VERSION 5.8 ;
BUSBITCHARS "[]" ;
DIVIDERCHAR "/" ;
UNITS
    DATABASE MICRONS 1000 ;
END UNITS

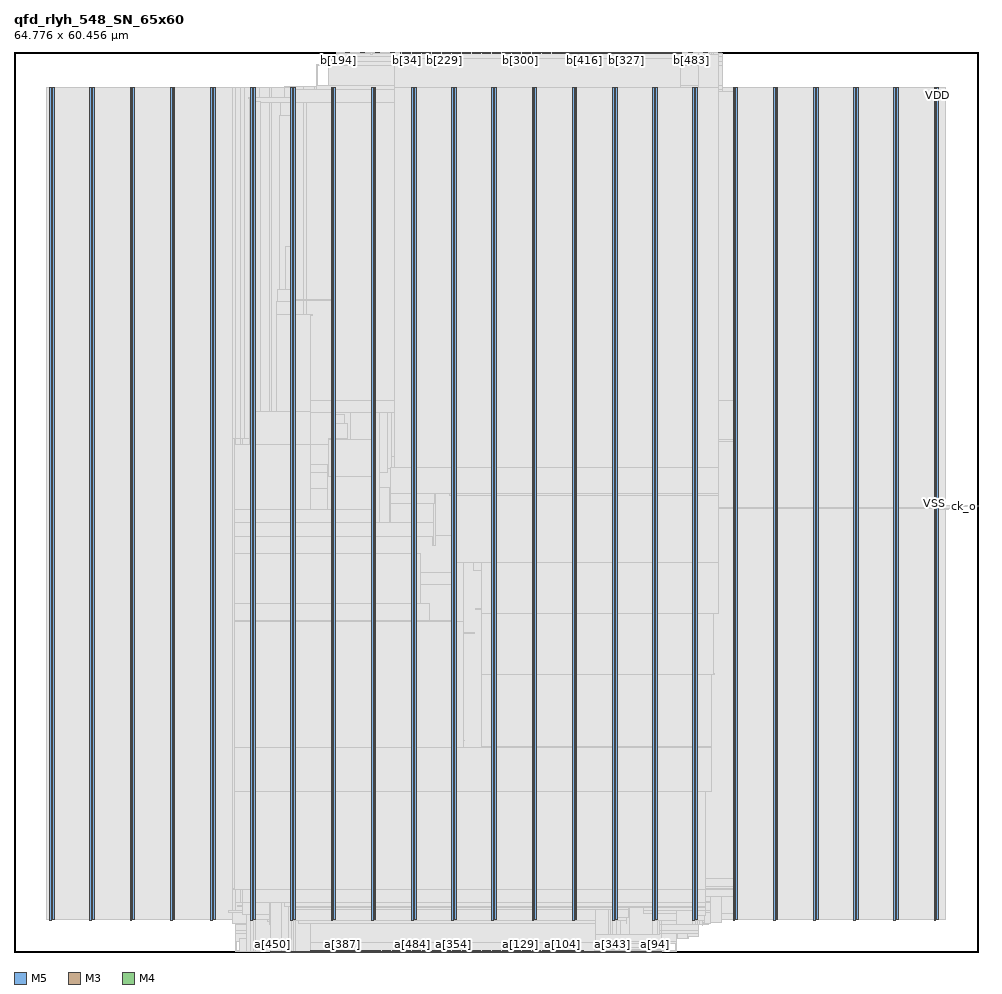
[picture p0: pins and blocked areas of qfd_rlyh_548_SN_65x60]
MACRO qfd_rlyh_548_SN_65x60
  FOREIGN qfd_rlyh_548_SN_65x60 0 0 ;
  CLASS BLOCK ;
  SIZE 64.776 BY 60.456 ;
  PIN a[0]
    DIRECTION INPUT ;
    USE SIGNAL ;
    PORT
      LAYER M5 ;
        RECT  35.28 0 35.304 0.084 ;
    END
  END a[0]
  PIN a[100]
    DIRECTION INPUT ;
    USE SIGNAL ;
    PORT
      LAYER M3 ;
        RECT  36.54 0 36.558 0.037 ;
    END
  END a[100]
  PIN a[101]
    DIRECTION INPUT ;
    USE SIGNAL ;
    PORT
      LAYER M3 ;
        RECT  36.612 0 36.63 0.037 ;
    END
  END a[101]
  PIN a[102]
    DIRECTION INPUT ;
    USE SIGNAL ;
    PORT
      LAYER M3 ;
        RECT  36.684 0 36.702 0.037 ;
    END
  END a[102]
  PIN a[103]
    DIRECTION INPUT ;
    USE SIGNAL ;
    PORT
      LAYER M3 ;
        RECT  36.756 0 36.774 0.037 ;
    END
  END a[103]
  PIN a[104]
    DIRECTION INPUT ;
    USE SIGNAL ;
    PORT
      LAYER M3 ;
        RECT  36.828 0 36.846 0.037 ;
    END
  END a[104]
  PIN a[105]
    DIRECTION INPUT ;
    USE SIGNAL ;
    PORT
      LAYER M3 ;
        RECT  36.9 0 36.918 0.037 ;
    END
  END a[105]
  PIN a[106]
    DIRECTION INPUT ;
    USE SIGNAL ;
    PORT
      LAYER M3 ;
        RECT  36.972 0 36.99 0.037 ;
    END
  END a[106]
  PIN a[107]
    DIRECTION INPUT ;
    USE SIGNAL ;
    PORT
      LAYER M3 ;
        RECT  37.044 0 37.062 0.037 ;
    END
  END a[107]
  PIN a[108]
    DIRECTION INPUT ;
    USE SIGNAL ;
    PORT
      LAYER M3 ;
        RECT  37.116 0 37.134 0.037 ;
    END
  END a[108]
  PIN a[109]
    DIRECTION INPUT ;
    USE SIGNAL ;
    PORT
      LAYER M3 ;
        RECT  37.188 0 37.206 0.037 ;
    END
  END a[109]
  PIN a[10]
    DIRECTION INPUT ;
    USE SIGNAL ;
    PORT
      LAYER M5 ;
        RECT  36.24 0 36.264 0.084 ;
    END
  END a[10]
  PIN a[110]
    DIRECTION INPUT ;
    USE SIGNAL ;
    PORT
      LAYER M3 ;
        RECT  37.26 0 37.278 0.037 ;
    END
  END a[110]
  PIN a[111]
    DIRECTION INPUT ;
    USE SIGNAL ;
    PORT
      LAYER M3 ;
        RECT  37.332 0 37.35 0.037 ;
    END
  END a[111]
  PIN a[112]
    DIRECTION INPUT ;
    USE SIGNAL ;
    PORT
      LAYER M3 ;
        RECT  37.404 0 37.422 0.037 ;
    END
  END a[112]
  PIN a[113]
    DIRECTION INPUT ;
    USE SIGNAL ;
    PORT
      LAYER M3 ;
        RECT  37.476 0 37.494 0.037 ;
    END
  END a[113]
  PIN a[114]
    DIRECTION INPUT ;
    USE SIGNAL ;
    PORT
      LAYER M3 ;
        RECT  37.548 0 37.566 0.037 ;
    END
  END a[114]
  PIN a[115]
    DIRECTION INPUT ;
    USE SIGNAL ;
    PORT
      LAYER M3 ;
        RECT  37.62 0 37.638 0.037 ;
    END
  END a[115]
  PIN a[116]
    DIRECTION INPUT ;
    USE SIGNAL ;
    PORT
      LAYER M3 ;
        RECT  37.692 0 37.71 0.037 ;
    END
  END a[116]
  PIN a[117]
    DIRECTION INPUT ;
    USE SIGNAL ;
    PORT
      LAYER M3 ;
        RECT  37.764 0 37.782 0.037 ;
    END
  END a[117]
  PIN a[118]
    DIRECTION INPUT ;
    USE SIGNAL ;
    PORT
      LAYER M3 ;
        RECT  37.836 0 37.854 0.037 ;
    END
  END a[118]
  PIN a[119]
    DIRECTION INPUT ;
    USE SIGNAL ;
    PORT
      LAYER M3 ;
        RECT  37.908 0 37.926 0.037 ;
    END
  END a[119]
  PIN a[11]
    DIRECTION INPUT ;
    USE SIGNAL ;
    PORT
      LAYER M5 ;
        RECT  36.336 0 36.36 0.084 ;
    END
  END a[11]
  PIN a[120]
    DIRECTION INPUT ;
    USE SIGNAL ;
    PORT
      LAYER M3 ;
        RECT  37.98 0 37.998 0.037 ;
    END
  END a[120]
  PIN a[121]
    DIRECTION INPUT ;
    USE SIGNAL ;
    PORT
      LAYER M3 ;
        RECT  38.052 0 38.07 0.037 ;
    END
  END a[121]
  PIN a[122]
    DIRECTION INPUT ;
    USE SIGNAL ;
    PORT
      LAYER M3 ;
        RECT  38.124 0 38.142 0.037 ;
    END
  END a[122]
  PIN a[123]
    DIRECTION INPUT ;
    USE SIGNAL ;
    PORT
      LAYER M3 ;
        RECT  38.196 0 38.214 0.037 ;
    END
  END a[123]
  PIN a[124]
    DIRECTION INPUT ;
    USE SIGNAL ;
    PORT
      LAYER M3 ;
        RECT  38.268 0 38.286 0.037 ;
    END
  END a[124]
  PIN a[125]
    DIRECTION INPUT ;
    USE SIGNAL ;
    PORT
      LAYER M3 ;
        RECT  38.34 0 38.358 0.037 ;
    END
  END a[125]
  PIN a[126]
    DIRECTION INPUT ;
    USE SIGNAL ;
    PORT
      LAYER M3 ;
        RECT  38.412 0 38.43 0.037 ;
    END
  END a[126]
  PIN a[127]
    DIRECTION INPUT ;
    USE SIGNAL ;
    PORT
      LAYER M3 ;
        RECT  38.484 0 38.502 0.037 ;
    END
  END a[127]
  PIN a[128]
    DIRECTION INPUT ;
    USE SIGNAL ;
    PORT
      LAYER M3 ;
        RECT  33.948 0 33.966 0.037 ;
    END
  END a[128]
  PIN a[129]
    DIRECTION INPUT ;
    USE SIGNAL ;
    PORT
      LAYER M3 ;
        RECT  34.02 0 34.038 0.037 ;
    END
  END a[129]
  PIN a[12]
    DIRECTION INPUT ;
    USE SIGNAL ;
    PORT
      LAYER M5 ;
        RECT  36.432 0 36.456 0.084 ;
    END
  END a[12]
  PIN a[130]
    DIRECTION INPUT ;
    USE SIGNAL ;
    PORT
      LAYER M3 ;
        RECT  34.092 0 34.11 0.037 ;
    END
  END a[130]
  PIN a[131]
    DIRECTION INPUT ;
    USE SIGNAL ;
    PORT
      LAYER M3 ;
        RECT  34.164 0 34.182 0.037 ;
    END
  END a[131]
  PIN a[132]
    DIRECTION INPUT ;
    USE SIGNAL ;
    PORT
      LAYER M3 ;
        RECT  34.236 0 34.254 0.037 ;
    END
  END a[132]
  PIN a[133]
    DIRECTION INPUT ;
    USE SIGNAL ;
    PORT
      LAYER M3 ;
        RECT  34.308 0 34.326 0.037 ;
    END
  END a[133]
  PIN a[134]
    DIRECTION INPUT ;
    USE SIGNAL ;
    PORT
      LAYER M3 ;
        RECT  34.38 0 34.398 0.037 ;
    END
  END a[134]
  PIN a[135]
    DIRECTION INPUT ;
    USE SIGNAL ;
    PORT
      LAYER M3 ;
        RECT  34.452 0 34.47 0.037 ;
    END
  END a[135]
  PIN a[136]
    DIRECTION INPUT ;
    USE SIGNAL ;
    PORT
      LAYER M3 ;
        RECT  34.524 0 34.542 0.037 ;
    END
  END a[136]
  PIN a[137]
    DIRECTION INPUT ;
    USE SIGNAL ;
    PORT
      LAYER M3 ;
        RECT  34.596 0 34.614 0.037 ;
    END
  END a[137]
  PIN a[138]
    DIRECTION INPUT ;
    USE SIGNAL ;
    PORT
      LAYER M3 ;
        RECT  34.668 0 34.686 0.037 ;
    END
  END a[138]
  PIN a[139]
    DIRECTION INPUT ;
    USE SIGNAL ;
    PORT
      LAYER M3 ;
        RECT  34.74 0 34.758 0.037 ;
    END
  END a[139]
  PIN a[13]
    DIRECTION INPUT ;
    USE SIGNAL ;
    PORT
      LAYER M5 ;
        RECT  36.528 0 36.552 0.084 ;
    END
  END a[13]
  PIN a[140]
    DIRECTION INPUT ;
    USE SIGNAL ;
    PORT
      LAYER M3 ;
        RECT  34.812 0 34.83 0.037 ;
    END
  END a[140]
  PIN a[141]
    DIRECTION INPUT ;
    USE SIGNAL ;
    PORT
      LAYER M3 ;
        RECT  34.884 0 34.902 0.037 ;
    END
  END a[141]
  PIN a[142]
    DIRECTION INPUT ;
    USE SIGNAL ;
    PORT
      LAYER M3 ;
        RECT  34.956 0 34.974 0.037 ;
    END
  END a[142]
  PIN a[143]
    DIRECTION INPUT ;
    USE SIGNAL ;
    PORT
      LAYER M3 ;
        RECT  35.028 0 35.046 0.037 ;
    END
  END a[143]
  PIN a[144]
    DIRECTION INPUT ;
    USE SIGNAL ;
    PORT
      LAYER M3 ;
        RECT  35.1 0 35.118 0.037 ;
    END
  END a[144]
  PIN a[145]
    DIRECTION INPUT ;
    USE SIGNAL ;
    PORT
      LAYER M3 ;
        RECT  35.172 0 35.19 0.037 ;
    END
  END a[145]
  PIN a[146]
    DIRECTION INPUT ;
    USE SIGNAL ;
    PORT
      LAYER M3 ;
        RECT  35.244 0 35.262 0.037 ;
    END
  END a[146]
  PIN a[147]
    DIRECTION INPUT ;
    USE SIGNAL ;
    PORT
      LAYER M3 ;
        RECT  35.316 0 35.334 0.037 ;
    END
  END a[147]
  PIN a[148]
    DIRECTION INPUT ;
    USE SIGNAL ;
    PORT
      LAYER M3 ;
        RECT  35.388 0 35.406 0.037 ;
    END
  END a[148]
  PIN a[149]
    DIRECTION INPUT ;
    USE SIGNAL ;
    PORT
      LAYER M3 ;
        RECT  35.46 0 35.478 0.037 ;
    END
  END a[149]
  PIN a[14]
    DIRECTION INPUT ;
    USE SIGNAL ;
    PORT
      LAYER M5 ;
        RECT  36.624 0 36.648 0.084 ;
    END
  END a[14]
  PIN a[150]
    DIRECTION INPUT ;
    USE SIGNAL ;
    PORT
      LAYER M3 ;
        RECT  35.532 0 35.55 0.037 ;
    END
  END a[150]
  PIN a[151]
    DIRECTION INPUT ;
    USE SIGNAL ;
    PORT
      LAYER M3 ;
        RECT  35.604 0 35.622 0.037 ;
    END
  END a[151]
  PIN a[152]
    DIRECTION INPUT ;
    USE SIGNAL ;
    PORT
      LAYER M3 ;
        RECT  35.676 0 35.694 0.037 ;
    END
  END a[152]
  PIN a[153]
    DIRECTION INPUT ;
    USE SIGNAL ;
    PORT
      LAYER M3 ;
        RECT  35.748 0 35.766 0.037 ;
    END
  END a[153]
  PIN a[154]
    DIRECTION INPUT ;
    USE SIGNAL ;
    PORT
      LAYER M3 ;
        RECT  35.82 0 35.838 0.037 ;
    END
  END a[154]
  PIN a[155]
    DIRECTION INPUT ;
    USE SIGNAL ;
    PORT
      LAYER M3 ;
        RECT  35.892 0 35.91 0.037 ;
    END
  END a[155]
  PIN a[156]
    DIRECTION INPUT ;
    USE SIGNAL ;
    PORT
      LAYER M3 ;
        RECT  35.964 0 35.982 0.037 ;
    END
  END a[156]
  PIN a[157]
    DIRECTION INPUT ;
    USE SIGNAL ;
    PORT
      LAYER M3 ;
        RECT  36.036 0 36.054 0.037 ;
    END
  END a[157]
  PIN a[158]
    DIRECTION INPUT ;
    USE SIGNAL ;
    PORT
      LAYER M3 ;
        RECT  36.108 0 36.126 0.037 ;
    END
  END a[158]
  PIN a[159]
    DIRECTION INPUT ;
    USE SIGNAL ;
    PORT
      LAYER M3 ;
        RECT  36.18 0 36.198 0.037 ;
    END
  END a[159]
  PIN a[15]
    DIRECTION INPUT ;
    USE SIGNAL ;
    PORT
      LAYER M5 ;
        RECT  36.72 0 36.744 0.084 ;
    END
  END a[15]
  PIN a[160]
    DIRECTION INPUT ;
    USE SIGNAL ;
    PORT
      LAYER M5 ;
        RECT  22.992 0 23.016 0.084 ;
    END
  END a[160]
  PIN a[161]
    DIRECTION INPUT ;
    USE SIGNAL ;
    PORT
      LAYER M5 ;
        RECT  23.088 0 23.112 0.084 ;
    END
  END a[161]
  PIN a[162]
    DIRECTION INPUT ;
    USE SIGNAL ;
    PORT
      LAYER M5 ;
        RECT  23.184 0 23.208 0.084 ;
    END
  END a[162]
  PIN a[163]
    DIRECTION INPUT ;
    USE SIGNAL ;
    PORT
      LAYER M5 ;
        RECT  23.28 0 23.304 0.084 ;
    END
  END a[163]
  PIN a[164]
    DIRECTION INPUT ;
    USE SIGNAL ;
    PORT
      LAYER M5 ;
        RECT  23.376 0 23.4 0.084 ;
    END
  END a[164]
  PIN a[165]
    DIRECTION INPUT ;
    USE SIGNAL ;
    PORT
      LAYER M5 ;
        RECT  23.472 0 23.496 0.084 ;
    END
  END a[165]
  PIN a[166]
    DIRECTION INPUT ;
    USE SIGNAL ;
    PORT
      LAYER M5 ;
        RECT  23.568 0 23.592 0.084 ;
    END
  END a[166]
  PIN a[167]
    DIRECTION INPUT ;
    USE SIGNAL ;
    PORT
      LAYER M5 ;
        RECT  23.664 0 23.688 0.084 ;
    END
  END a[167]
  PIN a[168]
    DIRECTION INPUT ;
    USE SIGNAL ;
    PORT
      LAYER M5 ;
        RECT  23.76 0 23.784 0.084 ;
    END
  END a[168]
  PIN a[169]
    DIRECTION INPUT ;
    USE SIGNAL ;
    PORT
      LAYER M5 ;
        RECT  23.856 0 23.88 0.084 ;
    END
  END a[169]
  PIN a[16]
    DIRECTION INPUT ;
    USE SIGNAL ;
    PORT
      LAYER M5 ;
        RECT  36.816 0 36.84 0.084 ;
    END
  END a[16]
  PIN a[170]
    DIRECTION INPUT ;
    USE SIGNAL ;
    PORT
      LAYER M5 ;
        RECT  23.952 0 23.976 0.084 ;
    END
  END a[170]
  PIN a[171]
    DIRECTION INPUT ;
    USE SIGNAL ;
    PORT
      LAYER M5 ;
        RECT  24.048 0 24.072 0.084 ;
    END
  END a[171]
  PIN a[172]
    DIRECTION INPUT ;
    USE SIGNAL ;
    PORT
      LAYER M5 ;
        RECT  24.144 0 24.168 0.084 ;
    END
  END a[172]
  PIN a[173]
    DIRECTION INPUT ;
    USE SIGNAL ;
    PORT
      LAYER M5 ;
        RECT  24.24 0 24.264 0.084 ;
    END
  END a[173]
  PIN a[174]
    DIRECTION INPUT ;
    USE SIGNAL ;
    PORT
      LAYER M5 ;
        RECT  24.336 0 24.36 0.084 ;
    END
  END a[174]
  PIN a[175]
    DIRECTION INPUT ;
    USE SIGNAL ;
    PORT
      LAYER M5 ;
        RECT  24.432 0 24.456 0.084 ;
    END
  END a[175]
  PIN a[176]
    DIRECTION INPUT ;
    USE SIGNAL ;
    PORT
      LAYER M5 ;
        RECT  24.528 0 24.552 0.084 ;
    END
  END a[176]
  PIN a[177]
    DIRECTION INPUT ;
    USE SIGNAL ;
    PORT
      LAYER M5 ;
        RECT  24.624 0 24.648 0.084 ;
    END
  END a[177]
  PIN a[178]
    DIRECTION INPUT ;
    USE SIGNAL ;
    PORT
      LAYER M5 ;
        RECT  24.72 0 24.744 0.084 ;
    END
  END a[178]
  PIN a[179]
    DIRECTION INPUT ;
    USE SIGNAL ;
    PORT
      LAYER M5 ;
        RECT  24.816 0 24.84 0.084 ;
    END
  END a[179]
  PIN a[17]
    DIRECTION INPUT ;
    USE SIGNAL ;
    PORT
      LAYER M5 ;
        RECT  36.912 0 36.936 0.084 ;
    END
  END a[17]
  PIN a[180]
    DIRECTION INPUT ;
    USE SIGNAL ;
    PORT
      LAYER M5 ;
        RECT  24.912 0 24.936 0.084 ;
    END
  END a[180]
  PIN a[181]
    DIRECTION INPUT ;
    USE SIGNAL ;
    PORT
      LAYER M5 ;
        RECT  25.008 0 25.032 0.084 ;
    END
  END a[181]
  PIN a[182]
    DIRECTION INPUT ;
    USE SIGNAL ;
    PORT
      LAYER M5 ;
        RECT  25.104 0 25.128 0.084 ;
    END
  END a[182]
  PIN a[183]
    DIRECTION INPUT ;
    USE SIGNAL ;
    PORT
      LAYER M5 ;
        RECT  25.2 0 25.224 0.084 ;
    END
  END a[183]
  PIN a[184]
    DIRECTION INPUT ;
    USE SIGNAL ;
    PORT
      LAYER M5 ;
        RECT  25.296 0 25.32 0.084 ;
    END
  END a[184]
  PIN a[185]
    DIRECTION INPUT ;
    USE SIGNAL ;
    PORT
      LAYER M5 ;
        RECT  25.392 0 25.416 0.084 ;
    END
  END a[185]
  PIN a[186]
    DIRECTION INPUT ;
    USE SIGNAL ;
    PORT
      LAYER M5 ;
        RECT  25.488 0 25.512 0.084 ;
    END
  END a[186]
  PIN a[187]
    DIRECTION INPUT ;
    USE SIGNAL ;
    PORT
      LAYER M5 ;
        RECT  25.584 0 25.608 0.084 ;
    END
  END a[187]
  PIN a[188]
    DIRECTION INPUT ;
    USE SIGNAL ;
    PORT
      LAYER M5 ;
        RECT  25.68 0 25.704 0.084 ;
    END
  END a[188]
  PIN a[189]
    DIRECTION INPUT ;
    USE SIGNAL ;
    PORT
      LAYER M5 ;
        RECT  25.776 0 25.8 0.084 ;
    END
  END a[189]
  PIN a[18]
    DIRECTION INPUT ;
    USE SIGNAL ;
    PORT
      LAYER M5 ;
        RECT  37.008 0 37.032 0.084 ;
    END
  END a[18]
  PIN a[190]
    DIRECTION INPUT ;
    USE SIGNAL ;
    PORT
      LAYER M5 ;
        RECT  25.872 0 25.896 0.084 ;
    END
  END a[190]
  PIN a[191]
    DIRECTION INPUT ;
    USE SIGNAL ;
    PORT
      LAYER M5 ;
        RECT  25.968 0 25.992 0.084 ;
    END
  END a[191]
  PIN a[192]
    DIRECTION INPUT ;
    USE SIGNAL ;
    PORT
      LAYER M5 ;
        RECT  19.92 0 19.944 0.084 ;
    END
  END a[192]
  PIN a[193]
    DIRECTION INPUT ;
    USE SIGNAL ;
    PORT
      LAYER M5 ;
        RECT  20.016 0 20.04 0.084 ;
    END
  END a[193]
  PIN a[194]
    DIRECTION INPUT ;
    USE SIGNAL ;
    PORT
      LAYER M5 ;
        RECT  20.112 0 20.136 0.084 ;
    END
  END a[194]
  PIN a[195]
    DIRECTION INPUT ;
    USE SIGNAL ;
    PORT
      LAYER M5 ;
        RECT  20.208 0 20.232 0.084 ;
    END
  END a[195]
  PIN a[196]
    DIRECTION INPUT ;
    USE SIGNAL ;
    PORT
      LAYER M5 ;
        RECT  20.304 0 20.328 0.084 ;
    END
  END a[196]
  PIN a[197]
    DIRECTION INPUT ;
    USE SIGNAL ;
    PORT
      LAYER M5 ;
        RECT  20.4 0 20.424 0.084 ;
    END
  END a[197]
  PIN a[198]
    DIRECTION INPUT ;
    USE SIGNAL ;
    PORT
      LAYER M5 ;
        RECT  20.496 0 20.52 0.084 ;
    END
  END a[198]
  PIN a[199]
    DIRECTION INPUT ;
    USE SIGNAL ;
    PORT
      LAYER M5 ;
        RECT  20.592 0 20.616 0.084 ;
    END
  END a[199]
  PIN a[19]
    DIRECTION INPUT ;
    USE SIGNAL ;
    PORT
      LAYER M5 ;
        RECT  37.104 0 37.128 0.084 ;
    END
  END a[19]
  PIN a[1]
    DIRECTION INPUT ;
    USE SIGNAL ;
    PORT
      LAYER M5 ;
        RECT  35.376 0 35.4 0.084 ;
    END
  END a[1]
  PIN a[200]
    DIRECTION INPUT ;
    USE SIGNAL ;
    PORT
      LAYER M5 ;
        RECT  20.688 0 20.712 0.084 ;
    END
  END a[200]
  PIN a[201]
    DIRECTION INPUT ;
    USE SIGNAL ;
    PORT
      LAYER M5 ;
        RECT  20.784 0 20.808 0.084 ;
    END
  END a[201]
  PIN a[202]
    DIRECTION INPUT ;
    USE SIGNAL ;
    PORT
      LAYER M5 ;
        RECT  20.88 0 20.904 0.084 ;
    END
  END a[202]
  PIN a[203]
    DIRECTION INPUT ;
    USE SIGNAL ;
    PORT
      LAYER M5 ;
        RECT  20.976 0 21 0.084 ;
    END
  END a[203]
  PIN a[204]
    DIRECTION INPUT ;
    USE SIGNAL ;
    PORT
      LAYER M5 ;
        RECT  21.072 0 21.096 0.084 ;
    END
  END a[204]
  PIN a[205]
    DIRECTION INPUT ;
    USE SIGNAL ;
    PORT
      LAYER M5 ;
        RECT  21.168 0 21.192 0.084 ;
    END
  END a[205]
  PIN a[206]
    DIRECTION INPUT ;
    USE SIGNAL ;
    PORT
      LAYER M5 ;
        RECT  21.264 0 21.288 0.084 ;
    END
  END a[206]
  PIN a[207]
    DIRECTION INPUT ;
    USE SIGNAL ;
    PORT
      LAYER M5 ;
        RECT  21.36 0 21.384 0.084 ;
    END
  END a[207]
  PIN a[208]
    DIRECTION INPUT ;
    USE SIGNAL ;
    PORT
      LAYER M5 ;
        RECT  21.456 0 21.48 0.084 ;
    END
  END a[208]
  PIN a[209]
    DIRECTION INPUT ;
    USE SIGNAL ;
    PORT
      LAYER M5 ;
        RECT  21.552 0 21.576 0.084 ;
    END
  END a[209]
  PIN a[20]
    DIRECTION INPUT ;
    USE SIGNAL ;
    PORT
      LAYER M5 ;
        RECT  37.2 0 37.224 0.084 ;
    END
  END a[20]
  PIN a[210]
    DIRECTION INPUT ;
    USE SIGNAL ;
    PORT
      LAYER M5 ;
        RECT  21.648 0 21.672 0.084 ;
    END
  END a[210]
  PIN a[211]
    DIRECTION INPUT ;
    USE SIGNAL ;
    PORT
      LAYER M5 ;
        RECT  21.744 0 21.768 0.084 ;
    END
  END a[211]
  PIN a[212]
    DIRECTION INPUT ;
    USE SIGNAL ;
    PORT
      LAYER M5 ;
        RECT  21.84 0 21.864 0.084 ;
    END
  END a[212]
  PIN a[213]
    DIRECTION INPUT ;
    USE SIGNAL ;
    PORT
      LAYER M5 ;
        RECT  21.936 0 21.96 0.084 ;
    END
  END a[213]
  PIN a[214]
    DIRECTION INPUT ;
    USE SIGNAL ;
    PORT
      LAYER M5 ;
        RECT  22.032 0 22.056 0.084 ;
    END
  END a[214]
  PIN a[215]
    DIRECTION INPUT ;
    USE SIGNAL ;
    PORT
      LAYER M5 ;
        RECT  22.128 0 22.152 0.084 ;
    END
  END a[215]
  PIN a[216]
    DIRECTION INPUT ;
    USE SIGNAL ;
    PORT
      LAYER M5 ;
        RECT  22.224 0 22.248 0.084 ;
    END
  END a[216]
  PIN a[217]
    DIRECTION INPUT ;
    USE SIGNAL ;
    PORT
      LAYER M5 ;
        RECT  22.32 0 22.344 0.084 ;
    END
  END a[217]
  PIN a[218]
    DIRECTION INPUT ;
    USE SIGNAL ;
    PORT
      LAYER M5 ;
        RECT  22.416 0 22.44 0.084 ;
    END
  END a[218]
  PIN a[219]
    DIRECTION INPUT ;
    USE SIGNAL ;
    PORT
      LAYER M5 ;
        RECT  22.512 0 22.536 0.084 ;
    END
  END a[219]
  PIN a[21]
    DIRECTION INPUT ;
    USE SIGNAL ;
    PORT
      LAYER M5 ;
        RECT  37.296 0 37.32 0.084 ;
    END
  END a[21]
  PIN a[220]
    DIRECTION INPUT ;
    USE SIGNAL ;
    PORT
      LAYER M5 ;
        RECT  22.608 0 22.632 0.084 ;
    END
  END a[220]
  PIN a[221]
    DIRECTION INPUT ;
    USE SIGNAL ;
    PORT
      LAYER M5 ;
        RECT  22.704 0 22.728 0.084 ;
    END
  END a[221]
  PIN a[222]
    DIRECTION INPUT ;
    USE SIGNAL ;
    PORT
      LAYER M5 ;
        RECT  22.8 0 22.824 0.084 ;
    END
  END a[222]
  PIN a[223]
    DIRECTION INPUT ;
    USE SIGNAL ;
    PORT
      LAYER M5 ;
        RECT  22.896 0 22.92 0.084 ;
    END
  END a[223]
  PIN a[224]
    DIRECTION INPUT ;
    USE SIGNAL ;
    PORT
      LAYER M5 ;
        RECT  29.136 0 29.16 0.084 ;
    END
  END a[224]
  PIN a[225]
    DIRECTION INPUT ;
    USE SIGNAL ;
    PORT
      LAYER M5 ;
        RECT  29.232 0 29.256 0.084 ;
    END
  END a[225]
  PIN a[226]
    DIRECTION INPUT ;
    USE SIGNAL ;
    PORT
      LAYER M5 ;
        RECT  29.328 0 29.352 0.084 ;
    END
  END a[226]
  PIN a[227]
    DIRECTION INPUT ;
    USE SIGNAL ;
    PORT
      LAYER M5 ;
        RECT  29.424 0 29.448 0.084 ;
    END
  END a[227]
  PIN a[228]
    DIRECTION INPUT ;
    USE SIGNAL ;
    PORT
      LAYER M5 ;
        RECT  29.52 0 29.544 0.084 ;
    END
  END a[228]
  PIN a[229]
    DIRECTION INPUT ;
    USE SIGNAL ;
    PORT
      LAYER M5 ;
        RECT  29.616 0 29.64 0.084 ;
    END
  END a[229]
  PIN a[22]
    DIRECTION INPUT ;
    USE SIGNAL ;
    PORT
      LAYER M5 ;
        RECT  37.392 0 37.416 0.084 ;
    END
  END a[22]
  PIN a[230]
    DIRECTION INPUT ;
    USE SIGNAL ;
    PORT
      LAYER M5 ;
        RECT  29.712 0 29.736 0.084 ;
    END
  END a[230]
  PIN a[231]
    DIRECTION INPUT ;
    USE SIGNAL ;
    PORT
      LAYER M5 ;
        RECT  29.808 0 29.832 0.084 ;
    END
  END a[231]
  PIN a[232]
    DIRECTION INPUT ;
    USE SIGNAL ;
    PORT
      LAYER M5 ;
        RECT  29.904 0 29.928 0.084 ;
    END
  END a[232]
  PIN a[233]
    DIRECTION INPUT ;
    USE SIGNAL ;
    PORT
      LAYER M5 ;
        RECT  30 0 30.024 0.084 ;
    END
  END a[233]
  PIN a[234]
    DIRECTION INPUT ;
    USE SIGNAL ;
    PORT
      LAYER M5 ;
        RECT  30.096 0 30.12 0.084 ;
    END
  END a[234]
  PIN a[235]
    DIRECTION INPUT ;
    USE SIGNAL ;
    PORT
      LAYER M5 ;
        RECT  30.192 0 30.216 0.084 ;
    END
  END a[235]
  PIN a[236]
    DIRECTION INPUT ;
    USE SIGNAL ;
    PORT
      LAYER M5 ;
        RECT  30.288 0 30.312 0.084 ;
    END
  END a[236]
  PIN a[237]
    DIRECTION INPUT ;
    USE SIGNAL ;
    PORT
      LAYER M5 ;
        RECT  30.384 0 30.408 0.084 ;
    END
  END a[237]
  PIN a[238]
    DIRECTION INPUT ;
    USE SIGNAL ;
    PORT
      LAYER M5 ;
        RECT  30.48 0 30.504 0.084 ;
    END
  END a[238]
  PIN a[239]
    DIRECTION INPUT ;
    USE SIGNAL ;
    PORT
      LAYER M5 ;
        RECT  30.576 0 30.6 0.084 ;
    END
  END a[239]
  PIN a[23]
    DIRECTION INPUT ;
    USE SIGNAL ;
    PORT
      LAYER M5 ;
        RECT  37.488 0 37.512 0.084 ;
    END
  END a[23]
  PIN a[240]
    DIRECTION INPUT ;
    USE SIGNAL ;
    PORT
      LAYER M5 ;
        RECT  30.672 0 30.696 0.084 ;
    END
  END a[240]
  PIN a[241]
    DIRECTION INPUT ;
    USE SIGNAL ;
    PORT
      LAYER M5 ;
        RECT  30.768 0 30.792 0.084 ;
    END
  END a[241]
  PIN a[242]
    DIRECTION INPUT ;
    USE SIGNAL ;
    PORT
      LAYER M5 ;
        RECT  30.864 0 30.888 0.084 ;
    END
  END a[242]
  PIN a[243]
    DIRECTION INPUT ;
    USE SIGNAL ;
    PORT
      LAYER M5 ;
        RECT  30.96 0 30.984 0.084 ;
    END
  END a[243]
  PIN a[244]
    DIRECTION INPUT ;
    USE SIGNAL ;
    PORT
      LAYER M5 ;
        RECT  31.056 0 31.08 0.084 ;
    END
  END a[244]
  PIN a[245]
    DIRECTION INPUT ;
    USE SIGNAL ;
    PORT
      LAYER M5 ;
        RECT  31.152 0 31.176 0.084 ;
    END
  END a[245]
  PIN a[246]
    DIRECTION INPUT ;
    USE SIGNAL ;
    PORT
      LAYER M5 ;
        RECT  31.248 0 31.272 0.084 ;
    END
  END a[246]
  PIN a[247]
    DIRECTION INPUT ;
    USE SIGNAL ;
    PORT
      LAYER M5 ;
        RECT  31.344 0 31.368 0.084 ;
    END
  END a[247]
  PIN a[248]
    DIRECTION INPUT ;
    USE SIGNAL ;
    PORT
      LAYER M5 ;
        RECT  31.44 0 31.464 0.084 ;
    END
  END a[248]
  PIN a[249]
    DIRECTION INPUT ;
    USE SIGNAL ;
    PORT
      LAYER M5 ;
        RECT  31.536 0 31.56 0.084 ;
    END
  END a[249]
  PIN a[24]
    DIRECTION INPUT ;
    USE SIGNAL ;
    PORT
      LAYER M5 ;
        RECT  37.584 0 37.608 0.084 ;
    END
  END a[24]
  PIN a[250]
    DIRECTION INPUT ;
    USE SIGNAL ;
    PORT
      LAYER M5 ;
        RECT  31.632 0 31.656 0.084 ;
    END
  END a[250]
  PIN a[251]
    DIRECTION INPUT ;
    USE SIGNAL ;
    PORT
      LAYER M5 ;
        RECT  31.728 0 31.752 0.084 ;
    END
  END a[251]
  PIN a[252]
    DIRECTION INPUT ;
    USE SIGNAL ;
    PORT
      LAYER M5 ;
        RECT  31.824 0 31.848 0.084 ;
    END
  END a[252]
  PIN a[253]
    DIRECTION INPUT ;
    USE SIGNAL ;
    PORT
      LAYER M5 ;
        RECT  31.92 0 31.944 0.084 ;
    END
  END a[253]
  PIN a[254]
    DIRECTION INPUT ;
    USE SIGNAL ;
    PORT
      LAYER M5 ;
        RECT  32.016 0 32.04 0.084 ;
    END
  END a[254]
  PIN a[255]
    DIRECTION INPUT ;
    USE SIGNAL ;
    PORT
      LAYER M5 ;
        RECT  32.112 0 32.136 0.084 ;
    END
  END a[255]
  PIN a[256]
    DIRECTION INPUT ;
    USE SIGNAL ;
    PORT
      LAYER M5 ;
        RECT  32.208 0 32.232 0.084 ;
    END
  END a[256]
  PIN a[257]
    DIRECTION INPUT ;
    USE SIGNAL ;
    PORT
      LAYER M5 ;
        RECT  32.304 0 32.328 0.084 ;
    END
  END a[257]
  PIN a[258]
    DIRECTION INPUT ;
    USE SIGNAL ;
    PORT
      LAYER M5 ;
        RECT  32.4 0 32.424 0.084 ;
    END
  END a[258]
  PIN a[259]
    DIRECTION INPUT ;
    USE SIGNAL ;
    PORT
      LAYER M5 ;
        RECT  32.496 0 32.52 0.084 ;
    END
  END a[259]
  PIN a[25]
    DIRECTION INPUT ;
    USE SIGNAL ;
    PORT
      LAYER M5 ;
        RECT  37.68 0 37.704 0.084 ;
    END
  END a[25]
  PIN a[260]
    DIRECTION INPUT ;
    USE SIGNAL ;
    PORT
      LAYER M5 ;
        RECT  32.592 0 32.616 0.084 ;
    END
  END a[260]
  PIN a[261]
    DIRECTION INPUT ;
    USE SIGNAL ;
    PORT
      LAYER M5 ;
        RECT  32.688 0 32.712 0.084 ;
    END
  END a[261]
  PIN a[262]
    DIRECTION INPUT ;
    USE SIGNAL ;
    PORT
      LAYER M5 ;
        RECT  32.784 0 32.808 0.084 ;
    END
  END a[262]
  PIN a[263]
    DIRECTION INPUT ;
    USE SIGNAL ;
    PORT
      LAYER M5 ;
        RECT  32.88 0 32.904 0.084 ;
    END
  END a[263]
  PIN a[264]
    DIRECTION INPUT ;
    USE SIGNAL ;
    PORT
      LAYER M5 ;
        RECT  32.976 0 33 0.084 ;
    END
  END a[264]
  PIN a[265]
    DIRECTION INPUT ;
    USE SIGNAL ;
    PORT
      LAYER M5 ;
        RECT  33.072 0 33.096 0.084 ;
    END
  END a[265]
  PIN a[266]
    DIRECTION INPUT ;
    USE SIGNAL ;
    PORT
      LAYER M5 ;
        RECT  33.168 0 33.192 0.084 ;
    END
  END a[266]
  PIN a[267]
    DIRECTION INPUT ;
    USE SIGNAL ;
    PORT
      LAYER M5 ;
        RECT  33.264 0 33.288 0.084 ;
    END
  END a[267]
  PIN a[268]
    DIRECTION INPUT ;
    USE SIGNAL ;
    PORT
      LAYER M5 ;
        RECT  33.36 0 33.384 0.084 ;
    END
  END a[268]
  PIN a[269]
    DIRECTION INPUT ;
    USE SIGNAL ;
    PORT
      LAYER M5 ;
        RECT  33.456 0 33.48 0.084 ;
    END
  END a[269]
  PIN a[26]
    DIRECTION INPUT ;
    USE SIGNAL ;
    PORT
      LAYER M5 ;
        RECT  37.776 0 37.8 0.084 ;
    END
  END a[26]
  PIN a[270]
    DIRECTION INPUT ;
    USE SIGNAL ;
    PORT
      LAYER M5 ;
        RECT  33.552 0 33.576 0.084 ;
    END
  END a[270]
  PIN a[271]
    DIRECTION INPUT ;
    USE SIGNAL ;
    PORT
      LAYER M5 ;
        RECT  33.648 0 33.672 0.084 ;
    END
  END a[271]
  PIN a[272]
    DIRECTION INPUT ;
    USE SIGNAL ;
    PORT
      LAYER M5 ;
        RECT  33.744 0 33.768 0.084 ;
    END
  END a[272]
  PIN a[273]
    DIRECTION INPUT ;
    USE SIGNAL ;
    PORT
      LAYER M5 ;
        RECT  33.84 0 33.864 0.084 ;
    END
  END a[273]
  PIN a[274]
    DIRECTION INPUT ;
    USE SIGNAL ;
    PORT
      LAYER M5 ;
        RECT  33.936 0 33.96 0.084 ;
    END
  END a[274]
  PIN a[275]
    DIRECTION INPUT ;
    USE SIGNAL ;
    PORT
      LAYER M5 ;
        RECT  34.032 0 34.056 0.084 ;
    END
  END a[275]
  PIN a[276]
    DIRECTION INPUT ;
    USE SIGNAL ;
    PORT
      LAYER M5 ;
        RECT  34.128 0 34.152 0.084 ;
    END
  END a[276]
  PIN a[277]
    DIRECTION INPUT ;
    USE SIGNAL ;
    PORT
      LAYER M5 ;
        RECT  34.224 0 34.248 0.084 ;
    END
  END a[277]
  PIN a[278]
    DIRECTION INPUT ;
    USE SIGNAL ;
    PORT
      LAYER M5 ;
        RECT  34.32 0 34.344 0.084 ;
    END
  END a[278]
  PIN a[279]
    DIRECTION INPUT ;
    USE SIGNAL ;
    PORT
      LAYER M5 ;
        RECT  34.416 0 34.44 0.084 ;
    END
  END a[279]
  PIN a[27]
    DIRECTION INPUT ;
    USE SIGNAL ;
    PORT
      LAYER M5 ;
        RECT  37.872 0 37.896 0.084 ;
    END
  END a[27]
  PIN a[280]
    DIRECTION INPUT ;
    USE SIGNAL ;
    PORT
      LAYER M5 ;
        RECT  34.512 0 34.536 0.084 ;
    END
  END a[280]
  PIN a[281]
    DIRECTION INPUT ;
    USE SIGNAL ;
    PORT
      LAYER M5 ;
        RECT  34.608 0 34.632 0.084 ;
    END
  END a[281]
  PIN a[282]
    DIRECTION INPUT ;
    USE SIGNAL ;
    PORT
      LAYER M5 ;
        RECT  34.704 0 34.728 0.084 ;
    END
  END a[282]
  PIN a[283]
    DIRECTION INPUT ;
    USE SIGNAL ;
    PORT
      LAYER M5 ;
        RECT  34.8 0 34.824 0.084 ;
    END
  END a[283]
  PIN a[284]
    DIRECTION INPUT ;
    USE SIGNAL ;
    PORT
      LAYER M5 ;
        RECT  34.896 0 34.92 0.084 ;
    END
  END a[284]
  PIN a[285]
    DIRECTION INPUT ;
    USE SIGNAL ;
    PORT
      LAYER M5 ;
        RECT  34.992 0 35.016 0.084 ;
    END
  END a[285]
  PIN a[286]
    DIRECTION INPUT ;
    USE SIGNAL ;
    PORT
      LAYER M5 ;
        RECT  35.088 0 35.112 0.084 ;
    END
  END a[286]
  PIN a[287]
    DIRECTION INPUT ;
    USE SIGNAL ;
    PORT
      LAYER M5 ;
        RECT  35.184 0 35.208 0.084 ;
    END
  END a[287]
  PIN a[288]
    DIRECTION INPUT ;
    USE SIGNAL ;
    PORT
      LAYER M3 ;
        RECT  31.644 0 31.662 0.037 ;
    END
  END a[288]
  PIN a[289]
    DIRECTION INPUT ;
    USE SIGNAL ;
    PORT
      LAYER M3 ;
        RECT  31.716 0 31.734 0.037 ;
    END
  END a[289]
  PIN a[28]
    DIRECTION INPUT ;
    USE SIGNAL ;
    PORT
      LAYER M5 ;
        RECT  37.968 0 37.992 0.084 ;
    END
  END a[28]
  PIN a[290]
    DIRECTION INPUT ;
    USE SIGNAL ;
    PORT
      LAYER M3 ;
        RECT  31.788 0 31.806 0.037 ;
    END
  END a[290]
  PIN a[291]
    DIRECTION INPUT ;
    USE SIGNAL ;
    PORT
      LAYER M3 ;
        RECT  31.86 0 31.878 0.037 ;
    END
  END a[291]
  PIN a[292]
    DIRECTION INPUT ;
    USE SIGNAL ;
    PORT
      LAYER M3 ;
        RECT  31.932 0 31.95 0.037 ;
    END
  END a[292]
  PIN a[293]
    DIRECTION INPUT ;
    USE SIGNAL ;
    PORT
      LAYER M3 ;
        RECT  32.004 0 32.022 0.037 ;
    END
  END a[293]
  PIN a[294]
    DIRECTION INPUT ;
    USE SIGNAL ;
    PORT
      LAYER M3 ;
        RECT  32.076 0 32.094 0.037 ;
    END
  END a[294]
  PIN a[295]
    DIRECTION INPUT ;
    USE SIGNAL ;
    PORT
      LAYER M3 ;
        RECT  32.148 0 32.166 0.037 ;
    END
  END a[295]
  PIN a[296]
    DIRECTION INPUT ;
    USE SIGNAL ;
    PORT
      LAYER M3 ;
        RECT  32.22 0 32.238 0.037 ;
    END
  END a[296]
  PIN a[297]
    DIRECTION INPUT ;
    USE SIGNAL ;
    PORT
      LAYER M3 ;
        RECT  32.292 0 32.31 0.037 ;
    END
  END a[297]
  PIN a[298]
    DIRECTION INPUT ;
    USE SIGNAL ;
    PORT
      LAYER M3 ;
        RECT  32.364 0 32.382 0.037 ;
    END
  END a[298]
  PIN a[299]
    DIRECTION INPUT ;
    USE SIGNAL ;
    PORT
      LAYER M3 ;
        RECT  32.436 0 32.454 0.037 ;
    END
  END a[299]
  PIN a[29]
    DIRECTION INPUT ;
    USE SIGNAL ;
    PORT
      LAYER M5 ;
        RECT  38.064 0 38.088 0.084 ;
    END
  END a[29]
  PIN a[2]
    DIRECTION INPUT ;
    USE SIGNAL ;
    PORT
      LAYER M5 ;
        RECT  35.472 0 35.496 0.084 ;
    END
  END a[2]
  PIN a[300]
    DIRECTION INPUT ;
    USE SIGNAL ;
    PORT
      LAYER M3 ;
        RECT  32.508 0 32.526 0.037 ;
    END
  END a[300]
  PIN a[301]
    DIRECTION INPUT ;
    USE SIGNAL ;
    PORT
      LAYER M3 ;
        RECT  32.58 0 32.598 0.037 ;
    END
  END a[301]
  PIN a[302]
    DIRECTION INPUT ;
    USE SIGNAL ;
    PORT
      LAYER M3 ;
        RECT  32.652 0 32.67 0.037 ;
    END
  END a[302]
  PIN a[303]
    DIRECTION INPUT ;
    USE SIGNAL ;
    PORT
      LAYER M3 ;
        RECT  32.724 0 32.742 0.037 ;
    END
  END a[303]
  PIN a[304]
    DIRECTION INPUT ;
    USE SIGNAL ;
    PORT
      LAYER M3 ;
        RECT  32.796 0 32.814 0.037 ;
    END
  END a[304]
  PIN a[305]
    DIRECTION INPUT ;
    USE SIGNAL ;
    PORT
      LAYER M3 ;
        RECT  32.868 0 32.886 0.037 ;
    END
  END a[305]
  PIN a[306]
    DIRECTION INPUT ;
    USE SIGNAL ;
    PORT
      LAYER M3 ;
        RECT  32.94 0 32.958 0.037 ;
    END
  END a[306]
  PIN a[307]
    DIRECTION INPUT ;
    USE SIGNAL ;
    PORT
      LAYER M3 ;
        RECT  33.012 0 33.03 0.037 ;
    END
  END a[307]
  PIN a[308]
    DIRECTION INPUT ;
    USE SIGNAL ;
    PORT
      LAYER M3 ;
        RECT  33.084 0 33.102 0.037 ;
    END
  END a[308]
  PIN a[309]
    DIRECTION INPUT ;
    USE SIGNAL ;
    PORT
      LAYER M3 ;
        RECT  33.156 0 33.174 0.037 ;
    END
  END a[309]
  PIN a[30]
    DIRECTION INPUT ;
    USE SIGNAL ;
    PORT
      LAYER M5 ;
        RECT  38.16 0 38.184 0.084 ;
    END
  END a[30]
  PIN a[310]
    DIRECTION INPUT ;
    USE SIGNAL ;
    PORT
      LAYER M3 ;
        RECT  33.228 0 33.246 0.037 ;
    END
  END a[310]
  PIN a[311]
    DIRECTION INPUT ;
    USE SIGNAL ;
    PORT
      LAYER M3 ;
        RECT  33.3 0 33.318 0.037 ;
    END
  END a[311]
  PIN a[312]
    DIRECTION INPUT ;
    USE SIGNAL ;
    PORT
      LAYER M3 ;
        RECT  33.372 0 33.39 0.037 ;
    END
  END a[312]
  PIN a[313]
    DIRECTION INPUT ;
    USE SIGNAL ;
    PORT
      LAYER M3 ;
        RECT  33.444 0 33.462 0.037 ;
    END
  END a[313]
  PIN a[314]
    DIRECTION INPUT ;
    USE SIGNAL ;
    PORT
      LAYER M3 ;
        RECT  33.516 0 33.534 0.037 ;
    END
  END a[314]
  PIN a[315]
    DIRECTION INPUT ;
    USE SIGNAL ;
    PORT
      LAYER M3 ;
        RECT  33.588 0 33.606 0.037 ;
    END
  END a[315]
  PIN a[316]
    DIRECTION INPUT ;
    USE SIGNAL ;
    PORT
      LAYER M3 ;
        RECT  33.66 0 33.678 0.037 ;
    END
  END a[316]
  PIN a[317]
    DIRECTION INPUT ;
    USE SIGNAL ;
    PORT
      LAYER M3 ;
        RECT  33.732 0 33.75 0.037 ;
    END
  END a[317]
  PIN a[318]
    DIRECTION INPUT ;
    USE SIGNAL ;
    PORT
      LAYER M3 ;
        RECT  33.804 0 33.822 0.037 ;
    END
  END a[318]
  PIN a[319]
    DIRECTION INPUT ;
    USE SIGNAL ;
    PORT
      LAYER M3 ;
        RECT  33.876 0 33.894 0.037 ;
    END
  END a[319]
  PIN a[31]
    DIRECTION INPUT ;
    USE SIGNAL ;
    PORT
      LAYER M5 ;
        RECT  38.256 0 38.28 0.084 ;
    END
  END a[31]
  PIN a[320]
    DIRECTION INPUT ;
    USE SIGNAL ;
    PORT
      LAYER M3 ;
        RECT  38.556 0 38.574 0.037 ;
    END
  END a[320]
  PIN a[321]
    DIRECTION INPUT ;
    USE SIGNAL ;
    PORT
      LAYER M3 ;
        RECT  38.628 0 38.646 0.037 ;
    END
  END a[321]
  PIN a[322]
    DIRECTION INPUT ;
    USE SIGNAL ;
    PORT
      LAYER M3 ;
        RECT  38.7 0 38.718 0.037 ;
    END
  END a[322]
  PIN a[323]
    DIRECTION INPUT ;
    USE SIGNAL ;
    PORT
      LAYER M3 ;
        RECT  38.772 0 38.79 0.037 ;
    END
  END a[323]
  PIN a[324]
    DIRECTION INPUT ;
    USE SIGNAL ;
    PORT
      LAYER M3 ;
        RECT  38.844 0 38.862 0.037 ;
    END
  END a[324]
  PIN a[325]
    DIRECTION INPUT ;
    USE SIGNAL ;
    PORT
      LAYER M3 ;
        RECT  38.916 0 38.934 0.037 ;
    END
  END a[325]
  PIN a[326]
    DIRECTION INPUT ;
    USE SIGNAL ;
    PORT
      LAYER M3 ;
        RECT  38.988 0 39.006 0.037 ;
    END
  END a[326]
  PIN a[327]
    DIRECTION INPUT ;
    USE SIGNAL ;
    PORT
      LAYER M3 ;
        RECT  39.06 0 39.078 0.037 ;
    END
  END a[327]
  PIN a[328]
    DIRECTION INPUT ;
    USE SIGNAL ;
    PORT
      LAYER M3 ;
        RECT  39.132 0 39.15 0.037 ;
    END
  END a[328]
  PIN a[329]
    DIRECTION INPUT ;
    USE SIGNAL ;
    PORT
      LAYER M3 ;
        RECT  39.204 0 39.222 0.037 ;
    END
  END a[329]
  PIN a[32]
    DIRECTION INPUT ;
    USE SIGNAL ;
    PORT
      LAYER M5 ;
        RECT  26.064 0 26.088 0.084 ;
    END
  END a[32]
  PIN a[330]
    DIRECTION INPUT ;
    USE SIGNAL ;
    PORT
      LAYER M3 ;
        RECT  39.276 0 39.294 0.037 ;
    END
  END a[330]
  PIN a[331]
    DIRECTION INPUT ;
    USE SIGNAL ;
    PORT
      LAYER M3 ;
        RECT  39.348 0 39.366 0.037 ;
    END
  END a[331]
  PIN a[332]
    DIRECTION INPUT ;
    USE SIGNAL ;
    PORT
      LAYER M3 ;
        RECT  39.42 0 39.438 0.037 ;
    END
  END a[332]
  PIN a[333]
    DIRECTION INPUT ;
    USE SIGNAL ;
    PORT
      LAYER M3 ;
        RECT  39.492 0 39.51 0.037 ;
    END
  END a[333]
  PIN a[334]
    DIRECTION INPUT ;
    USE SIGNAL ;
    PORT
      LAYER M3 ;
        RECT  39.564 0 39.582 0.037 ;
    END
  END a[334]
  PIN a[335]
    DIRECTION INPUT ;
    USE SIGNAL ;
    PORT
      LAYER M3 ;
        RECT  39.636 0 39.654 0.037 ;
    END
  END a[335]
  PIN a[336]
    DIRECTION INPUT ;
    USE SIGNAL ;
    PORT
      LAYER M3 ;
        RECT  39.708 0 39.726 0.037 ;
    END
  END a[336]
  PIN a[337]
    DIRECTION INPUT ;
    USE SIGNAL ;
    PORT
      LAYER M3 ;
        RECT  39.78 0 39.798 0.037 ;
    END
  END a[337]
  PIN a[338]
    DIRECTION INPUT ;
    USE SIGNAL ;
    PORT
      LAYER M3 ;
        RECT  39.852 0 39.87 0.037 ;
    END
  END a[338]
  PIN a[339]
    DIRECTION INPUT ;
    USE SIGNAL ;
    PORT
      LAYER M3 ;
        RECT  39.924 0 39.942 0.037 ;
    END
  END a[339]
  PIN a[33]
    DIRECTION INPUT ;
    USE SIGNAL ;
    PORT
      LAYER M5 ;
        RECT  26.16 0 26.184 0.084 ;
    END
  END a[33]
  PIN a[340]
    DIRECTION INPUT ;
    USE SIGNAL ;
    PORT
      LAYER M3 ;
        RECT  39.996 0 40.014 0.037 ;
    END
  END a[340]
  PIN a[341]
    DIRECTION INPUT ;
    USE SIGNAL ;
    PORT
      LAYER M3 ;
        RECT  40.068 0 40.086 0.037 ;
    END
  END a[341]
  PIN a[342]
    DIRECTION INPUT ;
    USE SIGNAL ;
    PORT
      LAYER M3 ;
        RECT  40.14 0 40.158 0.037 ;
    END
  END a[342]
  PIN a[343]
    DIRECTION INPUT ;
    USE SIGNAL ;
    PORT
      LAYER M3 ;
        RECT  40.212 0 40.23 0.037 ;
    END
  END a[343]
  PIN a[344]
    DIRECTION INPUT ;
    USE SIGNAL ;
    PORT
      LAYER M3 ;
        RECT  40.284 0 40.302 0.037 ;
    END
  END a[344]
  PIN a[345]
    DIRECTION INPUT ;
    USE SIGNAL ;
    PORT
      LAYER M3 ;
        RECT  40.356 0 40.374 0.037 ;
    END
  END a[345]
  PIN a[346]
    DIRECTION INPUT ;
    USE SIGNAL ;
    PORT
      LAYER M3 ;
        RECT  40.428 0 40.446 0.037 ;
    END
  END a[346]
  PIN a[347]
    DIRECTION INPUT ;
    USE SIGNAL ;
    PORT
      LAYER M3 ;
        RECT  40.5 0 40.518 0.037 ;
    END
  END a[347]
  PIN a[348]
    DIRECTION INPUT ;
    USE SIGNAL ;
    PORT
      LAYER M3 ;
        RECT  40.572 0 40.59 0.037 ;
    END
  END a[348]
  PIN a[349]
    DIRECTION INPUT ;
    USE SIGNAL ;
    PORT
      LAYER M3 ;
        RECT  40.644 0 40.662 0.037 ;
    END
  END a[349]
  PIN a[34]
    DIRECTION INPUT ;
    USE SIGNAL ;
    PORT
      LAYER M5 ;
        RECT  26.256 0 26.28 0.084 ;
    END
  END a[34]
  PIN a[350]
    DIRECTION INPUT ;
    USE SIGNAL ;
    PORT
      LAYER M3 ;
        RECT  40.716 0 40.734 0.037 ;
    END
  END a[350]
  PIN a[351]
    DIRECTION INPUT ;
    USE SIGNAL ;
    PORT
      LAYER M3 ;
        RECT  40.788 0 40.806 0.037 ;
    END
  END a[351]
  PIN a[352]
    DIRECTION INPUT ;
    USE SIGNAL ;
    PORT
      LAYER M3 ;
        RECT  29.34 0 29.358 0.037 ;
    END
  END a[352]
  PIN a[353]
    DIRECTION INPUT ;
    USE SIGNAL ;
    PORT
      LAYER M3 ;
        RECT  29.412 0 29.43 0.037 ;
    END
  END a[353]
  PIN a[354]
    DIRECTION INPUT ;
    USE SIGNAL ;
    PORT
      LAYER M3 ;
        RECT  29.484 0 29.502 0.037 ;
    END
  END a[354]
  PIN a[355]
    DIRECTION INPUT ;
    USE SIGNAL ;
    PORT
      LAYER M3 ;
        RECT  29.556 0 29.574 0.037 ;
    END
  END a[355]
  PIN a[356]
    DIRECTION INPUT ;
    USE SIGNAL ;
    PORT
      LAYER M3 ;
        RECT  29.628 0 29.646 0.037 ;
    END
  END a[356]
  PIN a[357]
    DIRECTION INPUT ;
    USE SIGNAL ;
    PORT
      LAYER M3 ;
        RECT  29.7 0 29.718 0.037 ;
    END
  END a[357]
  PIN a[358]
    DIRECTION INPUT ;
    USE SIGNAL ;
    PORT
      LAYER M3 ;
        RECT  29.772 0 29.79 0.037 ;
    END
  END a[358]
  PIN a[359]
    DIRECTION INPUT ;
    USE SIGNAL ;
    PORT
      LAYER M3 ;
        RECT  29.844 0 29.862 0.037 ;
    END
  END a[359]
  PIN a[35]
    DIRECTION INPUT ;
    USE SIGNAL ;
    PORT
      LAYER M5 ;
        RECT  26.352 0 26.376 0.084 ;
    END
  END a[35]
  PIN a[360]
    DIRECTION INPUT ;
    USE SIGNAL ;
    PORT
      LAYER M3 ;
        RECT  29.916 0 29.934 0.037 ;
    END
  END a[360]
  PIN a[361]
    DIRECTION INPUT ;
    USE SIGNAL ;
    PORT
      LAYER M3 ;
        RECT  29.988 0 30.006 0.037 ;
    END
  END a[361]
  PIN a[362]
    DIRECTION INPUT ;
    USE SIGNAL ;
    PORT
      LAYER M3 ;
        RECT  30.06 0 30.078 0.037 ;
    END
  END a[362]
  PIN a[363]
    DIRECTION INPUT ;
    USE SIGNAL ;
    PORT
      LAYER M3 ;
        RECT  30.132 0 30.15 0.037 ;
    END
  END a[363]
  PIN a[364]
    DIRECTION INPUT ;
    USE SIGNAL ;
    PORT
      LAYER M3 ;
        RECT  30.204 0 30.222 0.037 ;
    END
  END a[364]
  PIN a[365]
    DIRECTION INPUT ;
    USE SIGNAL ;
    PORT
      LAYER M3 ;
        RECT  30.276 0 30.294 0.037 ;
    END
  END a[365]
  PIN a[366]
    DIRECTION INPUT ;
    USE SIGNAL ;
    PORT
      LAYER M3 ;
        RECT  30.348 0 30.366 0.037 ;
    END
  END a[366]
  PIN a[367]
    DIRECTION INPUT ;
    USE SIGNAL ;
    PORT
      LAYER M3 ;
        RECT  30.42 0 30.438 0.037 ;
    END
  END a[367]
  PIN a[368]
    DIRECTION INPUT ;
    USE SIGNAL ;
    PORT
      LAYER M3 ;
        RECT  30.492 0 30.51 0.037 ;
    END
  END a[368]
  PIN a[369]
    DIRECTION INPUT ;
    USE SIGNAL ;
    PORT
      LAYER M3 ;
        RECT  30.564 0 30.582 0.037 ;
    END
  END a[369]
  PIN a[36]
    DIRECTION INPUT ;
    USE SIGNAL ;
    PORT
      LAYER M5 ;
        RECT  26.448 0 26.472 0.084 ;
    END
  END a[36]
  PIN a[370]
    DIRECTION INPUT ;
    USE SIGNAL ;
    PORT
      LAYER M3 ;
        RECT  30.636 0 30.654 0.037 ;
    END
  END a[370]
  PIN a[371]
    DIRECTION INPUT ;
    USE SIGNAL ;
    PORT
      LAYER M3 ;
        RECT  30.708 0 30.726 0.037 ;
    END
  END a[371]
  PIN a[372]
    DIRECTION INPUT ;
    USE SIGNAL ;
    PORT
      LAYER M3 ;
        RECT  30.78 0 30.798 0.037 ;
    END
  END a[372]
  PIN a[373]
    DIRECTION INPUT ;
    USE SIGNAL ;
    PORT
      LAYER M3 ;
        RECT  30.852 0 30.87 0.037 ;
    END
  END a[373]
  PIN a[374]
    DIRECTION INPUT ;
    USE SIGNAL ;
    PORT
      LAYER M3 ;
        RECT  30.924 0 30.942 0.037 ;
    END
  END a[374]
  PIN a[375]
    DIRECTION INPUT ;
    USE SIGNAL ;
    PORT
      LAYER M3 ;
        RECT  30.996 0 31.014 0.037 ;
    END
  END a[375]
  PIN a[376]
    DIRECTION INPUT ;
    USE SIGNAL ;
    PORT
      LAYER M3 ;
        RECT  31.068 0 31.086 0.037 ;
    END
  END a[376]
  PIN a[377]
    DIRECTION INPUT ;
    USE SIGNAL ;
    PORT
      LAYER M3 ;
        RECT  31.14 0 31.158 0.037 ;
    END
  END a[377]
  PIN a[378]
    DIRECTION INPUT ;
    USE SIGNAL ;
    PORT
      LAYER M3 ;
        RECT  31.212 0 31.23 0.037 ;
    END
  END a[378]
  PIN a[379]
    DIRECTION INPUT ;
    USE SIGNAL ;
    PORT
      LAYER M3 ;
        RECT  31.284 0 31.302 0.037 ;
    END
  END a[379]
  PIN a[37]
    DIRECTION INPUT ;
    USE SIGNAL ;
    PORT
      LAYER M5 ;
        RECT  26.544 0 26.568 0.084 ;
    END
  END a[37]
  PIN a[380]
    DIRECTION INPUT ;
    USE SIGNAL ;
    PORT
      LAYER M3 ;
        RECT  31.356 0 31.374 0.037 ;
    END
  END a[380]
  PIN a[381]
    DIRECTION INPUT ;
    USE SIGNAL ;
    PORT
      LAYER M3 ;
        RECT  31.428 0 31.446 0.037 ;
    END
  END a[381]
  PIN a[382]
    DIRECTION INPUT ;
    USE SIGNAL ;
    PORT
      LAYER M3 ;
        RECT  31.5 0 31.518 0.037 ;
    END
  END a[382]
  PIN a[383]
    DIRECTION INPUT ;
    USE SIGNAL ;
    PORT
      LAYER M3 ;
        RECT  31.572 0 31.59 0.037 ;
    END
  END a[383]
  PIN a[384]
    DIRECTION INPUT ;
    USE SIGNAL ;
    PORT
      LAYER M3 ;
        RECT  21.852 0 21.87 0.037 ;
    END
  END a[384]
  PIN a[385]
    DIRECTION INPUT ;
    USE SIGNAL ;
    PORT
      LAYER M3 ;
        RECT  21.924 0 21.942 0.037 ;
    END
  END a[385]
  PIN a[386]
    DIRECTION INPUT ;
    USE SIGNAL ;
    PORT
      LAYER M3 ;
        RECT  21.996 0 22.014 0.037 ;
    END
  END a[386]
  PIN a[387]
    DIRECTION INPUT ;
    USE SIGNAL ;
    PORT
      LAYER M3 ;
        RECT  22.068 0 22.086 0.037 ;
    END
  END a[387]
  PIN a[388]
    DIRECTION INPUT ;
    USE SIGNAL ;
    PORT
      LAYER M3 ;
        RECT  22.14 0 22.158 0.037 ;
    END
  END a[388]
  PIN a[389]
    DIRECTION INPUT ;
    USE SIGNAL ;
    PORT
      LAYER M3 ;
        RECT  22.212 0 22.23 0.037 ;
    END
  END a[389]
  PIN a[38]
    DIRECTION INPUT ;
    USE SIGNAL ;
    PORT
      LAYER M5 ;
        RECT  26.64 0 26.664 0.084 ;
    END
  END a[38]
  PIN a[390]
    DIRECTION INPUT ;
    USE SIGNAL ;
    PORT
      LAYER M3 ;
        RECT  22.284 0 22.302 0.037 ;
    END
  END a[390]
  PIN a[391]
    DIRECTION INPUT ;
    USE SIGNAL ;
    PORT
      LAYER M3 ;
        RECT  22.356 0 22.374 0.037 ;
    END
  END a[391]
  PIN a[392]
    DIRECTION INPUT ;
    USE SIGNAL ;
    PORT
      LAYER M3 ;
        RECT  22.428 0 22.446 0.037 ;
    END
  END a[392]
  PIN a[393]
    DIRECTION INPUT ;
    USE SIGNAL ;
    PORT
      LAYER M3 ;
        RECT  22.5 0 22.518 0.037 ;
    END
  END a[393]
  PIN a[394]
    DIRECTION INPUT ;
    USE SIGNAL ;
    PORT
      LAYER M3 ;
        RECT  22.572 0 22.59 0.037 ;
    END
  END a[394]
  PIN a[395]
    DIRECTION INPUT ;
    USE SIGNAL ;
    PORT
      LAYER M3 ;
        RECT  22.644 0 22.662 0.037 ;
    END
  END a[395]
  PIN a[396]
    DIRECTION INPUT ;
    USE SIGNAL ;
    PORT
      LAYER M3 ;
        RECT  22.716 0 22.734 0.037 ;
    END
  END a[396]
  PIN a[397]
    DIRECTION INPUT ;
    USE SIGNAL ;
    PORT
      LAYER M3 ;
        RECT  22.788 0 22.806 0.037 ;
    END
  END a[397]
  PIN a[398]
    DIRECTION INPUT ;
    USE SIGNAL ;
    PORT
      LAYER M3 ;
        RECT  22.86 0 22.878 0.037 ;
    END
  END a[398]
  PIN a[399]
    DIRECTION INPUT ;
    USE SIGNAL ;
    PORT
      LAYER M3 ;
        RECT  22.932 0 22.95 0.037 ;
    END
  END a[399]
  PIN a[39]
    DIRECTION INPUT ;
    USE SIGNAL ;
    PORT
      LAYER M5 ;
        RECT  26.736 0 26.76 0.084 ;
    END
  END a[39]
  PIN a[3]
    DIRECTION INPUT ;
    USE SIGNAL ;
    PORT
      LAYER M5 ;
        RECT  35.568 0 35.592 0.084 ;
    END
  END a[3]
  PIN a[400]
    DIRECTION INPUT ;
    USE SIGNAL ;
    PORT
      LAYER M3 ;
        RECT  23.004 0 23.022 0.037 ;
    END
  END a[400]
  PIN a[401]
    DIRECTION INPUT ;
    USE SIGNAL ;
    PORT
      LAYER M3 ;
        RECT  23.076 0 23.094 0.037 ;
    END
  END a[401]
  PIN a[402]
    DIRECTION INPUT ;
    USE SIGNAL ;
    PORT
      LAYER M3 ;
        RECT  23.148 0 23.166 0.037 ;
    END
  END a[402]
  PIN a[403]
    DIRECTION INPUT ;
    USE SIGNAL ;
    PORT
      LAYER M3 ;
        RECT  23.22 0 23.238 0.037 ;
    END
  END a[403]
  PIN a[404]
    DIRECTION INPUT ;
    USE SIGNAL ;
    PORT
      LAYER M3 ;
        RECT  23.292 0 23.31 0.037 ;
    END
  END a[404]
  PIN a[405]
    DIRECTION INPUT ;
    USE SIGNAL ;
    PORT
      LAYER M3 ;
        RECT  23.364 0 23.382 0.037 ;
    END
  END a[405]
  PIN a[406]
    DIRECTION INPUT ;
    USE SIGNAL ;
    PORT
      LAYER M3 ;
        RECT  23.436 0 23.454 0.037 ;
    END
  END a[406]
  PIN a[407]
    DIRECTION INPUT ;
    USE SIGNAL ;
    PORT
      LAYER M3 ;
        RECT  23.508 0 23.526 0.037 ;
    END
  END a[407]
  PIN a[408]
    DIRECTION INPUT ;
    USE SIGNAL ;
    PORT
      LAYER M3 ;
        RECT  23.58 0 23.598 0.037 ;
    END
  END a[408]
  PIN a[409]
    DIRECTION INPUT ;
    USE SIGNAL ;
    PORT
      LAYER M3 ;
        RECT  23.652 0 23.67 0.037 ;
    END
  END a[409]
  PIN a[40]
    DIRECTION INPUT ;
    USE SIGNAL ;
    PORT
      LAYER M5 ;
        RECT  26.832 0 26.856 0.084 ;
    END
  END a[40]
  PIN a[410]
    DIRECTION INPUT ;
    USE SIGNAL ;
    PORT
      LAYER M3 ;
        RECT  23.724 0 23.742 0.037 ;
    END
  END a[410]
  PIN a[411]
    DIRECTION INPUT ;
    USE SIGNAL ;
    PORT
      LAYER M3 ;
        RECT  23.796 0 23.814 0.037 ;
    END
  END a[411]
  PIN a[412]
    DIRECTION INPUT ;
    USE SIGNAL ;
    PORT
      LAYER M3 ;
        RECT  23.868 0 23.886 0.037 ;
    END
  END a[412]
  PIN a[413]
    DIRECTION INPUT ;
    USE SIGNAL ;
    PORT
      LAYER M3 ;
        RECT  23.94 0 23.958 0.037 ;
    END
  END a[413]
  PIN a[414]
    DIRECTION INPUT ;
    USE SIGNAL ;
    PORT
      LAYER M3 ;
        RECT  24.012 0 24.03 0.037 ;
    END
  END a[414]
  PIN a[415]
    DIRECTION INPUT ;
    USE SIGNAL ;
    PORT
      LAYER M3 ;
        RECT  24.084 0 24.102 0.037 ;
    END
  END a[415]
  PIN a[416]
    DIRECTION INPUT ;
    USE SIGNAL ;
    PORT
      LAYER M3 ;
        RECT  19.548 0 19.566 0.037 ;
    END
  END a[416]
  PIN a[417]
    DIRECTION INPUT ;
    USE SIGNAL ;
    PORT
      LAYER M3 ;
        RECT  19.62 0 19.638 0.037 ;
    END
  END a[417]
  PIN a[418]
    DIRECTION INPUT ;
    USE SIGNAL ;
    PORT
      LAYER M3 ;
        RECT  19.692 0 19.71 0.037 ;
    END
  END a[418]
  PIN a[419]
    DIRECTION INPUT ;
    USE SIGNAL ;
    PORT
      LAYER M3 ;
        RECT  19.764 0 19.782 0.037 ;
    END
  END a[419]
  PIN a[41]
    DIRECTION INPUT ;
    USE SIGNAL ;
    PORT
      LAYER M5 ;
        RECT  26.928 0 26.952 0.084 ;
    END
  END a[41]
  PIN a[420]
    DIRECTION INPUT ;
    USE SIGNAL ;
    PORT
      LAYER M3 ;
        RECT  19.836 0 19.854 0.037 ;
    END
  END a[420]
  PIN a[421]
    DIRECTION INPUT ;
    USE SIGNAL ;
    PORT
      LAYER M3 ;
        RECT  19.908 0 19.926 0.037 ;
    END
  END a[421]
  PIN a[422]
    DIRECTION INPUT ;
    USE SIGNAL ;
    PORT
      LAYER M3 ;
        RECT  19.98 0 19.998 0.037 ;
    END
  END a[422]
  PIN a[423]
    DIRECTION INPUT ;
    USE SIGNAL ;
    PORT
      LAYER M3 ;
        RECT  20.052 0 20.07 0.037 ;
    END
  END a[423]
  PIN a[424]
    DIRECTION INPUT ;
    USE SIGNAL ;
    PORT
      LAYER M3 ;
        RECT  20.124 0 20.142 0.037 ;
    END
  END a[424]
  PIN a[425]
    DIRECTION INPUT ;
    USE SIGNAL ;
    PORT
      LAYER M3 ;
        RECT  20.196 0 20.214 0.037 ;
    END
  END a[425]
  PIN a[426]
    DIRECTION INPUT ;
    USE SIGNAL ;
    PORT
      LAYER M3 ;
        RECT  20.268 0 20.286 0.037 ;
    END
  END a[426]
  PIN a[427]
    DIRECTION INPUT ;
    USE SIGNAL ;
    PORT
      LAYER M3 ;
        RECT  20.34 0 20.358 0.037 ;
    END
  END a[427]
  PIN a[428]
    DIRECTION INPUT ;
    USE SIGNAL ;
    PORT
      LAYER M3 ;
        RECT  20.412 0 20.43 0.037 ;
    END
  END a[428]
  PIN a[429]
    DIRECTION INPUT ;
    USE SIGNAL ;
    PORT
      LAYER M3 ;
        RECT  20.484 0 20.502 0.037 ;
    END
  END a[429]
  PIN a[42]
    DIRECTION INPUT ;
    USE SIGNAL ;
    PORT
      LAYER M5 ;
        RECT  27.024 0 27.048 0.084 ;
    END
  END a[42]
  PIN a[430]
    DIRECTION INPUT ;
    USE SIGNAL ;
    PORT
      LAYER M3 ;
        RECT  20.556 0 20.574 0.037 ;
    END
  END a[430]
  PIN a[431]
    DIRECTION INPUT ;
    USE SIGNAL ;
    PORT
      LAYER M3 ;
        RECT  20.628 0 20.646 0.037 ;
    END
  END a[431]
  PIN a[432]
    DIRECTION INPUT ;
    USE SIGNAL ;
    PORT
      LAYER M3 ;
        RECT  20.7 0 20.718 0.037 ;
    END
  END a[432]
  PIN a[433]
    DIRECTION INPUT ;
    USE SIGNAL ;
    PORT
      LAYER M3 ;
        RECT  20.772 0 20.79 0.037 ;
    END
  END a[433]
  PIN a[434]
    DIRECTION INPUT ;
    USE SIGNAL ;
    PORT
      LAYER M3 ;
        RECT  20.844 0 20.862 0.037 ;
    END
  END a[434]
  PIN a[435]
    DIRECTION INPUT ;
    USE SIGNAL ;
    PORT
      LAYER M3 ;
        RECT  20.916 0 20.934 0.037 ;
    END
  END a[435]
  PIN a[436]
    DIRECTION INPUT ;
    USE SIGNAL ;
    PORT
      LAYER M3 ;
        RECT  20.988 0 21.006 0.037 ;
    END
  END a[436]
  PIN a[437]
    DIRECTION INPUT ;
    USE SIGNAL ;
    PORT
      LAYER M3 ;
        RECT  21.06 0 21.078 0.037 ;
    END
  END a[437]
  PIN a[438]
    DIRECTION INPUT ;
    USE SIGNAL ;
    PORT
      LAYER M3 ;
        RECT  21.132 0 21.15 0.037 ;
    END
  END a[438]
  PIN a[439]
    DIRECTION INPUT ;
    USE SIGNAL ;
    PORT
      LAYER M3 ;
        RECT  21.204 0 21.222 0.037 ;
    END
  END a[439]
  PIN a[43]
    DIRECTION INPUT ;
    USE SIGNAL ;
    PORT
      LAYER M5 ;
        RECT  27.12 0 27.144 0.084 ;
    END
  END a[43]
  PIN a[440]
    DIRECTION INPUT ;
    USE SIGNAL ;
    PORT
      LAYER M3 ;
        RECT  21.276 0 21.294 0.037 ;
    END
  END a[440]
  PIN a[441]
    DIRECTION INPUT ;
    USE SIGNAL ;
    PORT
      LAYER M3 ;
        RECT  21.348 0 21.366 0.037 ;
    END
  END a[441]
  PIN a[442]
    DIRECTION INPUT ;
    USE SIGNAL ;
    PORT
      LAYER M3 ;
        RECT  21.42 0 21.438 0.037 ;
    END
  END a[442]
  PIN a[443]
    DIRECTION INPUT ;
    USE SIGNAL ;
    PORT
      LAYER M3 ;
        RECT  21.492 0 21.51 0.037 ;
    END
  END a[443]
  PIN a[444]
    DIRECTION INPUT ;
    USE SIGNAL ;
    PORT
      LAYER M3 ;
        RECT  21.564 0 21.582 0.037 ;
    END
  END a[444]
  PIN a[445]
    DIRECTION INPUT ;
    USE SIGNAL ;
    PORT
      LAYER M3 ;
        RECT  21.636 0 21.654 0.037 ;
    END
  END a[445]
  PIN a[446]
    DIRECTION INPUT ;
    USE SIGNAL ;
    PORT
      LAYER M3 ;
        RECT  21.708 0 21.726 0.037 ;
    END
  END a[446]
  PIN a[447]
    DIRECTION INPUT ;
    USE SIGNAL ;
    PORT
      LAYER M3 ;
        RECT  21.78 0 21.798 0.037 ;
    END
  END a[447]
  PIN a[448]
    DIRECTION INPUT ;
    USE SIGNAL ;
    PORT
      LAYER M3 ;
        RECT  17.244 0 17.262 0.037 ;
    END
  END a[448]
  PIN a[449]
    DIRECTION INPUT ;
    USE SIGNAL ;
    PORT
      LAYER M3 ;
        RECT  17.316 0 17.334 0.037 ;
    END
  END a[449]
  PIN a[44]
    DIRECTION INPUT ;
    USE SIGNAL ;
    PORT
      LAYER M5 ;
        RECT  27.216 0 27.24 0.084 ;
    END
  END a[44]
  PIN a[450]
    DIRECTION INPUT ;
    USE SIGNAL ;
    PORT
      LAYER M3 ;
        RECT  17.388 0 17.406 0.037 ;
    END
  END a[450]
  PIN a[451]
    DIRECTION INPUT ;
    USE SIGNAL ;
    PORT
      LAYER M3 ;
        RECT  17.46 0 17.478 0.037 ;
    END
  END a[451]
  PIN a[452]
    DIRECTION INPUT ;
    USE SIGNAL ;
    PORT
      LAYER M3 ;
        RECT  17.532 0 17.55 0.037 ;
    END
  END a[452]
  PIN a[453]
    DIRECTION INPUT ;
    USE SIGNAL ;
    PORT
      LAYER M3 ;
        RECT  17.604 0 17.622 0.037 ;
    END
  END a[453]
  PIN a[454]
    DIRECTION INPUT ;
    USE SIGNAL ;
    PORT
      LAYER M3 ;
        RECT  17.676 0 17.694 0.037 ;
    END
  END a[454]
  PIN a[455]
    DIRECTION INPUT ;
    USE SIGNAL ;
    PORT
      LAYER M3 ;
        RECT  17.748 0 17.766 0.037 ;
    END
  END a[455]
  PIN a[456]
    DIRECTION INPUT ;
    USE SIGNAL ;
    PORT
      LAYER M3 ;
        RECT  17.82 0 17.838 0.037 ;
    END
  END a[456]
  PIN a[457]
    DIRECTION INPUT ;
    USE SIGNAL ;
    PORT
      LAYER M3 ;
        RECT  17.892 0 17.91 0.037 ;
    END
  END a[457]
  PIN a[458]
    DIRECTION INPUT ;
    USE SIGNAL ;
    PORT
      LAYER M3 ;
        RECT  17.964 0 17.982 0.037 ;
    END
  END a[458]
  PIN a[459]
    DIRECTION INPUT ;
    USE SIGNAL ;
    PORT
      LAYER M3 ;
        RECT  18.036 0 18.054 0.037 ;
    END
  END a[459]
  PIN a[45]
    DIRECTION INPUT ;
    USE SIGNAL ;
    PORT
      LAYER M5 ;
        RECT  27.312 0 27.336 0.084 ;
    END
  END a[45]
  PIN a[460]
    DIRECTION INPUT ;
    USE SIGNAL ;
    PORT
      LAYER M3 ;
        RECT  18.108 0 18.126 0.037 ;
    END
  END a[460]
  PIN a[461]
    DIRECTION INPUT ;
    USE SIGNAL ;
    PORT
      LAYER M3 ;
        RECT  18.18 0 18.198 0.037 ;
    END
  END a[461]
  PIN a[462]
    DIRECTION INPUT ;
    USE SIGNAL ;
    PORT
      LAYER M3 ;
        RECT  18.252 0 18.27 0.037 ;
    END
  END a[462]
  PIN a[463]
    DIRECTION INPUT ;
    USE SIGNAL ;
    PORT
      LAYER M3 ;
        RECT  18.324 0 18.342 0.037 ;
    END
  END a[463]
  PIN a[464]
    DIRECTION INPUT ;
    USE SIGNAL ;
    PORT
      LAYER M3 ;
        RECT  18.396 0 18.414 0.037 ;
    END
  END a[464]
  PIN a[465]
    DIRECTION INPUT ;
    USE SIGNAL ;
    PORT
      LAYER M3 ;
        RECT  18.468 0 18.486 0.037 ;
    END
  END a[465]
  PIN a[466]
    DIRECTION INPUT ;
    USE SIGNAL ;
    PORT
      LAYER M3 ;
        RECT  18.54 0 18.558 0.037 ;
    END
  END a[466]
  PIN a[467]
    DIRECTION INPUT ;
    USE SIGNAL ;
    PORT
      LAYER M3 ;
        RECT  18.612 0 18.63 0.037 ;
    END
  END a[467]
  PIN a[468]
    DIRECTION INPUT ;
    USE SIGNAL ;
    PORT
      LAYER M3 ;
        RECT  18.684 0 18.702 0.037 ;
    END
  END a[468]
  PIN a[469]
    DIRECTION INPUT ;
    USE SIGNAL ;
    PORT
      LAYER M3 ;
        RECT  18.756 0 18.774 0.037 ;
    END
  END a[469]
  PIN a[46]
    DIRECTION INPUT ;
    USE SIGNAL ;
    PORT
      LAYER M5 ;
        RECT  27.408 0 27.432 0.084 ;
    END
  END a[46]
  PIN a[470]
    DIRECTION INPUT ;
    USE SIGNAL ;
    PORT
      LAYER M3 ;
        RECT  18.828 0 18.846 0.037 ;
    END
  END a[470]
  PIN a[471]
    DIRECTION INPUT ;
    USE SIGNAL ;
    PORT
      LAYER M3 ;
        RECT  18.9 0 18.918 0.037 ;
    END
  END a[471]
  PIN a[472]
    DIRECTION INPUT ;
    USE SIGNAL ;
    PORT
      LAYER M3 ;
        RECT  18.972 0 18.99 0.037 ;
    END
  END a[472]
  PIN a[473]
    DIRECTION INPUT ;
    USE SIGNAL ;
    PORT
      LAYER M3 ;
        RECT  19.044 0 19.062 0.037 ;
    END
  END a[473]
  PIN a[474]
    DIRECTION INPUT ;
    USE SIGNAL ;
    PORT
      LAYER M3 ;
        RECT  19.116 0 19.134 0.037 ;
    END
  END a[474]
  PIN a[475]
    DIRECTION INPUT ;
    USE SIGNAL ;
    PORT
      LAYER M3 ;
        RECT  19.188 0 19.206 0.037 ;
    END
  END a[475]
  PIN a[476]
    DIRECTION INPUT ;
    USE SIGNAL ;
    PORT
      LAYER M3 ;
        RECT  19.26 0 19.278 0.037 ;
    END
  END a[476]
  PIN a[477]
    DIRECTION INPUT ;
    USE SIGNAL ;
    PORT
      LAYER M3 ;
        RECT  19.332 0 19.35 0.037 ;
    END
  END a[477]
  PIN a[478]
    DIRECTION INPUT ;
    USE SIGNAL ;
    PORT
      LAYER M3 ;
        RECT  19.404 0 19.422 0.037 ;
    END
  END a[478]
  PIN a[479]
    DIRECTION INPUT ;
    USE SIGNAL ;
    PORT
      LAYER M3 ;
        RECT  19.476 0 19.494 0.037 ;
    END
  END a[479]
  PIN a[47]
    DIRECTION INPUT ;
    USE SIGNAL ;
    PORT
      LAYER M5 ;
        RECT  27.504 0 27.528 0.084 ;
    END
  END a[47]
  PIN a[480]
    DIRECTION INPUT ;
    USE SIGNAL ;
    PORT
      LAYER M3 ;
        RECT  26.46 0 26.478 0.037 ;
    END
  END a[480]
  PIN a[481]
    DIRECTION INPUT ;
    USE SIGNAL ;
    PORT
      LAYER M3 ;
        RECT  26.532 0 26.55 0.037 ;
    END
  END a[481]
  PIN a[482]
    DIRECTION INPUT ;
    USE SIGNAL ;
    PORT
      LAYER M3 ;
        RECT  26.604 0 26.622 0.037 ;
    END
  END a[482]
  PIN a[483]
    DIRECTION INPUT ;
    USE SIGNAL ;
    PORT
      LAYER M3 ;
        RECT  26.676 0 26.694 0.037 ;
    END
  END a[483]
  PIN a[484]
    DIRECTION INPUT ;
    USE SIGNAL ;
    PORT
      LAYER M3 ;
        RECT  26.748 0 26.766 0.037 ;
    END
  END a[484]
  PIN a[485]
    DIRECTION INPUT ;
    USE SIGNAL ;
    PORT
      LAYER M3 ;
        RECT  26.82 0 26.838 0.037 ;
    END
  END a[485]
  PIN a[486]
    DIRECTION INPUT ;
    USE SIGNAL ;
    PORT
      LAYER M3 ;
        RECT  26.892 0 26.91 0.037 ;
    END
  END a[486]
  PIN a[487]
    DIRECTION INPUT ;
    USE SIGNAL ;
    PORT
      LAYER M3 ;
        RECT  26.964 0 26.982 0.037 ;
    END
  END a[487]
  PIN a[488]
    DIRECTION INPUT ;
    USE SIGNAL ;
    PORT
      LAYER M3 ;
        RECT  27.036 0 27.054 0.037 ;
    END
  END a[488]
  PIN a[489]
    DIRECTION INPUT ;
    USE SIGNAL ;
    PORT
      LAYER M3 ;
        RECT  27.108 0 27.126 0.037 ;
    END
  END a[489]
  PIN a[48]
    DIRECTION INPUT ;
    USE SIGNAL ;
    PORT
      LAYER M5 ;
        RECT  27.6 0 27.624 0.084 ;
    END
  END a[48]
  PIN a[490]
    DIRECTION INPUT ;
    USE SIGNAL ;
    PORT
      LAYER M3 ;
        RECT  27.18 0 27.198 0.037 ;
    END
  END a[490]
  PIN a[491]
    DIRECTION INPUT ;
    USE SIGNAL ;
    PORT
      LAYER M3 ;
        RECT  27.252 0 27.27 0.037 ;
    END
  END a[491]
  PIN a[492]
    DIRECTION INPUT ;
    USE SIGNAL ;
    PORT
      LAYER M3 ;
        RECT  27.324 0 27.342 0.037 ;
    END
  END a[492]
  PIN a[493]
    DIRECTION INPUT ;
    USE SIGNAL ;
    PORT
      LAYER M3 ;
        RECT  27.396 0 27.414 0.037 ;
    END
  END a[493]
  PIN a[494]
    DIRECTION INPUT ;
    USE SIGNAL ;
    PORT
      LAYER M3 ;
        RECT  27.468 0 27.486 0.037 ;
    END
  END a[494]
  PIN a[495]
    DIRECTION INPUT ;
    USE SIGNAL ;
    PORT
      LAYER M3 ;
        RECT  27.54 0 27.558 0.037 ;
    END
  END a[495]
  PIN a[496]
    DIRECTION INPUT ;
    USE SIGNAL ;
    PORT
      LAYER M3 ;
        RECT  27.612 0 27.63 0.037 ;
    END
  END a[496]
  PIN a[497]
    DIRECTION INPUT ;
    USE SIGNAL ;
    PORT
      LAYER M3 ;
        RECT  27.684 0 27.702 0.037 ;
    END
  END a[497]
  PIN a[498]
    DIRECTION INPUT ;
    USE SIGNAL ;
    PORT
      LAYER M3 ;
        RECT  27.756 0 27.774 0.037 ;
    END
  END a[498]
  PIN a[499]
    DIRECTION INPUT ;
    USE SIGNAL ;
    PORT
      LAYER M3 ;
        RECT  27.828 0 27.846 0.037 ;
    END
  END a[499]
  PIN a[49]
    DIRECTION INPUT ;
    USE SIGNAL ;
    PORT
      LAYER M5 ;
        RECT  27.696 0 27.72 0.084 ;
    END
  END a[49]
  PIN a[4]
    DIRECTION INPUT ;
    USE SIGNAL ;
    PORT
      LAYER M5 ;
        RECT  35.664 0 35.688 0.084 ;
    END
  END a[4]
  PIN a[500]
    DIRECTION INPUT ;
    USE SIGNAL ;
    PORT
      LAYER M3 ;
        RECT  27.9 0 27.918 0.037 ;
    END
  END a[500]
  PIN a[501]
    DIRECTION INPUT ;
    USE SIGNAL ;
    PORT
      LAYER M3 ;
        RECT  27.972 0 27.99 0.037 ;
    END
  END a[501]
  PIN a[502]
    DIRECTION INPUT ;
    USE SIGNAL ;
    PORT
      LAYER M3 ;
        RECT  28.044 0 28.062 0.037 ;
    END
  END a[502]
  PIN a[503]
    DIRECTION INPUT ;
    USE SIGNAL ;
    PORT
      LAYER M3 ;
        RECT  28.116 0 28.134 0.037 ;
    END
  END a[503]
  PIN a[504]
    DIRECTION INPUT ;
    USE SIGNAL ;
    PORT
      LAYER M3 ;
        RECT  28.188 0 28.206 0.037 ;
    END
  END a[504]
  PIN a[505]
    DIRECTION INPUT ;
    USE SIGNAL ;
    PORT
      LAYER M3 ;
        RECT  28.26 0 28.278 0.037 ;
    END
  END a[505]
  PIN a[506]
    DIRECTION INPUT ;
    USE SIGNAL ;
    PORT
      LAYER M3 ;
        RECT  28.332 0 28.35 0.037 ;
    END
  END a[506]
  PIN a[507]
    DIRECTION INPUT ;
    USE SIGNAL ;
    PORT
      LAYER M3 ;
        RECT  28.404 0 28.422 0.037 ;
    END
  END a[507]
  PIN a[508]
    DIRECTION INPUT ;
    USE SIGNAL ;
    PORT
      LAYER M3 ;
        RECT  28.476 0 28.494 0.037 ;
    END
  END a[508]
  PIN a[509]
    DIRECTION INPUT ;
    USE SIGNAL ;
    PORT
      LAYER M3 ;
        RECT  28.548 0 28.566 0.037 ;
    END
  END a[509]
  PIN a[50]
    DIRECTION INPUT ;
    USE SIGNAL ;
    PORT
      LAYER M5 ;
        RECT  27.792 0 27.816 0.084 ;
    END
  END a[50]
  PIN a[510]
    DIRECTION INPUT ;
    USE SIGNAL ;
    PORT
      LAYER M3 ;
        RECT  28.62 0 28.638 0.037 ;
    END
  END a[510]
  PIN a[511]
    DIRECTION INPUT ;
    USE SIGNAL ;
    PORT
      LAYER M3 ;
        RECT  28.692 0 28.71 0.037 ;
    END
  END a[511]
  PIN a[512]
    DIRECTION INPUT ;
    USE SIGNAL ;
    PORT
      LAYER M3 ;
        RECT  24.156 0 24.174 0.037 ;
    END
  END a[512]
  PIN a[513]
    DIRECTION INPUT ;
    USE SIGNAL ;
    PORT
      LAYER M3 ;
        RECT  24.228 0 24.246 0.037 ;
    END
  END a[513]
  PIN a[514]
    DIRECTION INPUT ;
    USE SIGNAL ;
    PORT
      LAYER M3 ;
        RECT  24.3 0 24.318 0.037 ;
    END
  END a[514]
  PIN a[515]
    DIRECTION INPUT ;
    USE SIGNAL ;
    PORT
      LAYER M3 ;
        RECT  24.372 0 24.39 0.037 ;
    END
  END a[515]
  PIN a[516]
    DIRECTION INPUT ;
    USE SIGNAL ;
    PORT
      LAYER M3 ;
        RECT  24.444 0 24.462 0.037 ;
    END
  END a[516]
  PIN a[517]
    DIRECTION INPUT ;
    USE SIGNAL ;
    PORT
      LAYER M3 ;
        RECT  24.516 0 24.534 0.037 ;
    END
  END a[517]
  PIN a[518]
    DIRECTION INPUT ;
    USE SIGNAL ;
    PORT
      LAYER M3 ;
        RECT  24.588 0 24.606 0.037 ;
    END
  END a[518]
  PIN a[519]
    DIRECTION INPUT ;
    USE SIGNAL ;
    PORT
      LAYER M3 ;
        RECT  24.66 0 24.678 0.037 ;
    END
  END a[519]
  PIN a[51]
    DIRECTION INPUT ;
    USE SIGNAL ;
    PORT
      LAYER M5 ;
        RECT  27.888 0 27.912 0.084 ;
    END
  END a[51]
  PIN a[520]
    DIRECTION INPUT ;
    USE SIGNAL ;
    PORT
      LAYER M3 ;
        RECT  24.732 0 24.75 0.037 ;
    END
  END a[520]
  PIN a[521]
    DIRECTION INPUT ;
    USE SIGNAL ;
    PORT
      LAYER M3 ;
        RECT  24.804 0 24.822 0.037 ;
    END
  END a[521]
  PIN a[522]
    DIRECTION INPUT ;
    USE SIGNAL ;
    PORT
      LAYER M3 ;
        RECT  24.876 0 24.894 0.037 ;
    END
  END a[522]
  PIN a[523]
    DIRECTION INPUT ;
    USE SIGNAL ;
    PORT
      LAYER M3 ;
        RECT  24.948 0 24.966 0.037 ;
    END
  END a[523]
  PIN a[524]
    DIRECTION INPUT ;
    USE SIGNAL ;
    PORT
      LAYER M3 ;
        RECT  25.02 0 25.038 0.037 ;
    END
  END a[524]
  PIN a[525]
    DIRECTION INPUT ;
    USE SIGNAL ;
    PORT
      LAYER M3 ;
        RECT  25.092 0 25.11 0.037 ;
    END
  END a[525]
  PIN a[526]
    DIRECTION INPUT ;
    USE SIGNAL ;
    PORT
      LAYER M3 ;
        RECT  25.164 0 25.182 0.037 ;
    END
  END a[526]
  PIN a[527]
    DIRECTION INPUT ;
    USE SIGNAL ;
    PORT
      LAYER M3 ;
        RECT  25.236 0 25.254 0.037 ;
    END
  END a[527]
  PIN a[528]
    DIRECTION INPUT ;
    USE SIGNAL ;
    PORT
      LAYER M3 ;
        RECT  25.308 0 25.326 0.037 ;
    END
  END a[528]
  PIN a[529]
    DIRECTION INPUT ;
    USE SIGNAL ;
    PORT
      LAYER M3 ;
        RECT  25.38 0 25.398 0.037 ;
    END
  END a[529]
  PIN a[52]
    DIRECTION INPUT ;
    USE SIGNAL ;
    PORT
      LAYER M5 ;
        RECT  27.984 0 28.008 0.084 ;
    END
  END a[52]
  PIN a[530]
    DIRECTION INPUT ;
    USE SIGNAL ;
    PORT
      LAYER M3 ;
        RECT  25.452 0 25.47 0.037 ;
    END
  END a[530]
  PIN a[531]
    DIRECTION INPUT ;
    USE SIGNAL ;
    PORT
      LAYER M3 ;
        RECT  25.524 0 25.542 0.037 ;
    END
  END a[531]
  PIN a[532]
    DIRECTION INPUT ;
    USE SIGNAL ;
    PORT
      LAYER M3 ;
        RECT  25.596 0 25.614 0.037 ;
    END
  END a[532]
  PIN a[533]
    DIRECTION INPUT ;
    USE SIGNAL ;
    PORT
      LAYER M3 ;
        RECT  25.668 0 25.686 0.037 ;
    END
  END a[533]
  PIN a[534]
    DIRECTION INPUT ;
    USE SIGNAL ;
    PORT
      LAYER M3 ;
        RECT  25.74 0 25.758 0.037 ;
    END
  END a[534]
  PIN a[535]
    DIRECTION INPUT ;
    USE SIGNAL ;
    PORT
      LAYER M3 ;
        RECT  25.812 0 25.83 0.037 ;
    END
  END a[535]
  PIN a[536]
    DIRECTION INPUT ;
    USE SIGNAL ;
    PORT
      LAYER M3 ;
        RECT  25.884 0 25.902 0.037 ;
    END
  END a[536]
  PIN a[537]
    DIRECTION INPUT ;
    USE SIGNAL ;
    PORT
      LAYER M3 ;
        RECT  25.956 0 25.974 0.037 ;
    END
  END a[537]
  PIN a[538]
    DIRECTION INPUT ;
    USE SIGNAL ;
    PORT
      LAYER M3 ;
        RECT  26.028 0 26.046 0.037 ;
    END
  END a[538]
  PIN a[539]
    DIRECTION INPUT ;
    USE SIGNAL ;
    PORT
      LAYER M3 ;
        RECT  26.1 0 26.118 0.037 ;
    END
  END a[539]
  PIN a[53]
    DIRECTION INPUT ;
    USE SIGNAL ;
    PORT
      LAYER M5 ;
        RECT  28.08 0 28.104 0.084 ;
    END
  END a[53]
  PIN a[540]
    DIRECTION INPUT ;
    USE SIGNAL ;
    PORT
      LAYER M3 ;
        RECT  26.172 0 26.19 0.037 ;
    END
  END a[540]
  PIN a[541]
    DIRECTION INPUT ;
    USE SIGNAL ;
    PORT
      LAYER M3 ;
        RECT  26.244 0 26.262 0.037 ;
    END
  END a[541]
  PIN a[542]
    DIRECTION INPUT ;
    USE SIGNAL ;
    PORT
      LAYER M3 ;
        RECT  26.316 0 26.334 0.037 ;
    END
  END a[542]
  PIN a[543]
    DIRECTION INPUT ;
    USE SIGNAL ;
    PORT
      LAYER M3 ;
        RECT  26.388 0 26.406 0.037 ;
    END
  END a[543]
  PIN a[544]
    DIRECTION INPUT ;
    USE SIGNAL ;
    PORT
      LAYER M3 ;
        RECT  43.164 0 43.182 0.037 ;
    END
  END a[544]
  PIN a[545]
    DIRECTION INPUT ;
    USE SIGNAL ;
    PORT
      LAYER M3 ;
        RECT  43.236 0 43.254 0.037 ;
    END
  END a[545]
  PIN a[546]
    DIRECTION INPUT ;
    USE SIGNAL ;
    PORT
      LAYER M3 ;
        RECT  43.308 0 43.326 0.037 ;
    END
  END a[546]
  PIN a[547]
    DIRECTION INPUT ;
    USE SIGNAL ;
    PORT
      LAYER M3 ;
        RECT  43.38 0 43.398 0.037 ;
    END
  END a[547]
  PIN a[54]
    DIRECTION INPUT ;
    USE SIGNAL ;
    PORT
      LAYER M5 ;
        RECT  28.176 0 28.2 0.084 ;
    END
  END a[54]
  PIN a[55]
    DIRECTION INPUT ;
    USE SIGNAL ;
    PORT
      LAYER M5 ;
        RECT  28.272 0 28.296 0.084 ;
    END
  END a[55]
  PIN a[56]
    DIRECTION INPUT ;
    USE SIGNAL ;
    PORT
      LAYER M5 ;
        RECT  28.368 0 28.392 0.084 ;
    END
  END a[56]
  PIN a[57]
    DIRECTION INPUT ;
    USE SIGNAL ;
    PORT
      LAYER M5 ;
        RECT  28.464 0 28.488 0.084 ;
    END
  END a[57]
  PIN a[58]
    DIRECTION INPUT ;
    USE SIGNAL ;
    PORT
      LAYER M5 ;
        RECT  28.56 0 28.584 0.084 ;
    END
  END a[58]
  PIN a[59]
    DIRECTION INPUT ;
    USE SIGNAL ;
    PORT
      LAYER M5 ;
        RECT  28.656 0 28.68 0.084 ;
    END
  END a[59]
  PIN a[5]
    DIRECTION INPUT ;
    USE SIGNAL ;
    PORT
      LAYER M5 ;
        RECT  35.76 0 35.784 0.084 ;
    END
  END a[5]
  PIN a[60]
    DIRECTION INPUT ;
    USE SIGNAL ;
    PORT
      LAYER M5 ;
        RECT  28.752 0 28.776 0.084 ;
    END
  END a[60]
  PIN a[61]
    DIRECTION INPUT ;
    USE SIGNAL ;
    PORT
      LAYER M5 ;
        RECT  28.848 0 28.872 0.084 ;
    END
  END a[61]
  PIN a[62]
    DIRECTION INPUT ;
    USE SIGNAL ;
    PORT
      LAYER M5 ;
        RECT  28.944 0 28.968 0.084 ;
    END
  END a[62]
  PIN a[63]
    DIRECTION INPUT ;
    USE SIGNAL ;
    PORT
      LAYER M5 ;
        RECT  29.04 0 29.064 0.084 ;
    END
  END a[63]
  PIN a[64]
    DIRECTION INPUT ;
    USE SIGNAL ;
    PORT
      LAYER M3 ;
        RECT  40.86 0 40.878 0.037 ;
    END
  END a[64]
  PIN a[65]
    DIRECTION INPUT ;
    USE SIGNAL ;
    PORT
      LAYER M3 ;
        RECT  40.932 0 40.95 0.037 ;
    END
  END a[65]
  PIN a[66]
    DIRECTION INPUT ;
    USE SIGNAL ;
    PORT
      LAYER M3 ;
        RECT  41.004 0 41.022 0.037 ;
    END
  END a[66]
  PIN a[67]
    DIRECTION INPUT ;
    USE SIGNAL ;
    PORT
      LAYER M3 ;
        RECT  41.076 0 41.094 0.037 ;
    END
  END a[67]
  PIN a[68]
    DIRECTION INPUT ;
    USE SIGNAL ;
    PORT
      LAYER M3 ;
        RECT  41.148 0 41.166 0.037 ;
    END
  END a[68]
  PIN a[69]
    DIRECTION INPUT ;
    USE SIGNAL ;
    PORT
      LAYER M3 ;
        RECT  41.22 0 41.238 0.037 ;
    END
  END a[69]
  PIN a[6]
    DIRECTION INPUT ;
    USE SIGNAL ;
    PORT
      LAYER M5 ;
        RECT  35.856 0 35.88 0.084 ;
    END
  END a[6]
  PIN a[70]
    DIRECTION INPUT ;
    USE SIGNAL ;
    PORT
      LAYER M3 ;
        RECT  41.292 0 41.31 0.037 ;
    END
  END a[70]
  PIN a[71]
    DIRECTION INPUT ;
    USE SIGNAL ;
    PORT
      LAYER M3 ;
        RECT  41.364 0 41.382 0.037 ;
    END
  END a[71]
  PIN a[72]
    DIRECTION INPUT ;
    USE SIGNAL ;
    PORT
      LAYER M3 ;
        RECT  41.436 0 41.454 0.037 ;
    END
  END a[72]
  PIN a[73]
    DIRECTION INPUT ;
    USE SIGNAL ;
    PORT
      LAYER M3 ;
        RECT  41.508 0 41.526 0.037 ;
    END
  END a[73]
  PIN a[74]
    DIRECTION INPUT ;
    USE SIGNAL ;
    PORT
      LAYER M3 ;
        RECT  41.58 0 41.598 0.037 ;
    END
  END a[74]
  PIN a[75]
    DIRECTION INPUT ;
    USE SIGNAL ;
    PORT
      LAYER M3 ;
        RECT  41.652 0 41.67 0.037 ;
    END
  END a[75]
  PIN a[76]
    DIRECTION INPUT ;
    USE SIGNAL ;
    PORT
      LAYER M3 ;
        RECT  41.724 0 41.742 0.037 ;
    END
  END a[76]
  PIN a[77]
    DIRECTION INPUT ;
    USE SIGNAL ;
    PORT
      LAYER M3 ;
        RECT  41.796 0 41.814 0.037 ;
    END
  END a[77]
  PIN a[78]
    DIRECTION INPUT ;
    USE SIGNAL ;
    PORT
      LAYER M3 ;
        RECT  41.868 0 41.886 0.037 ;
    END
  END a[78]
  PIN a[79]
    DIRECTION INPUT ;
    USE SIGNAL ;
    PORT
      LAYER M3 ;
        RECT  41.94 0 41.958 0.037 ;
    END
  END a[79]
  PIN a[7]
    DIRECTION INPUT ;
    USE SIGNAL ;
    PORT
      LAYER M5 ;
        RECT  35.952 0 35.976 0.084 ;
    END
  END a[7]
  PIN a[80]
    DIRECTION INPUT ;
    USE SIGNAL ;
    PORT
      LAYER M3 ;
        RECT  42.012 0 42.03 0.037 ;
    END
  END a[80]
  PIN a[81]
    DIRECTION INPUT ;
    USE SIGNAL ;
    PORT
      LAYER M3 ;
        RECT  42.084 0 42.102 0.037 ;
    END
  END a[81]
  PIN a[82]
    DIRECTION INPUT ;
    USE SIGNAL ;
    PORT
      LAYER M3 ;
        RECT  42.156 0 42.174 0.037 ;
    END
  END a[82]
  PIN a[83]
    DIRECTION INPUT ;
    USE SIGNAL ;
    PORT
      LAYER M3 ;
        RECT  42.228 0 42.246 0.037 ;
    END
  END a[83]
  PIN a[84]
    DIRECTION INPUT ;
    USE SIGNAL ;
    PORT
      LAYER M3 ;
        RECT  42.3 0 42.318 0.037 ;
    END
  END a[84]
  PIN a[85]
    DIRECTION INPUT ;
    USE SIGNAL ;
    PORT
      LAYER M3 ;
        RECT  42.372 0 42.39 0.037 ;
    END
  END a[85]
  PIN a[86]
    DIRECTION INPUT ;
    USE SIGNAL ;
    PORT
      LAYER M3 ;
        RECT  42.444 0 42.462 0.037 ;
    END
  END a[86]
  PIN a[87]
    DIRECTION INPUT ;
    USE SIGNAL ;
    PORT
      LAYER M3 ;
        RECT  42.516 0 42.534 0.037 ;
    END
  END a[87]
  PIN a[88]
    DIRECTION INPUT ;
    USE SIGNAL ;
    PORT
      LAYER M3 ;
        RECT  42.588 0 42.606 0.037 ;
    END
  END a[88]
  PIN a[89]
    DIRECTION INPUT ;
    USE SIGNAL ;
    PORT
      LAYER M3 ;
        RECT  42.66 0 42.678 0.037 ;
    END
  END a[89]
  PIN a[8]
    DIRECTION INPUT ;
    USE SIGNAL ;
    PORT
      LAYER M5 ;
        RECT  36.048 0 36.072 0.084 ;
    END
  END a[8]
  PIN a[90]
    DIRECTION INPUT ;
    USE SIGNAL ;
    PORT
      LAYER M3 ;
        RECT  42.732 0 42.75 0.037 ;
    END
  END a[90]
  PIN a[91]
    DIRECTION INPUT ;
    USE SIGNAL ;
    PORT
      LAYER M3 ;
        RECT  42.804 0 42.822 0.037 ;
    END
  END a[91]
  PIN a[92]
    DIRECTION INPUT ;
    USE SIGNAL ;
    PORT
      LAYER M3 ;
        RECT  42.876 0 42.894 0.037 ;
    END
  END a[92]
  PIN a[93]
    DIRECTION INPUT ;
    USE SIGNAL ;
    PORT
      LAYER M3 ;
        RECT  42.948 0 42.966 0.037 ;
    END
  END a[93]
  PIN a[94]
    DIRECTION INPUT ;
    USE SIGNAL ;
    PORT
      LAYER M3 ;
        RECT  43.02 0 43.038 0.037 ;
    END
  END a[94]
  PIN a[95]
    DIRECTION INPUT ;
    USE SIGNAL ;
    PORT
      LAYER M3 ;
        RECT  43.092 0 43.11 0.037 ;
    END
  END a[95]
  PIN a[96]
    DIRECTION INPUT ;
    USE SIGNAL ;
    PORT
      LAYER M3 ;
        RECT  36.252 0 36.27 0.037 ;
    END
  END a[96]
  PIN a[97]
    DIRECTION INPUT ;
    USE SIGNAL ;
    PORT
      LAYER M3 ;
        RECT  36.324 0 36.342 0.037 ;
    END
  END a[97]
  PIN a[98]
    DIRECTION INPUT ;
    USE SIGNAL ;
    PORT
      LAYER M3 ;
        RECT  36.396 0 36.414 0.037 ;
    END
  END a[98]
  PIN a[99]
    DIRECTION INPUT ;
    USE SIGNAL ;
    PORT
      LAYER M3 ;
        RECT  36.468 0 36.486 0.037 ;
    END
  END a[99]
  PIN a[9]
    DIRECTION INPUT ;
    USE SIGNAL ;
    PORT
      LAYER M5 ;
        RECT  36.144 0 36.168 0.084 ;
    END
  END a[9]
  PIN b[0]
    DIRECTION OUTPUT ;
    USE SIGNAL ;
    PORT
      LAYER M5 ;
        RECT  32.592 60.372 32.616 60.456 ;
    END
  END b[0]
  PIN b[100]
    DIRECTION OUTPUT ;
    USE SIGNAL ;
    PORT
      LAYER M5 ;
        RECT  42.192 60.372 42.216 60.456 ;
    END
  END b[100]
  PIN b[101]
    DIRECTION OUTPUT ;
    USE SIGNAL ;
    PORT
      LAYER M5 ;
        RECT  42.288 60.372 42.312 60.456 ;
    END
  END b[101]
  PIN b[102]
    DIRECTION OUTPUT ;
    USE SIGNAL ;
    PORT
      LAYER M5 ;
        RECT  42.384 60.372 42.408 60.456 ;
    END
  END b[102]
  PIN b[103]
    DIRECTION OUTPUT ;
    USE SIGNAL ;
    PORT
      LAYER M5 ;
        RECT  42.48 60.372 42.504 60.456 ;
    END
  END b[103]
  PIN b[104]
    DIRECTION OUTPUT ;
    USE SIGNAL ;
    PORT
      LAYER M5 ;
        RECT  42.576 60.372 42.6 60.456 ;
    END
  END b[104]
  PIN b[105]
    DIRECTION OUTPUT ;
    USE SIGNAL ;
    PORT
      LAYER M5 ;
        RECT  42.672 60.372 42.696 60.456 ;
    END
  END b[105]
  PIN b[106]
    DIRECTION OUTPUT ;
    USE SIGNAL ;
    PORT
      LAYER M5 ;
        RECT  42.768 60.372 42.792 60.456 ;
    END
  END b[106]
  PIN b[107]
    DIRECTION OUTPUT ;
    USE SIGNAL ;
    PORT
      LAYER M5 ;
        RECT  42.864 60.372 42.888 60.456 ;
    END
  END b[107]
  PIN b[108]
    DIRECTION OUTPUT ;
    USE SIGNAL ;
    PORT
      LAYER M5 ;
        RECT  42.96 60.372 42.984 60.456 ;
    END
  END b[108]
  PIN b[109]
    DIRECTION OUTPUT ;
    USE SIGNAL ;
    PORT
      LAYER M5 ;
        RECT  43.056 60.372 43.08 60.456 ;
    END
  END b[109]
  PIN b[10]
    DIRECTION OUTPUT ;
    USE SIGNAL ;
    PORT
      LAYER M5 ;
        RECT  33.552 60.372 33.576 60.456 ;
    END
  END b[10]
  PIN b[110]
    DIRECTION OUTPUT ;
    USE SIGNAL ;
    PORT
      LAYER M5 ;
        RECT  43.152 60.372 43.176 60.456 ;
    END
  END b[110]
  PIN b[111]
    DIRECTION OUTPUT ;
    USE SIGNAL ;
    PORT
      LAYER M5 ;
        RECT  43.248 60.372 43.272 60.456 ;
    END
  END b[111]
  PIN b[112]
    DIRECTION OUTPUT ;
    USE SIGNAL ;
    PORT
      LAYER M5 ;
        RECT  43.344 60.372 43.368 60.456 ;
    END
  END b[112]
  PIN b[113]
    DIRECTION OUTPUT ;
    USE SIGNAL ;
    PORT
      LAYER M5 ;
        RECT  43.44 60.372 43.464 60.456 ;
    END
  END b[113]
  PIN b[114]
    DIRECTION OUTPUT ;
    USE SIGNAL ;
    PORT
      LAYER M5 ;
        RECT  43.536 60.372 43.56 60.456 ;
    END
  END b[114]
  PIN b[115]
    DIRECTION OUTPUT ;
    USE SIGNAL ;
    PORT
      LAYER M5 ;
        RECT  43.632 60.372 43.656 60.456 ;
    END
  END b[115]
  PIN b[116]
    DIRECTION OUTPUT ;
    USE SIGNAL ;
    PORT
      LAYER M5 ;
        RECT  43.728 60.372 43.752 60.456 ;
    END
  END b[116]
  PIN b[117]
    DIRECTION OUTPUT ;
    USE SIGNAL ;
    PORT
      LAYER M5 ;
        RECT  43.824 60.372 43.848 60.456 ;
    END
  END b[117]
  PIN b[118]
    DIRECTION OUTPUT ;
    USE SIGNAL ;
    PORT
      LAYER M5 ;
        RECT  43.92 60.372 43.944 60.456 ;
    END
  END b[118]
  PIN b[119]
    DIRECTION OUTPUT ;
    USE SIGNAL ;
    PORT
      LAYER M5 ;
        RECT  44.016 60.372 44.04 60.456 ;
    END
  END b[119]
  PIN b[11]
    DIRECTION OUTPUT ;
    USE SIGNAL ;
    PORT
      LAYER M5 ;
        RECT  33.648 60.372 33.672 60.456 ;
    END
  END b[11]
  PIN b[120]
    DIRECTION OUTPUT ;
    USE SIGNAL ;
    PORT
      LAYER M5 ;
        RECT  44.112 60.372 44.136 60.456 ;
    END
  END b[120]
  PIN b[121]
    DIRECTION OUTPUT ;
    USE SIGNAL ;
    PORT
      LAYER M5 ;
        RECT  44.208 60.372 44.232 60.456 ;
    END
  END b[121]
  PIN b[122]
    DIRECTION OUTPUT ;
    USE SIGNAL ;
    PORT
      LAYER M5 ;
        RECT  44.304 60.372 44.328 60.456 ;
    END
  END b[122]
  PIN b[123]
    DIRECTION OUTPUT ;
    USE SIGNAL ;
    PORT
      LAYER M5 ;
        RECT  44.4 60.372 44.424 60.456 ;
    END
  END b[123]
  PIN b[124]
    DIRECTION OUTPUT ;
    USE SIGNAL ;
    PORT
      LAYER M5 ;
        RECT  44.496 60.372 44.52 60.456 ;
    END
  END b[124]
  PIN b[125]
    DIRECTION OUTPUT ;
    USE SIGNAL ;
    PORT
      LAYER M5 ;
        RECT  44.592 60.372 44.616 60.456 ;
    END
  END b[125]
  PIN b[126]
    DIRECTION OUTPUT ;
    USE SIGNAL ;
    PORT
      LAYER M5 ;
        RECT  44.688 60.372 44.712 60.456 ;
    END
  END b[126]
  PIN b[127]
    DIRECTION OUTPUT ;
    USE SIGNAL ;
    PORT
      LAYER M5 ;
        RECT  44.784 60.372 44.808 60.456 ;
    END
  END b[127]
  PIN b[128]
    DIRECTION OUTPUT ;
    USE SIGNAL ;
    PORT
      LAYER M5 ;
        RECT  35.664 60.372 35.688 60.456 ;
    END
  END b[128]
  PIN b[129]
    DIRECTION OUTPUT ;
    USE SIGNAL ;
    PORT
      LAYER M5 ;
        RECT  35.76 60.372 35.784 60.456 ;
    END
  END b[129]
  PIN b[12]
    DIRECTION OUTPUT ;
    USE SIGNAL ;
    PORT
      LAYER M5 ;
        RECT  33.744 60.372 33.768 60.456 ;
    END
  END b[12]
  PIN b[130]
    DIRECTION OUTPUT ;
    USE SIGNAL ;
    PORT
      LAYER M5 ;
        RECT  35.856 60.372 35.88 60.456 ;
    END
  END b[130]
  PIN b[131]
    DIRECTION OUTPUT ;
    USE SIGNAL ;
    PORT
      LAYER M5 ;
        RECT  35.952 60.372 35.976 60.456 ;
    END
  END b[131]
  PIN b[132]
    DIRECTION OUTPUT ;
    USE SIGNAL ;
    PORT
      LAYER M5 ;
        RECT  36.048 60.372 36.072 60.456 ;
    END
  END b[132]
  PIN b[133]
    DIRECTION OUTPUT ;
    USE SIGNAL ;
    PORT
      LAYER M5 ;
        RECT  36.144 60.372 36.168 60.456 ;
    END
  END b[133]
  PIN b[134]
    DIRECTION OUTPUT ;
    USE SIGNAL ;
    PORT
      LAYER M5 ;
        RECT  36.24 60.372 36.264 60.456 ;
    END
  END b[134]
  PIN b[135]
    DIRECTION OUTPUT ;
    USE SIGNAL ;
    PORT
      LAYER M5 ;
        RECT  36.336 60.372 36.36 60.456 ;
    END
  END b[135]
  PIN b[136]
    DIRECTION OUTPUT ;
    USE SIGNAL ;
    PORT
      LAYER M5 ;
        RECT  36.432 60.372 36.456 60.456 ;
    END
  END b[136]
  PIN b[137]
    DIRECTION OUTPUT ;
    USE SIGNAL ;
    PORT
      LAYER M5 ;
        RECT  36.528 60.372 36.552 60.456 ;
    END
  END b[137]
  PIN b[138]
    DIRECTION OUTPUT ;
    USE SIGNAL ;
    PORT
      LAYER M5 ;
        RECT  36.624 60.372 36.648 60.456 ;
    END
  END b[138]
  PIN b[139]
    DIRECTION OUTPUT ;
    USE SIGNAL ;
    PORT
      LAYER M5 ;
        RECT  36.72 60.372 36.744 60.456 ;
    END
  END b[139]
  PIN b[13]
    DIRECTION OUTPUT ;
    USE SIGNAL ;
    PORT
      LAYER M5 ;
        RECT  33.84 60.372 33.864 60.456 ;
    END
  END b[13]
  PIN b[140]
    DIRECTION OUTPUT ;
    USE SIGNAL ;
    PORT
      LAYER M5 ;
        RECT  36.816 60.372 36.84 60.456 ;
    END
  END b[140]
  PIN b[141]
    DIRECTION OUTPUT ;
    USE SIGNAL ;
    PORT
      LAYER M5 ;
        RECT  36.912 60.372 36.936 60.456 ;
    END
  END b[141]
  PIN b[142]
    DIRECTION OUTPUT ;
    USE SIGNAL ;
    PORT
      LAYER M5 ;
        RECT  37.008 60.372 37.032 60.456 ;
    END
  END b[142]
  PIN b[143]
    DIRECTION OUTPUT ;
    USE SIGNAL ;
    PORT
      LAYER M5 ;
        RECT  37.104 60.372 37.128 60.456 ;
    END
  END b[143]
  PIN b[144]
    DIRECTION OUTPUT ;
    USE SIGNAL ;
    PORT
      LAYER M5 ;
        RECT  37.2 60.372 37.224 60.456 ;
    END
  END b[144]
  PIN b[145]
    DIRECTION OUTPUT ;
    USE SIGNAL ;
    PORT
      LAYER M5 ;
        RECT  37.296 60.372 37.32 60.456 ;
    END
  END b[145]
  PIN b[146]
    DIRECTION OUTPUT ;
    USE SIGNAL ;
    PORT
      LAYER M5 ;
        RECT  37.392 60.372 37.416 60.456 ;
    END
  END b[146]
  PIN b[147]
    DIRECTION OUTPUT ;
    USE SIGNAL ;
    PORT
      LAYER M5 ;
        RECT  37.488 60.372 37.512 60.456 ;
    END
  END b[147]
  PIN b[148]
    DIRECTION OUTPUT ;
    USE SIGNAL ;
    PORT
      LAYER M5 ;
        RECT  37.584 60.372 37.608 60.456 ;
    END
  END b[148]
  PIN b[149]
    DIRECTION OUTPUT ;
    USE SIGNAL ;
    PORT
      LAYER M5 ;
        RECT  37.68 60.372 37.704 60.456 ;
    END
  END b[149]
  PIN b[14]
    DIRECTION OUTPUT ;
    USE SIGNAL ;
    PORT
      LAYER M5 ;
        RECT  33.936 60.372 33.96 60.456 ;
    END
  END b[14]
  PIN b[150]
    DIRECTION OUTPUT ;
    USE SIGNAL ;
    PORT
      LAYER M5 ;
        RECT  37.776 60.372 37.8 60.456 ;
    END
  END b[150]
  PIN b[151]
    DIRECTION OUTPUT ;
    USE SIGNAL ;
    PORT
      LAYER M5 ;
        RECT  37.872 60.372 37.896 60.456 ;
    END
  END b[151]
  PIN b[152]
    DIRECTION OUTPUT ;
    USE SIGNAL ;
    PORT
      LAYER M5 ;
        RECT  37.968 60.372 37.992 60.456 ;
    END
  END b[152]
  PIN b[153]
    DIRECTION OUTPUT ;
    USE SIGNAL ;
    PORT
      LAYER M5 ;
        RECT  38.064 60.372 38.088 60.456 ;
    END
  END b[153]
  PIN b[154]
    DIRECTION OUTPUT ;
    USE SIGNAL ;
    PORT
      LAYER M5 ;
        RECT  38.16 60.372 38.184 60.456 ;
    END
  END b[154]
  PIN b[155]
    DIRECTION OUTPUT ;
    USE SIGNAL ;
    PORT
      LAYER M5 ;
        RECT  38.256 60.372 38.28 60.456 ;
    END
  END b[155]
  PIN b[156]
    DIRECTION OUTPUT ;
    USE SIGNAL ;
    PORT
      LAYER M5 ;
        RECT  38.352 60.372 38.376 60.456 ;
    END
  END b[156]
  PIN b[157]
    DIRECTION OUTPUT ;
    USE SIGNAL ;
    PORT
      LAYER M5 ;
        RECT  38.448 60.372 38.472 60.456 ;
    END
  END b[157]
  PIN b[158]
    DIRECTION OUTPUT ;
    USE SIGNAL ;
    PORT
      LAYER M5 ;
        RECT  38.544 60.372 38.568 60.456 ;
    END
  END b[158]
  PIN b[159]
    DIRECTION OUTPUT ;
    USE SIGNAL ;
    PORT
      LAYER M5 ;
        RECT  38.64 60.372 38.664 60.456 ;
    END
  END b[159]
  PIN b[15]
    DIRECTION OUTPUT ;
    USE SIGNAL ;
    PORT
      LAYER M5 ;
        RECT  34.032 60.372 34.056 60.456 ;
    END
  END b[15]
  PIN b[160]
    DIRECTION OUTPUT ;
    USE SIGNAL ;
    PORT
      LAYER M5 ;
        RECT  26.448 60.372 26.472 60.456 ;
    END
  END b[160]
  PIN b[161]
    DIRECTION OUTPUT ;
    USE SIGNAL ;
    PORT
      LAYER M5 ;
        RECT  26.544 60.372 26.568 60.456 ;
    END
  END b[161]
  PIN b[162]
    DIRECTION OUTPUT ;
    USE SIGNAL ;
    PORT
      LAYER M5 ;
        RECT  26.64 60.372 26.664 60.456 ;
    END
  END b[162]
  PIN b[163]
    DIRECTION OUTPUT ;
    USE SIGNAL ;
    PORT
      LAYER M5 ;
        RECT  26.736 60.372 26.76 60.456 ;
    END
  END b[163]
  PIN b[164]
    DIRECTION OUTPUT ;
    USE SIGNAL ;
    PORT
      LAYER M5 ;
        RECT  26.832 60.372 26.856 60.456 ;
    END
  END b[164]
  PIN b[165]
    DIRECTION OUTPUT ;
    USE SIGNAL ;
    PORT
      LAYER M5 ;
        RECT  26.928 60.372 26.952 60.456 ;
    END
  END b[165]
  PIN b[166]
    DIRECTION OUTPUT ;
    USE SIGNAL ;
    PORT
      LAYER M5 ;
        RECT  27.024 60.372 27.048 60.456 ;
    END
  END b[166]
  PIN b[167]
    DIRECTION OUTPUT ;
    USE SIGNAL ;
    PORT
      LAYER M5 ;
        RECT  27.12 60.372 27.144 60.456 ;
    END
  END b[167]
  PIN b[168]
    DIRECTION OUTPUT ;
    USE SIGNAL ;
    PORT
      LAYER M5 ;
        RECT  27.216 60.372 27.24 60.456 ;
    END
  END b[168]
  PIN b[169]
    DIRECTION OUTPUT ;
    USE SIGNAL ;
    PORT
      LAYER M5 ;
        RECT  27.312 60.372 27.336 60.456 ;
    END
  END b[169]
  PIN b[16]
    DIRECTION OUTPUT ;
    USE SIGNAL ;
    PORT
      LAYER M5 ;
        RECT  34.128 60.372 34.152 60.456 ;
    END
  END b[16]
  PIN b[170]
    DIRECTION OUTPUT ;
    USE SIGNAL ;
    PORT
      LAYER M5 ;
        RECT  27.408 60.372 27.432 60.456 ;
    END
  END b[170]
  PIN b[171]
    DIRECTION OUTPUT ;
    USE SIGNAL ;
    PORT
      LAYER M5 ;
        RECT  27.504 60.372 27.528 60.456 ;
    END
  END b[171]
  PIN b[172]
    DIRECTION OUTPUT ;
    USE SIGNAL ;
    PORT
      LAYER M5 ;
        RECT  27.6 60.372 27.624 60.456 ;
    END
  END b[172]
  PIN b[173]
    DIRECTION OUTPUT ;
    USE SIGNAL ;
    PORT
      LAYER M5 ;
        RECT  27.696 60.372 27.72 60.456 ;
    END
  END b[173]
  PIN b[174]
    DIRECTION OUTPUT ;
    USE SIGNAL ;
    PORT
      LAYER M5 ;
        RECT  27.792 60.372 27.816 60.456 ;
    END
  END b[174]
  PIN b[175]
    DIRECTION OUTPUT ;
    USE SIGNAL ;
    PORT
      LAYER M5 ;
        RECT  27.888 60.372 27.912 60.456 ;
    END
  END b[175]
  PIN b[176]
    DIRECTION OUTPUT ;
    USE SIGNAL ;
    PORT
      LAYER M5 ;
        RECT  27.984 60.372 28.008 60.456 ;
    END
  END b[176]
  PIN b[177]
    DIRECTION OUTPUT ;
    USE SIGNAL ;
    PORT
      LAYER M5 ;
        RECT  28.08 60.372 28.104 60.456 ;
    END
  END b[177]
  PIN b[178]
    DIRECTION OUTPUT ;
    USE SIGNAL ;
    PORT
      LAYER M5 ;
        RECT  28.176 60.372 28.2 60.456 ;
    END
  END b[178]
  PIN b[179]
    DIRECTION OUTPUT ;
    USE SIGNAL ;
    PORT
      LAYER M5 ;
        RECT  28.272 60.372 28.296 60.456 ;
    END
  END b[179]
  PIN b[17]
    DIRECTION OUTPUT ;
    USE SIGNAL ;
    PORT
      LAYER M5 ;
        RECT  34.224 60.372 34.248 60.456 ;
    END
  END b[17]
  PIN b[180]
    DIRECTION OUTPUT ;
    USE SIGNAL ;
    PORT
      LAYER M5 ;
        RECT  28.368 60.372 28.392 60.456 ;
    END
  END b[180]
  PIN b[181]
    DIRECTION OUTPUT ;
    USE SIGNAL ;
    PORT
      LAYER M5 ;
        RECT  28.464 60.372 28.488 60.456 ;
    END
  END b[181]
  PIN b[182]
    DIRECTION OUTPUT ;
    USE SIGNAL ;
    PORT
      LAYER M5 ;
        RECT  28.56 60.372 28.584 60.456 ;
    END
  END b[182]
  PIN b[183]
    DIRECTION OUTPUT ;
    USE SIGNAL ;
    PORT
      LAYER M5 ;
        RECT  28.656 60.372 28.68 60.456 ;
    END
  END b[183]
  PIN b[184]
    DIRECTION OUTPUT ;
    USE SIGNAL ;
    PORT
      LAYER M5 ;
        RECT  28.752 60.372 28.776 60.456 ;
    END
  END b[184]
  PIN b[185]
    DIRECTION OUTPUT ;
    USE SIGNAL ;
    PORT
      LAYER M5 ;
        RECT  28.848 60.372 28.872 60.456 ;
    END
  END b[185]
  PIN b[186]
    DIRECTION OUTPUT ;
    USE SIGNAL ;
    PORT
      LAYER M5 ;
        RECT  28.944 60.372 28.968 60.456 ;
    END
  END b[186]
  PIN b[187]
    DIRECTION OUTPUT ;
    USE SIGNAL ;
    PORT
      LAYER M5 ;
        RECT  29.04 60.372 29.064 60.456 ;
    END
  END b[187]
  PIN b[188]
    DIRECTION OUTPUT ;
    USE SIGNAL ;
    PORT
      LAYER M5 ;
        RECT  29.136 60.372 29.16 60.456 ;
    END
  END b[188]
  PIN b[189]
    DIRECTION OUTPUT ;
    USE SIGNAL ;
    PORT
      LAYER M5 ;
        RECT  29.232 60.372 29.256 60.456 ;
    END
  END b[189]
  PIN b[18]
    DIRECTION OUTPUT ;
    USE SIGNAL ;
    PORT
      LAYER M5 ;
        RECT  34.32 60.372 34.344 60.456 ;
    END
  END b[18]
  PIN b[190]
    DIRECTION OUTPUT ;
    USE SIGNAL ;
    PORT
      LAYER M5 ;
        RECT  29.328 60.372 29.352 60.456 ;
    END
  END b[190]
  PIN b[191]
    DIRECTION OUTPUT ;
    USE SIGNAL ;
    PORT
      LAYER M5 ;
        RECT  29.424 60.372 29.448 60.456 ;
    END
  END b[191]
  PIN b[192]
    DIRECTION OUTPUT ;
    USE SIGNAL ;
    PORT
      LAYER M3 ;
        RECT  21.636 60.419 21.654 60.456 ;
    END
  END b[192]
  PIN b[193]
    DIRECTION OUTPUT ;
    USE SIGNAL ;
    PORT
      LAYER M3 ;
        RECT  21.708 60.419 21.726 60.456 ;
    END
  END b[193]
  PIN b[194]
    DIRECTION OUTPUT ;
    USE SIGNAL ;
    PORT
      LAYER M3 ;
        RECT  21.78 60.419 21.798 60.456 ;
    END
  END b[194]
  PIN b[195]
    DIRECTION OUTPUT ;
    USE SIGNAL ;
    PORT
      LAYER M3 ;
        RECT  21.852 60.419 21.87 60.456 ;
    END
  END b[195]
  PIN b[196]
    DIRECTION OUTPUT ;
    USE SIGNAL ;
    PORT
      LAYER M3 ;
        RECT  21.924 60.419 21.942 60.456 ;
    END
  END b[196]
  PIN b[197]
    DIRECTION OUTPUT ;
    USE SIGNAL ;
    PORT
      LAYER M3 ;
        RECT  21.996 60.419 22.014 60.456 ;
    END
  END b[197]
  PIN b[198]
    DIRECTION OUTPUT ;
    USE SIGNAL ;
    PORT
      LAYER M3 ;
        RECT  22.068 60.419 22.086 60.456 ;
    END
  END b[198]
  PIN b[199]
    DIRECTION OUTPUT ;
    USE SIGNAL ;
    PORT
      LAYER M3 ;
        RECT  22.14 60.419 22.158 60.456 ;
    END
  END b[199]
  PIN b[19]
    DIRECTION OUTPUT ;
    USE SIGNAL ;
    PORT
      LAYER M5 ;
        RECT  34.416 60.372 34.44 60.456 ;
    END
  END b[19]
  PIN b[1]
    DIRECTION OUTPUT ;
    USE SIGNAL ;
    PORT
      LAYER M5 ;
        RECT  32.688 60.372 32.712 60.456 ;
    END
  END b[1]
  PIN b[200]
    DIRECTION OUTPUT ;
    USE SIGNAL ;
    PORT
      LAYER M3 ;
        RECT  22.212 60.419 22.23 60.456 ;
    END
  END b[200]
  PIN b[201]
    DIRECTION OUTPUT ;
    USE SIGNAL ;
    PORT
      LAYER M3 ;
        RECT  22.284 60.419 22.302 60.456 ;
    END
  END b[201]
  PIN b[202]
    DIRECTION OUTPUT ;
    USE SIGNAL ;
    PORT
      LAYER M3 ;
        RECT  22.356 60.419 22.374 60.456 ;
    END
  END b[202]
  PIN b[203]
    DIRECTION OUTPUT ;
    USE SIGNAL ;
    PORT
      LAYER M3 ;
        RECT  22.428 60.419 22.446 60.456 ;
    END
  END b[203]
  PIN b[204]
    DIRECTION OUTPUT ;
    USE SIGNAL ;
    PORT
      LAYER M3 ;
        RECT  22.5 60.419 22.518 60.456 ;
    END
  END b[204]
  PIN b[205]
    DIRECTION OUTPUT ;
    USE SIGNAL ;
    PORT
      LAYER M3 ;
        RECT  22.572 60.419 22.59 60.456 ;
    END
  END b[205]
  PIN b[206]
    DIRECTION OUTPUT ;
    USE SIGNAL ;
    PORT
      LAYER M3 ;
        RECT  22.644 60.419 22.662 60.456 ;
    END
  END b[206]
  PIN b[207]
    DIRECTION OUTPUT ;
    USE SIGNAL ;
    PORT
      LAYER M3 ;
        RECT  22.716 60.419 22.734 60.456 ;
    END
  END b[207]
  PIN b[208]
    DIRECTION OUTPUT ;
    USE SIGNAL ;
    PORT
      LAYER M3 ;
        RECT  22.788 60.419 22.806 60.456 ;
    END
  END b[208]
  PIN b[209]
    DIRECTION OUTPUT ;
    USE SIGNAL ;
    PORT
      LAYER M3 ;
        RECT  22.86 60.419 22.878 60.456 ;
    END
  END b[209]
  PIN b[20]
    DIRECTION OUTPUT ;
    USE SIGNAL ;
    PORT
      LAYER M5 ;
        RECT  34.512 60.372 34.536 60.456 ;
    END
  END b[20]
  PIN b[210]
    DIRECTION OUTPUT ;
    USE SIGNAL ;
    PORT
      LAYER M3 ;
        RECT  22.932 60.419 22.95 60.456 ;
    END
  END b[210]
  PIN b[211]
    DIRECTION OUTPUT ;
    USE SIGNAL ;
    PORT
      LAYER M3 ;
        RECT  23.004 60.419 23.022 60.456 ;
    END
  END b[211]
  PIN b[212]
    DIRECTION OUTPUT ;
    USE SIGNAL ;
    PORT
      LAYER M3 ;
        RECT  23.076 60.419 23.094 60.456 ;
    END
  END b[212]
  PIN b[213]
    DIRECTION OUTPUT ;
    USE SIGNAL ;
    PORT
      LAYER M3 ;
        RECT  23.148 60.419 23.166 60.456 ;
    END
  END b[213]
  PIN b[214]
    DIRECTION OUTPUT ;
    USE SIGNAL ;
    PORT
      LAYER M3 ;
        RECT  23.22 60.419 23.238 60.456 ;
    END
  END b[214]
  PIN b[215]
    DIRECTION OUTPUT ;
    USE SIGNAL ;
    PORT
      LAYER M3 ;
        RECT  23.292 60.419 23.31 60.456 ;
    END
  END b[215]
  PIN b[216]
    DIRECTION OUTPUT ;
    USE SIGNAL ;
    PORT
      LAYER M3 ;
        RECT  23.364 60.419 23.382 60.456 ;
    END
  END b[216]
  PIN b[217]
    DIRECTION OUTPUT ;
    USE SIGNAL ;
    PORT
      LAYER M3 ;
        RECT  23.436 60.419 23.454 60.456 ;
    END
  END b[217]
  PIN b[218]
    DIRECTION OUTPUT ;
    USE SIGNAL ;
    PORT
      LAYER M3 ;
        RECT  23.508 60.419 23.526 60.456 ;
    END
  END b[218]
  PIN b[219]
    DIRECTION OUTPUT ;
    USE SIGNAL ;
    PORT
      LAYER M3 ;
        RECT  23.58 60.419 23.598 60.456 ;
    END
  END b[219]
  PIN b[21]
    DIRECTION OUTPUT ;
    USE SIGNAL ;
    PORT
      LAYER M5 ;
        RECT  34.608 60.372 34.632 60.456 ;
    END
  END b[21]
  PIN b[220]
    DIRECTION OUTPUT ;
    USE SIGNAL ;
    PORT
      LAYER M3 ;
        RECT  23.652 60.419 23.67 60.456 ;
    END
  END b[220]
  PIN b[221]
    DIRECTION OUTPUT ;
    USE SIGNAL ;
    PORT
      LAYER M3 ;
        RECT  23.724 60.419 23.742 60.456 ;
    END
  END b[221]
  PIN b[222]
    DIRECTION OUTPUT ;
    USE SIGNAL ;
    PORT
      LAYER M3 ;
        RECT  23.796 60.419 23.814 60.456 ;
    END
  END b[222]
  PIN b[223]
    DIRECTION OUTPUT ;
    USE SIGNAL ;
    PORT
      LAYER M3 ;
        RECT  23.868 60.419 23.886 60.456 ;
    END
  END b[223]
  PIN b[224]
    DIRECTION OUTPUT ;
    USE SIGNAL ;
    PORT
      LAYER M3 ;
        RECT  28.548 60.419 28.566 60.456 ;
    END
  END b[224]
  PIN b[225]
    DIRECTION OUTPUT ;
    USE SIGNAL ;
    PORT
      LAYER M3 ;
        RECT  28.62 60.419 28.638 60.456 ;
    END
  END b[225]
  PIN b[226]
    DIRECTION OUTPUT ;
    USE SIGNAL ;
    PORT
      LAYER M3 ;
        RECT  28.692 60.419 28.71 60.456 ;
    END
  END b[226]
  PIN b[227]
    DIRECTION OUTPUT ;
    USE SIGNAL ;
    PORT
      LAYER M3 ;
        RECT  28.764 60.419 28.782 60.456 ;
    END
  END b[227]
  PIN b[228]
    DIRECTION OUTPUT ;
    USE SIGNAL ;
    PORT
      LAYER M3 ;
        RECT  28.836 60.419 28.854 60.456 ;
    END
  END b[228]
  PIN b[229]
    DIRECTION OUTPUT ;
    USE SIGNAL ;
    PORT
      LAYER M3 ;
        RECT  28.908 60.419 28.926 60.456 ;
    END
  END b[229]
  PIN b[22]
    DIRECTION OUTPUT ;
    USE SIGNAL ;
    PORT
      LAYER M5 ;
        RECT  34.704 60.372 34.728 60.456 ;
    END
  END b[22]
  PIN b[230]
    DIRECTION OUTPUT ;
    USE SIGNAL ;
    PORT
      LAYER M3 ;
        RECT  28.98 60.419 28.998 60.456 ;
    END
  END b[230]
  PIN b[231]
    DIRECTION OUTPUT ;
    USE SIGNAL ;
    PORT
      LAYER M3 ;
        RECT  29.052 60.419 29.07 60.456 ;
    END
  END b[231]
  PIN b[232]
    DIRECTION OUTPUT ;
    USE SIGNAL ;
    PORT
      LAYER M3 ;
        RECT  29.124 60.419 29.142 60.456 ;
    END
  END b[232]
  PIN b[233]
    DIRECTION OUTPUT ;
    USE SIGNAL ;
    PORT
      LAYER M3 ;
        RECT  29.196 60.419 29.214 60.456 ;
    END
  END b[233]
  PIN b[234]
    DIRECTION OUTPUT ;
    USE SIGNAL ;
    PORT
      LAYER M3 ;
        RECT  29.268 60.419 29.286 60.456 ;
    END
  END b[234]
  PIN b[235]
    DIRECTION OUTPUT ;
    USE SIGNAL ;
    PORT
      LAYER M3 ;
        RECT  29.34 60.419 29.358 60.456 ;
    END
  END b[235]
  PIN b[236]
    DIRECTION OUTPUT ;
    USE SIGNAL ;
    PORT
      LAYER M3 ;
        RECT  29.412 60.419 29.43 60.456 ;
    END
  END b[236]
  PIN b[237]
    DIRECTION OUTPUT ;
    USE SIGNAL ;
    PORT
      LAYER M3 ;
        RECT  29.484 60.419 29.502 60.456 ;
    END
  END b[237]
  PIN b[238]
    DIRECTION OUTPUT ;
    USE SIGNAL ;
    PORT
      LAYER M3 ;
        RECT  29.556 60.419 29.574 60.456 ;
    END
  END b[238]
  PIN b[239]
    DIRECTION OUTPUT ;
    USE SIGNAL ;
    PORT
      LAYER M3 ;
        RECT  29.628 60.419 29.646 60.456 ;
    END
  END b[239]
  PIN b[23]
    DIRECTION OUTPUT ;
    USE SIGNAL ;
    PORT
      LAYER M5 ;
        RECT  34.8 60.372 34.824 60.456 ;
    END
  END b[23]
  PIN b[240]
    DIRECTION OUTPUT ;
    USE SIGNAL ;
    PORT
      LAYER M3 ;
        RECT  29.7 60.419 29.718 60.456 ;
    END
  END b[240]
  PIN b[241]
    DIRECTION OUTPUT ;
    USE SIGNAL ;
    PORT
      LAYER M3 ;
        RECT  29.772 60.419 29.79 60.456 ;
    END
  END b[241]
  PIN b[242]
    DIRECTION OUTPUT ;
    USE SIGNAL ;
    PORT
      LAYER M3 ;
        RECT  29.844 60.419 29.862 60.456 ;
    END
  END b[242]
  PIN b[243]
    DIRECTION OUTPUT ;
    USE SIGNAL ;
    PORT
      LAYER M3 ;
        RECT  29.916 60.419 29.934 60.456 ;
    END
  END b[243]
  PIN b[244]
    DIRECTION OUTPUT ;
    USE SIGNAL ;
    PORT
      LAYER M3 ;
        RECT  29.988 60.419 30.006 60.456 ;
    END
  END b[244]
  PIN b[245]
    DIRECTION OUTPUT ;
    USE SIGNAL ;
    PORT
      LAYER M3 ;
        RECT  30.06 60.419 30.078 60.456 ;
    END
  END b[245]
  PIN b[246]
    DIRECTION OUTPUT ;
    USE SIGNAL ;
    PORT
      LAYER M3 ;
        RECT  30.132 60.419 30.15 60.456 ;
    END
  END b[246]
  PIN b[247]
    DIRECTION OUTPUT ;
    USE SIGNAL ;
    PORT
      LAYER M3 ;
        RECT  30.204 60.419 30.222 60.456 ;
    END
  END b[247]
  PIN b[248]
    DIRECTION OUTPUT ;
    USE SIGNAL ;
    PORT
      LAYER M3 ;
        RECT  30.276 60.419 30.294 60.456 ;
    END
  END b[248]
  PIN b[249]
    DIRECTION OUTPUT ;
    USE SIGNAL ;
    PORT
      LAYER M3 ;
        RECT  30.348 60.419 30.366 60.456 ;
    END
  END b[249]
  PIN b[24]
    DIRECTION OUTPUT ;
    USE SIGNAL ;
    PORT
      LAYER M5 ;
        RECT  34.896 60.372 34.92 60.456 ;
    END
  END b[24]
  PIN b[250]
    DIRECTION OUTPUT ;
    USE SIGNAL ;
    PORT
      LAYER M3 ;
        RECT  30.42 60.419 30.438 60.456 ;
    END
  END b[250]
  PIN b[251]
    DIRECTION OUTPUT ;
    USE SIGNAL ;
    PORT
      LAYER M3 ;
        RECT  30.492 60.419 30.51 60.456 ;
    END
  END b[251]
  PIN b[252]
    DIRECTION OUTPUT ;
    USE SIGNAL ;
    PORT
      LAYER M3 ;
        RECT  30.564 60.419 30.582 60.456 ;
    END
  END b[252]
  PIN b[253]
    DIRECTION OUTPUT ;
    USE SIGNAL ;
    PORT
      LAYER M3 ;
        RECT  30.636 60.419 30.654 60.456 ;
    END
  END b[253]
  PIN b[254]
    DIRECTION OUTPUT ;
    USE SIGNAL ;
    PORT
      LAYER M3 ;
        RECT  30.708 60.419 30.726 60.456 ;
    END
  END b[254]
  PIN b[255]
    DIRECTION OUTPUT ;
    USE SIGNAL ;
    PORT
      LAYER M3 ;
        RECT  30.78 60.419 30.798 60.456 ;
    END
  END b[255]
  PIN b[256]
    DIRECTION OUTPUT ;
    USE SIGNAL ;
    PORT
      LAYER M5 ;
        RECT  29.52 60.372 29.544 60.456 ;
    END
  END b[256]
  PIN b[257]
    DIRECTION OUTPUT ;
    USE SIGNAL ;
    PORT
      LAYER M5 ;
        RECT  29.616 60.372 29.64 60.456 ;
    END
  END b[257]
  PIN b[258]
    DIRECTION OUTPUT ;
    USE SIGNAL ;
    PORT
      LAYER M5 ;
        RECT  29.712 60.372 29.736 60.456 ;
    END
  END b[258]
  PIN b[259]
    DIRECTION OUTPUT ;
    USE SIGNAL ;
    PORT
      LAYER M5 ;
        RECT  29.808 60.372 29.832 60.456 ;
    END
  END b[259]
  PIN b[25]
    DIRECTION OUTPUT ;
    USE SIGNAL ;
    PORT
      LAYER M5 ;
        RECT  34.992 60.372 35.016 60.456 ;
    END
  END b[25]
  PIN b[260]
    DIRECTION OUTPUT ;
    USE SIGNAL ;
    PORT
      LAYER M5 ;
        RECT  29.904 60.372 29.928 60.456 ;
    END
  END b[260]
  PIN b[261]
    DIRECTION OUTPUT ;
    USE SIGNAL ;
    PORT
      LAYER M5 ;
        RECT  30 60.372 30.024 60.456 ;
    END
  END b[261]
  PIN b[262]
    DIRECTION OUTPUT ;
    USE SIGNAL ;
    PORT
      LAYER M5 ;
        RECT  30.096 60.372 30.12 60.456 ;
    END
  END b[262]
  PIN b[263]
    DIRECTION OUTPUT ;
    USE SIGNAL ;
    PORT
      LAYER M5 ;
        RECT  30.192 60.372 30.216 60.456 ;
    END
  END b[263]
  PIN b[264]
    DIRECTION OUTPUT ;
    USE SIGNAL ;
    PORT
      LAYER M5 ;
        RECT  30.288 60.372 30.312 60.456 ;
    END
  END b[264]
  PIN b[265]
    DIRECTION OUTPUT ;
    USE SIGNAL ;
    PORT
      LAYER M5 ;
        RECT  30.384 60.372 30.408 60.456 ;
    END
  END b[265]
  PIN b[266]
    DIRECTION OUTPUT ;
    USE SIGNAL ;
    PORT
      LAYER M5 ;
        RECT  30.48 60.372 30.504 60.456 ;
    END
  END b[266]
  PIN b[267]
    DIRECTION OUTPUT ;
    USE SIGNAL ;
    PORT
      LAYER M5 ;
        RECT  30.576 60.372 30.6 60.456 ;
    END
  END b[267]
  PIN b[268]
    DIRECTION OUTPUT ;
    USE SIGNAL ;
    PORT
      LAYER M5 ;
        RECT  30.672 60.372 30.696 60.456 ;
    END
  END b[268]
  PIN b[269]
    DIRECTION OUTPUT ;
    USE SIGNAL ;
    PORT
      LAYER M5 ;
        RECT  30.768 60.372 30.792 60.456 ;
    END
  END b[269]
  PIN b[26]
    DIRECTION OUTPUT ;
    USE SIGNAL ;
    PORT
      LAYER M5 ;
        RECT  35.088 60.372 35.112 60.456 ;
    END
  END b[26]
  PIN b[270]
    DIRECTION OUTPUT ;
    USE SIGNAL ;
    PORT
      LAYER M5 ;
        RECT  30.864 60.372 30.888 60.456 ;
    END
  END b[270]
  PIN b[271]
    DIRECTION OUTPUT ;
    USE SIGNAL ;
    PORT
      LAYER M5 ;
        RECT  30.96 60.372 30.984 60.456 ;
    END
  END b[271]
  PIN b[272]
    DIRECTION OUTPUT ;
    USE SIGNAL ;
    PORT
      LAYER M5 ;
        RECT  31.056 60.372 31.08 60.456 ;
    END
  END b[272]
  PIN b[273]
    DIRECTION OUTPUT ;
    USE SIGNAL ;
    PORT
      LAYER M5 ;
        RECT  31.152 60.372 31.176 60.456 ;
    END
  END b[273]
  PIN b[274]
    DIRECTION OUTPUT ;
    USE SIGNAL ;
    PORT
      LAYER M5 ;
        RECT  31.248 60.372 31.272 60.456 ;
    END
  END b[274]
  PIN b[275]
    DIRECTION OUTPUT ;
    USE SIGNAL ;
    PORT
      LAYER M5 ;
        RECT  31.344 60.372 31.368 60.456 ;
    END
  END b[275]
  PIN b[276]
    DIRECTION OUTPUT ;
    USE SIGNAL ;
    PORT
      LAYER M5 ;
        RECT  31.44 60.372 31.464 60.456 ;
    END
  END b[276]
  PIN b[277]
    DIRECTION OUTPUT ;
    USE SIGNAL ;
    PORT
      LAYER M5 ;
        RECT  31.536 60.372 31.56 60.456 ;
    END
  END b[277]
  PIN b[278]
    DIRECTION OUTPUT ;
    USE SIGNAL ;
    PORT
      LAYER M5 ;
        RECT  31.632 60.372 31.656 60.456 ;
    END
  END b[278]
  PIN b[279]
    DIRECTION OUTPUT ;
    USE SIGNAL ;
    PORT
      LAYER M5 ;
        RECT  31.728 60.372 31.752 60.456 ;
    END
  END b[279]
  PIN b[27]
    DIRECTION OUTPUT ;
    USE SIGNAL ;
    PORT
      LAYER M5 ;
        RECT  35.184 60.372 35.208 60.456 ;
    END
  END b[27]
  PIN b[280]
    DIRECTION OUTPUT ;
    USE SIGNAL ;
    PORT
      LAYER M5 ;
        RECT  31.824 60.372 31.848 60.456 ;
    END
  END b[280]
  PIN b[281]
    DIRECTION OUTPUT ;
    USE SIGNAL ;
    PORT
      LAYER M5 ;
        RECT  31.92 60.372 31.944 60.456 ;
    END
  END b[281]
  PIN b[282]
    DIRECTION OUTPUT ;
    USE SIGNAL ;
    PORT
      LAYER M5 ;
        RECT  32.016 60.372 32.04 60.456 ;
    END
  END b[282]
  PIN b[283]
    DIRECTION OUTPUT ;
    USE SIGNAL ;
    PORT
      LAYER M5 ;
        RECT  32.112 60.372 32.136 60.456 ;
    END
  END b[283]
  PIN b[284]
    DIRECTION OUTPUT ;
    USE SIGNAL ;
    PORT
      LAYER M5 ;
        RECT  32.208 60.372 32.232 60.456 ;
    END
  END b[284]
  PIN b[285]
    DIRECTION OUTPUT ;
    USE SIGNAL ;
    PORT
      LAYER M5 ;
        RECT  32.304 60.372 32.328 60.456 ;
    END
  END b[285]
  PIN b[286]
    DIRECTION OUTPUT ;
    USE SIGNAL ;
    PORT
      LAYER M5 ;
        RECT  32.4 60.372 32.424 60.456 ;
    END
  END b[286]
  PIN b[287]
    DIRECTION OUTPUT ;
    USE SIGNAL ;
    PORT
      LAYER M5 ;
        RECT  32.496 60.372 32.52 60.456 ;
    END
  END b[287]
  PIN b[288]
    DIRECTION OUTPUT ;
    USE SIGNAL ;
    PORT
      LAYER M3 ;
        RECT  33.156 60.419 33.174 60.456 ;
    END
  END b[288]
  PIN b[289]
    DIRECTION OUTPUT ;
    USE SIGNAL ;
    PORT
      LAYER M3 ;
        RECT  33.228 60.419 33.246 60.456 ;
    END
  END b[289]
  PIN b[28]
    DIRECTION OUTPUT ;
    USE SIGNAL ;
    PORT
      LAYER M5 ;
        RECT  35.28 60.372 35.304 60.456 ;
    END
  END b[28]
  PIN b[290]
    DIRECTION OUTPUT ;
    USE SIGNAL ;
    PORT
      LAYER M3 ;
        RECT  33.3 60.419 33.318 60.456 ;
    END
  END b[290]
  PIN b[291]
    DIRECTION OUTPUT ;
    USE SIGNAL ;
    PORT
      LAYER M3 ;
        RECT  33.372 60.419 33.39 60.456 ;
    END
  END b[291]
  PIN b[292]
    DIRECTION OUTPUT ;
    USE SIGNAL ;
    PORT
      LAYER M3 ;
        RECT  33.444 60.419 33.462 60.456 ;
    END
  END b[292]
  PIN b[293]
    DIRECTION OUTPUT ;
    USE SIGNAL ;
    PORT
      LAYER M3 ;
        RECT  33.516 60.419 33.534 60.456 ;
    END
  END b[293]
  PIN b[294]
    DIRECTION OUTPUT ;
    USE SIGNAL ;
    PORT
      LAYER M3 ;
        RECT  33.588 60.419 33.606 60.456 ;
    END
  END b[294]
  PIN b[295]
    DIRECTION OUTPUT ;
    USE SIGNAL ;
    PORT
      LAYER M3 ;
        RECT  33.66 60.419 33.678 60.456 ;
    END
  END b[295]
  PIN b[296]
    DIRECTION OUTPUT ;
    USE SIGNAL ;
    PORT
      LAYER M3 ;
        RECT  33.732 60.419 33.75 60.456 ;
    END
  END b[296]
  PIN b[297]
    DIRECTION OUTPUT ;
    USE SIGNAL ;
    PORT
      LAYER M3 ;
        RECT  33.804 60.419 33.822 60.456 ;
    END
  END b[297]
  PIN b[298]
    DIRECTION OUTPUT ;
    USE SIGNAL ;
    PORT
      LAYER M3 ;
        RECT  33.876 60.419 33.894 60.456 ;
    END
  END b[298]
  PIN b[299]
    DIRECTION OUTPUT ;
    USE SIGNAL ;
    PORT
      LAYER M3 ;
        RECT  33.948 60.419 33.966 60.456 ;
    END
  END b[299]
  PIN b[29]
    DIRECTION OUTPUT ;
    USE SIGNAL ;
    PORT
      LAYER M5 ;
        RECT  35.376 60.372 35.4 60.456 ;
    END
  END b[29]
  PIN b[2]
    DIRECTION OUTPUT ;
    USE SIGNAL ;
    PORT
      LAYER M5 ;
        RECT  32.784 60.372 32.808 60.456 ;
    END
  END b[2]
  PIN b[300]
    DIRECTION OUTPUT ;
    USE SIGNAL ;
    PORT
      LAYER M3 ;
        RECT  34.02 60.419 34.038 60.456 ;
    END
  END b[300]
  PIN b[301]
    DIRECTION OUTPUT ;
    USE SIGNAL ;
    PORT
      LAYER M3 ;
        RECT  34.092 60.419 34.11 60.456 ;
    END
  END b[301]
  PIN b[302]
    DIRECTION OUTPUT ;
    USE SIGNAL ;
    PORT
      LAYER M3 ;
        RECT  34.164 60.419 34.182 60.456 ;
    END
  END b[302]
  PIN b[303]
    DIRECTION OUTPUT ;
    USE SIGNAL ;
    PORT
      LAYER M3 ;
        RECT  34.236 60.419 34.254 60.456 ;
    END
  END b[303]
  PIN b[304]
    DIRECTION OUTPUT ;
    USE SIGNAL ;
    PORT
      LAYER M3 ;
        RECT  34.308 60.419 34.326 60.456 ;
    END
  END b[304]
  PIN b[305]
    DIRECTION OUTPUT ;
    USE SIGNAL ;
    PORT
      LAYER M3 ;
        RECT  34.38 60.419 34.398 60.456 ;
    END
  END b[305]
  PIN b[306]
    DIRECTION OUTPUT ;
    USE SIGNAL ;
    PORT
      LAYER M3 ;
        RECT  34.452 60.419 34.47 60.456 ;
    END
  END b[306]
  PIN b[307]
    DIRECTION OUTPUT ;
    USE SIGNAL ;
    PORT
      LAYER M3 ;
        RECT  34.524 60.419 34.542 60.456 ;
    END
  END b[307]
  PIN b[308]
    DIRECTION OUTPUT ;
    USE SIGNAL ;
    PORT
      LAYER M3 ;
        RECT  34.596 60.419 34.614 60.456 ;
    END
  END b[308]
  PIN b[309]
    DIRECTION OUTPUT ;
    USE SIGNAL ;
    PORT
      LAYER M3 ;
        RECT  34.668 60.419 34.686 60.456 ;
    END
  END b[309]
  PIN b[30]
    DIRECTION OUTPUT ;
    USE SIGNAL ;
    PORT
      LAYER M5 ;
        RECT  35.472 60.372 35.496 60.456 ;
    END
  END b[30]
  PIN b[310]
    DIRECTION OUTPUT ;
    USE SIGNAL ;
    PORT
      LAYER M3 ;
        RECT  34.74 60.419 34.758 60.456 ;
    END
  END b[310]
  PIN b[311]
    DIRECTION OUTPUT ;
    USE SIGNAL ;
    PORT
      LAYER M3 ;
        RECT  34.812 60.419 34.83 60.456 ;
    END
  END b[311]
  PIN b[312]
    DIRECTION OUTPUT ;
    USE SIGNAL ;
    PORT
      LAYER M3 ;
        RECT  34.884 60.419 34.902 60.456 ;
    END
  END b[312]
  PIN b[313]
    DIRECTION OUTPUT ;
    USE SIGNAL ;
    PORT
      LAYER M3 ;
        RECT  34.956 60.419 34.974 60.456 ;
    END
  END b[313]
  PIN b[314]
    DIRECTION OUTPUT ;
    USE SIGNAL ;
    PORT
      LAYER M3 ;
        RECT  35.028 60.419 35.046 60.456 ;
    END
  END b[314]
  PIN b[315]
    DIRECTION OUTPUT ;
    USE SIGNAL ;
    PORT
      LAYER M3 ;
        RECT  35.1 60.419 35.118 60.456 ;
    END
  END b[315]
  PIN b[316]
    DIRECTION OUTPUT ;
    USE SIGNAL ;
    PORT
      LAYER M3 ;
        RECT  35.172 60.419 35.19 60.456 ;
    END
  END b[316]
  PIN b[317]
    DIRECTION OUTPUT ;
    USE SIGNAL ;
    PORT
      LAYER M3 ;
        RECT  35.244 60.419 35.262 60.456 ;
    END
  END b[317]
  PIN b[318]
    DIRECTION OUTPUT ;
    USE SIGNAL ;
    PORT
      LAYER M3 ;
        RECT  35.316 60.419 35.334 60.456 ;
    END
  END b[318]
  PIN b[319]
    DIRECTION OUTPUT ;
    USE SIGNAL ;
    PORT
      LAYER M3 ;
        RECT  35.388 60.419 35.406 60.456 ;
    END
  END b[319]
  PIN b[31]
    DIRECTION OUTPUT ;
    USE SIGNAL ;
    PORT
      LAYER M5 ;
        RECT  35.568 60.372 35.592 60.456 ;
    END
  END b[31]
  PIN b[320]
    DIRECTION OUTPUT ;
    USE SIGNAL ;
    PORT
      LAYER M3 ;
        RECT  40.644 60.419 40.662 60.456 ;
    END
  END b[320]
  PIN b[321]
    DIRECTION OUTPUT ;
    USE SIGNAL ;
    PORT
      LAYER M3 ;
        RECT  40.716 60.419 40.734 60.456 ;
    END
  END b[321]
  PIN b[322]
    DIRECTION OUTPUT ;
    USE SIGNAL ;
    PORT
      LAYER M3 ;
        RECT  40.788 60.419 40.806 60.456 ;
    END
  END b[322]
  PIN b[323]
    DIRECTION OUTPUT ;
    USE SIGNAL ;
    PORT
      LAYER M3 ;
        RECT  40.86 60.419 40.878 60.456 ;
    END
  END b[323]
  PIN b[324]
    DIRECTION OUTPUT ;
    USE SIGNAL ;
    PORT
      LAYER M3 ;
        RECT  40.932 60.419 40.95 60.456 ;
    END
  END b[324]
  PIN b[325]
    DIRECTION OUTPUT ;
    USE SIGNAL ;
    PORT
      LAYER M3 ;
        RECT  41.004 60.419 41.022 60.456 ;
    END
  END b[325]
  PIN b[326]
    DIRECTION OUTPUT ;
    USE SIGNAL ;
    PORT
      LAYER M3 ;
        RECT  41.076 60.419 41.094 60.456 ;
    END
  END b[326]
  PIN b[327]
    DIRECTION OUTPUT ;
    USE SIGNAL ;
    PORT
      LAYER M3 ;
        RECT  41.148 60.419 41.166 60.456 ;
    END
  END b[327]
  PIN b[328]
    DIRECTION OUTPUT ;
    USE SIGNAL ;
    PORT
      LAYER M3 ;
        RECT  41.22 60.419 41.238 60.456 ;
    END
  END b[328]
  PIN b[329]
    DIRECTION OUTPUT ;
    USE SIGNAL ;
    PORT
      LAYER M3 ;
        RECT  41.292 60.419 41.31 60.456 ;
    END
  END b[329]
  PIN b[32]
    DIRECTION OUTPUT ;
    USE SIGNAL ;
    PORT
      LAYER M3 ;
        RECT  26.244 60.419 26.262 60.456 ;
    END
  END b[32]
  PIN b[330]
    DIRECTION OUTPUT ;
    USE SIGNAL ;
    PORT
      LAYER M3 ;
        RECT  41.364 60.419 41.382 60.456 ;
    END
  END b[330]
  PIN b[331]
    DIRECTION OUTPUT ;
    USE SIGNAL ;
    PORT
      LAYER M3 ;
        RECT  41.436 60.419 41.454 60.456 ;
    END
  END b[331]
  PIN b[332]
    DIRECTION OUTPUT ;
    USE SIGNAL ;
    PORT
      LAYER M3 ;
        RECT  41.508 60.419 41.526 60.456 ;
    END
  END b[332]
  PIN b[333]
    DIRECTION OUTPUT ;
    USE SIGNAL ;
    PORT
      LAYER M3 ;
        RECT  41.58 60.419 41.598 60.456 ;
    END
  END b[333]
  PIN b[334]
    DIRECTION OUTPUT ;
    USE SIGNAL ;
    PORT
      LAYER M3 ;
        RECT  41.652 60.419 41.67 60.456 ;
    END
  END b[334]
  PIN b[335]
    DIRECTION OUTPUT ;
    USE SIGNAL ;
    PORT
      LAYER M3 ;
        RECT  41.724 60.419 41.742 60.456 ;
    END
  END b[335]
  PIN b[336]
    DIRECTION OUTPUT ;
    USE SIGNAL ;
    PORT
      LAYER M3 ;
        RECT  41.796 60.419 41.814 60.456 ;
    END
  END b[336]
  PIN b[337]
    DIRECTION OUTPUT ;
    USE SIGNAL ;
    PORT
      LAYER M3 ;
        RECT  41.868 60.419 41.886 60.456 ;
    END
  END b[337]
  PIN b[338]
    DIRECTION OUTPUT ;
    USE SIGNAL ;
    PORT
      LAYER M3 ;
        RECT  41.94 60.419 41.958 60.456 ;
    END
  END b[338]
  PIN b[339]
    DIRECTION OUTPUT ;
    USE SIGNAL ;
    PORT
      LAYER M3 ;
        RECT  42.012 60.419 42.03 60.456 ;
    END
  END b[339]
  PIN b[33]
    DIRECTION OUTPUT ;
    USE SIGNAL ;
    PORT
      LAYER M3 ;
        RECT  26.316 60.419 26.334 60.456 ;
    END
  END b[33]
  PIN b[340]
    DIRECTION OUTPUT ;
    USE SIGNAL ;
    PORT
      LAYER M3 ;
        RECT  42.084 60.419 42.102 60.456 ;
    END
  END b[340]
  PIN b[341]
    DIRECTION OUTPUT ;
    USE SIGNAL ;
    PORT
      LAYER M3 ;
        RECT  42.156 60.419 42.174 60.456 ;
    END
  END b[341]
  PIN b[342]
    DIRECTION OUTPUT ;
    USE SIGNAL ;
    PORT
      LAYER M3 ;
        RECT  42.228 60.419 42.246 60.456 ;
    END
  END b[342]
  PIN b[343]
    DIRECTION OUTPUT ;
    USE SIGNAL ;
    PORT
      LAYER M3 ;
        RECT  42.3 60.419 42.318 60.456 ;
    END
  END b[343]
  PIN b[344]
    DIRECTION OUTPUT ;
    USE SIGNAL ;
    PORT
      LAYER M3 ;
        RECT  42.372 60.419 42.39 60.456 ;
    END
  END b[344]
  PIN b[345]
    DIRECTION OUTPUT ;
    USE SIGNAL ;
    PORT
      LAYER M3 ;
        RECT  42.444 60.419 42.462 60.456 ;
    END
  END b[345]
  PIN b[346]
    DIRECTION OUTPUT ;
    USE SIGNAL ;
    PORT
      LAYER M3 ;
        RECT  42.516 60.419 42.534 60.456 ;
    END
  END b[346]
  PIN b[347]
    DIRECTION OUTPUT ;
    USE SIGNAL ;
    PORT
      LAYER M3 ;
        RECT  42.588 60.419 42.606 60.456 ;
    END
  END b[347]
  PIN b[348]
    DIRECTION OUTPUT ;
    USE SIGNAL ;
    PORT
      LAYER M3 ;
        RECT  42.66 60.419 42.678 60.456 ;
    END
  END b[348]
  PIN b[349]
    DIRECTION OUTPUT ;
    USE SIGNAL ;
    PORT
      LAYER M3 ;
        RECT  42.732 60.419 42.75 60.456 ;
    END
  END b[349]
  PIN b[34]
    DIRECTION OUTPUT ;
    USE SIGNAL ;
    PORT
      LAYER M3 ;
        RECT  26.388 60.419 26.406 60.456 ;
    END
  END b[34]
  PIN b[350]
    DIRECTION OUTPUT ;
    USE SIGNAL ;
    PORT
      LAYER M3 ;
        RECT  42.804 60.419 42.822 60.456 ;
    END
  END b[350]
  PIN b[351]
    DIRECTION OUTPUT ;
    USE SIGNAL ;
    PORT
      LAYER M3 ;
        RECT  42.876 60.419 42.894 60.456 ;
    END
  END b[351]
  PIN b[352]
    DIRECTION OUTPUT ;
    USE SIGNAL ;
    PORT
      LAYER M3 ;
        RECT  30.852 60.419 30.87 60.456 ;
    END
  END b[352]
  PIN b[353]
    DIRECTION OUTPUT ;
    USE SIGNAL ;
    PORT
      LAYER M3 ;
        RECT  30.924 60.419 30.942 60.456 ;
    END
  END b[353]
  PIN b[354]
    DIRECTION OUTPUT ;
    USE SIGNAL ;
    PORT
      LAYER M3 ;
        RECT  30.996 60.419 31.014 60.456 ;
    END
  END b[354]
  PIN b[355]
    DIRECTION OUTPUT ;
    USE SIGNAL ;
    PORT
      LAYER M3 ;
        RECT  31.068 60.419 31.086 60.456 ;
    END
  END b[355]
  PIN b[356]
    DIRECTION OUTPUT ;
    USE SIGNAL ;
    PORT
      LAYER M3 ;
        RECT  31.14 60.419 31.158 60.456 ;
    END
  END b[356]
  PIN b[357]
    DIRECTION OUTPUT ;
    USE SIGNAL ;
    PORT
      LAYER M3 ;
        RECT  31.212 60.419 31.23 60.456 ;
    END
  END b[357]
  PIN b[358]
    DIRECTION OUTPUT ;
    USE SIGNAL ;
    PORT
      LAYER M3 ;
        RECT  31.284 60.419 31.302 60.456 ;
    END
  END b[358]
  PIN b[359]
    DIRECTION OUTPUT ;
    USE SIGNAL ;
    PORT
      LAYER M3 ;
        RECT  31.356 60.419 31.374 60.456 ;
    END
  END b[359]
  PIN b[35]
    DIRECTION OUTPUT ;
    USE SIGNAL ;
    PORT
      LAYER M3 ;
        RECT  26.46 60.419 26.478 60.456 ;
    END
  END b[35]
  PIN b[360]
    DIRECTION OUTPUT ;
    USE SIGNAL ;
    PORT
      LAYER M3 ;
        RECT  31.428 60.419 31.446 60.456 ;
    END
  END b[360]
  PIN b[361]
    DIRECTION OUTPUT ;
    USE SIGNAL ;
    PORT
      LAYER M3 ;
        RECT  31.5 60.419 31.518 60.456 ;
    END
  END b[361]
  PIN b[362]
    DIRECTION OUTPUT ;
    USE SIGNAL ;
    PORT
      LAYER M3 ;
        RECT  31.572 60.419 31.59 60.456 ;
    END
  END b[362]
  PIN b[363]
    DIRECTION OUTPUT ;
    USE SIGNAL ;
    PORT
      LAYER M3 ;
        RECT  31.644 60.419 31.662 60.456 ;
    END
  END b[363]
  PIN b[364]
    DIRECTION OUTPUT ;
    USE SIGNAL ;
    PORT
      LAYER M3 ;
        RECT  31.716 60.419 31.734 60.456 ;
    END
  END b[364]
  PIN b[365]
    DIRECTION OUTPUT ;
    USE SIGNAL ;
    PORT
      LAYER M3 ;
        RECT  31.788 60.419 31.806 60.456 ;
    END
  END b[365]
  PIN b[366]
    DIRECTION OUTPUT ;
    USE SIGNAL ;
    PORT
      LAYER M3 ;
        RECT  31.86 60.419 31.878 60.456 ;
    END
  END b[366]
  PIN b[367]
    DIRECTION OUTPUT ;
    USE SIGNAL ;
    PORT
      LAYER M3 ;
        RECT  31.932 60.419 31.95 60.456 ;
    END
  END b[367]
  PIN b[368]
    DIRECTION OUTPUT ;
    USE SIGNAL ;
    PORT
      LAYER M3 ;
        RECT  32.004 60.419 32.022 60.456 ;
    END
  END b[368]
  PIN b[369]
    DIRECTION OUTPUT ;
    USE SIGNAL ;
    PORT
      LAYER M3 ;
        RECT  32.076 60.419 32.094 60.456 ;
    END
  END b[369]
  PIN b[36]
    DIRECTION OUTPUT ;
    USE SIGNAL ;
    PORT
      LAYER M3 ;
        RECT  26.532 60.419 26.55 60.456 ;
    END
  END b[36]
  PIN b[370]
    DIRECTION OUTPUT ;
    USE SIGNAL ;
    PORT
      LAYER M3 ;
        RECT  32.148 60.419 32.166 60.456 ;
    END
  END b[370]
  PIN b[371]
    DIRECTION OUTPUT ;
    USE SIGNAL ;
    PORT
      LAYER M3 ;
        RECT  32.22 60.419 32.238 60.456 ;
    END
  END b[371]
  PIN b[372]
    DIRECTION OUTPUT ;
    USE SIGNAL ;
    PORT
      LAYER M3 ;
        RECT  32.292 60.419 32.31 60.456 ;
    END
  END b[372]
  PIN b[373]
    DIRECTION OUTPUT ;
    USE SIGNAL ;
    PORT
      LAYER M3 ;
        RECT  32.364 60.419 32.382 60.456 ;
    END
  END b[373]
  PIN b[374]
    DIRECTION OUTPUT ;
    USE SIGNAL ;
    PORT
      LAYER M3 ;
        RECT  32.436 60.419 32.454 60.456 ;
    END
  END b[374]
  PIN b[375]
    DIRECTION OUTPUT ;
    USE SIGNAL ;
    PORT
      LAYER M3 ;
        RECT  32.508 60.419 32.526 60.456 ;
    END
  END b[375]
  PIN b[376]
    DIRECTION OUTPUT ;
    USE SIGNAL ;
    PORT
      LAYER M3 ;
        RECT  32.58 60.419 32.598 60.456 ;
    END
  END b[376]
  PIN b[377]
    DIRECTION OUTPUT ;
    USE SIGNAL ;
    PORT
      LAYER M3 ;
        RECT  32.652 60.419 32.67 60.456 ;
    END
  END b[377]
  PIN b[378]
    DIRECTION OUTPUT ;
    USE SIGNAL ;
    PORT
      LAYER M3 ;
        RECT  32.724 60.419 32.742 60.456 ;
    END
  END b[378]
  PIN b[379]
    DIRECTION OUTPUT ;
    USE SIGNAL ;
    PORT
      LAYER M3 ;
        RECT  32.796 60.419 32.814 60.456 ;
    END
  END b[379]
  PIN b[37]
    DIRECTION OUTPUT ;
    USE SIGNAL ;
    PORT
      LAYER M3 ;
        RECT  26.604 60.419 26.622 60.456 ;
    END
  END b[37]
  PIN b[380]
    DIRECTION OUTPUT ;
    USE SIGNAL ;
    PORT
      LAYER M3 ;
        RECT  32.868 60.419 32.886 60.456 ;
    END
  END b[380]
  PIN b[381]
    DIRECTION OUTPUT ;
    USE SIGNAL ;
    PORT
      LAYER M3 ;
        RECT  32.94 60.419 32.958 60.456 ;
    END
  END b[381]
  PIN b[382]
    DIRECTION OUTPUT ;
    USE SIGNAL ;
    PORT
      LAYER M3 ;
        RECT  33.012 60.419 33.03 60.456 ;
    END
  END b[382]
  PIN b[383]
    DIRECTION OUTPUT ;
    USE SIGNAL ;
    PORT
      LAYER M3 ;
        RECT  33.084 60.419 33.102 60.456 ;
    END
  END b[383]
  PIN b[384]
    DIRECTION OUTPUT ;
    USE SIGNAL ;
    PORT
      LAYER M3 ;
        RECT  23.94 60.419 23.958 60.456 ;
    END
  END b[384]
  PIN b[385]
    DIRECTION OUTPUT ;
    USE SIGNAL ;
    PORT
      LAYER M3 ;
        RECT  24.012 60.419 24.03 60.456 ;
    END
  END b[385]
  PIN b[386]
    DIRECTION OUTPUT ;
    USE SIGNAL ;
    PORT
      LAYER M3 ;
        RECT  24.084 60.419 24.102 60.456 ;
    END
  END b[386]
  PIN b[387]
    DIRECTION OUTPUT ;
    USE SIGNAL ;
    PORT
      LAYER M3 ;
        RECT  24.156 60.419 24.174 60.456 ;
    END
  END b[387]
  PIN b[388]
    DIRECTION OUTPUT ;
    USE SIGNAL ;
    PORT
      LAYER M3 ;
        RECT  24.228 60.419 24.246 60.456 ;
    END
  END b[388]
  PIN b[389]
    DIRECTION OUTPUT ;
    USE SIGNAL ;
    PORT
      LAYER M3 ;
        RECT  24.3 60.419 24.318 60.456 ;
    END
  END b[389]
  PIN b[38]
    DIRECTION OUTPUT ;
    USE SIGNAL ;
    PORT
      LAYER M3 ;
        RECT  26.676 60.419 26.694 60.456 ;
    END
  END b[38]
  PIN b[390]
    DIRECTION OUTPUT ;
    USE SIGNAL ;
    PORT
      LAYER M3 ;
        RECT  24.372 60.419 24.39 60.456 ;
    END
  END b[390]
  PIN b[391]
    DIRECTION OUTPUT ;
    USE SIGNAL ;
    PORT
      LAYER M3 ;
        RECT  24.444 60.419 24.462 60.456 ;
    END
  END b[391]
  PIN b[392]
    DIRECTION OUTPUT ;
    USE SIGNAL ;
    PORT
      LAYER M3 ;
        RECT  24.516 60.419 24.534 60.456 ;
    END
  END b[392]
  PIN b[393]
    DIRECTION OUTPUT ;
    USE SIGNAL ;
    PORT
      LAYER M3 ;
        RECT  24.588 60.419 24.606 60.456 ;
    END
  END b[393]
  PIN b[394]
    DIRECTION OUTPUT ;
    USE SIGNAL ;
    PORT
      LAYER M3 ;
        RECT  24.66 60.419 24.678 60.456 ;
    END
  END b[394]
  PIN b[395]
    DIRECTION OUTPUT ;
    USE SIGNAL ;
    PORT
      LAYER M3 ;
        RECT  24.732 60.419 24.75 60.456 ;
    END
  END b[395]
  PIN b[396]
    DIRECTION OUTPUT ;
    USE SIGNAL ;
    PORT
      LAYER M3 ;
        RECT  24.804 60.419 24.822 60.456 ;
    END
  END b[396]
  PIN b[397]
    DIRECTION OUTPUT ;
    USE SIGNAL ;
    PORT
      LAYER M3 ;
        RECT  24.876 60.419 24.894 60.456 ;
    END
  END b[397]
  PIN b[398]
    DIRECTION OUTPUT ;
    USE SIGNAL ;
    PORT
      LAYER M3 ;
        RECT  24.948 60.419 24.966 60.456 ;
    END
  END b[398]
  PIN b[399]
    DIRECTION OUTPUT ;
    USE SIGNAL ;
    PORT
      LAYER M3 ;
        RECT  25.02 60.419 25.038 60.456 ;
    END
  END b[399]
  PIN b[39]
    DIRECTION OUTPUT ;
    USE SIGNAL ;
    PORT
      LAYER M3 ;
        RECT  26.748 60.419 26.766 60.456 ;
    END
  END b[39]
  PIN b[3]
    DIRECTION OUTPUT ;
    USE SIGNAL ;
    PORT
      LAYER M5 ;
        RECT  32.88 60.372 32.904 60.456 ;
    END
  END b[3]
  PIN b[400]
    DIRECTION OUTPUT ;
    USE SIGNAL ;
    PORT
      LAYER M3 ;
        RECT  25.092 60.419 25.11 60.456 ;
    END
  END b[400]
  PIN b[401]
    DIRECTION OUTPUT ;
    USE SIGNAL ;
    PORT
      LAYER M3 ;
        RECT  25.164 60.419 25.182 60.456 ;
    END
  END b[401]
  PIN b[402]
    DIRECTION OUTPUT ;
    USE SIGNAL ;
    PORT
      LAYER M3 ;
        RECT  25.236 60.419 25.254 60.456 ;
    END
  END b[402]
  PIN b[403]
    DIRECTION OUTPUT ;
    USE SIGNAL ;
    PORT
      LAYER M3 ;
        RECT  25.308 60.419 25.326 60.456 ;
    END
  END b[403]
  PIN b[404]
    DIRECTION OUTPUT ;
    USE SIGNAL ;
    PORT
      LAYER M3 ;
        RECT  25.38 60.419 25.398 60.456 ;
    END
  END b[404]
  PIN b[405]
    DIRECTION OUTPUT ;
    USE SIGNAL ;
    PORT
      LAYER M3 ;
        RECT  25.452 60.419 25.47 60.456 ;
    END
  END b[405]
  PIN b[406]
    DIRECTION OUTPUT ;
    USE SIGNAL ;
    PORT
      LAYER M3 ;
        RECT  25.524 60.419 25.542 60.456 ;
    END
  END b[406]
  PIN b[407]
    DIRECTION OUTPUT ;
    USE SIGNAL ;
    PORT
      LAYER M3 ;
        RECT  25.596 60.419 25.614 60.456 ;
    END
  END b[407]
  PIN b[408]
    DIRECTION OUTPUT ;
    USE SIGNAL ;
    PORT
      LAYER M3 ;
        RECT  25.668 60.419 25.686 60.456 ;
    END
  END b[408]
  PIN b[409]
    DIRECTION OUTPUT ;
    USE SIGNAL ;
    PORT
      LAYER M3 ;
        RECT  25.74 60.419 25.758 60.456 ;
    END
  END b[409]
  PIN b[40]
    DIRECTION OUTPUT ;
    USE SIGNAL ;
    PORT
      LAYER M3 ;
        RECT  26.82 60.419 26.838 60.456 ;
    END
  END b[40]
  PIN b[410]
    DIRECTION OUTPUT ;
    USE SIGNAL ;
    PORT
      LAYER M3 ;
        RECT  25.812 60.419 25.83 60.456 ;
    END
  END b[410]
  PIN b[411]
    DIRECTION OUTPUT ;
    USE SIGNAL ;
    PORT
      LAYER M3 ;
        RECT  25.884 60.419 25.902 60.456 ;
    END
  END b[411]
  PIN b[412]
    DIRECTION OUTPUT ;
    USE SIGNAL ;
    PORT
      LAYER M3 ;
        RECT  25.956 60.419 25.974 60.456 ;
    END
  END b[412]
  PIN b[413]
    DIRECTION OUTPUT ;
    USE SIGNAL ;
    PORT
      LAYER M3 ;
        RECT  26.028 60.419 26.046 60.456 ;
    END
  END b[413]
  PIN b[414]
    DIRECTION OUTPUT ;
    USE SIGNAL ;
    PORT
      LAYER M3 ;
        RECT  26.1 60.419 26.118 60.456 ;
    END
  END b[414]
  PIN b[415]
    DIRECTION OUTPUT ;
    USE SIGNAL ;
    PORT
      LAYER M3 ;
        RECT  26.172 60.419 26.19 60.456 ;
    END
  END b[415]
  PIN b[416]
    DIRECTION OUTPUT ;
    USE SIGNAL ;
    PORT
      LAYER M3 ;
        RECT  38.34 60.419 38.358 60.456 ;
    END
  END b[416]
  PIN b[417]
    DIRECTION OUTPUT ;
    USE SIGNAL ;
    PORT
      LAYER M3 ;
        RECT  38.412 60.419 38.43 60.456 ;
    END
  END b[417]
  PIN b[418]
    DIRECTION OUTPUT ;
    USE SIGNAL ;
    PORT
      LAYER M3 ;
        RECT  38.484 60.419 38.502 60.456 ;
    END
  END b[418]
  PIN b[419]
    DIRECTION OUTPUT ;
    USE SIGNAL ;
    PORT
      LAYER M3 ;
        RECT  38.556 60.419 38.574 60.456 ;
    END
  END b[419]
  PIN b[41]
    DIRECTION OUTPUT ;
    USE SIGNAL ;
    PORT
      LAYER M3 ;
        RECT  26.892 60.419 26.91 60.456 ;
    END
  END b[41]
  PIN b[420]
    DIRECTION OUTPUT ;
    USE SIGNAL ;
    PORT
      LAYER M3 ;
        RECT  38.628 60.419 38.646 60.456 ;
    END
  END b[420]
  PIN b[421]
    DIRECTION OUTPUT ;
    USE SIGNAL ;
    PORT
      LAYER M3 ;
        RECT  38.7 60.419 38.718 60.456 ;
    END
  END b[421]
  PIN b[422]
    DIRECTION OUTPUT ;
    USE SIGNAL ;
    PORT
      LAYER M3 ;
        RECT  38.772 60.419 38.79 60.456 ;
    END
  END b[422]
  PIN b[423]
    DIRECTION OUTPUT ;
    USE SIGNAL ;
    PORT
      LAYER M3 ;
        RECT  38.844 60.419 38.862 60.456 ;
    END
  END b[423]
  PIN b[424]
    DIRECTION OUTPUT ;
    USE SIGNAL ;
    PORT
      LAYER M3 ;
        RECT  38.916 60.419 38.934 60.456 ;
    END
  END b[424]
  PIN b[425]
    DIRECTION OUTPUT ;
    USE SIGNAL ;
    PORT
      LAYER M3 ;
        RECT  38.988 60.419 39.006 60.456 ;
    END
  END b[425]
  PIN b[426]
    DIRECTION OUTPUT ;
    USE SIGNAL ;
    PORT
      LAYER M3 ;
        RECT  39.06 60.419 39.078 60.456 ;
    END
  END b[426]
  PIN b[427]
    DIRECTION OUTPUT ;
    USE SIGNAL ;
    PORT
      LAYER M3 ;
        RECT  39.132 60.419 39.15 60.456 ;
    END
  END b[427]
  PIN b[428]
    DIRECTION OUTPUT ;
    USE SIGNAL ;
    PORT
      LAYER M3 ;
        RECT  39.204 60.419 39.222 60.456 ;
    END
  END b[428]
  PIN b[429]
    DIRECTION OUTPUT ;
    USE SIGNAL ;
    PORT
      LAYER M3 ;
        RECT  39.276 60.419 39.294 60.456 ;
    END
  END b[429]
  PIN b[42]
    DIRECTION OUTPUT ;
    USE SIGNAL ;
    PORT
      LAYER M3 ;
        RECT  26.964 60.419 26.982 60.456 ;
    END
  END b[42]
  PIN b[430]
    DIRECTION OUTPUT ;
    USE SIGNAL ;
    PORT
      LAYER M3 ;
        RECT  39.348 60.419 39.366 60.456 ;
    END
  END b[430]
  PIN b[431]
    DIRECTION OUTPUT ;
    USE SIGNAL ;
    PORT
      LAYER M3 ;
        RECT  39.42 60.419 39.438 60.456 ;
    END
  END b[431]
  PIN b[432]
    DIRECTION OUTPUT ;
    USE SIGNAL ;
    PORT
      LAYER M3 ;
        RECT  39.492 60.419 39.51 60.456 ;
    END
  END b[432]
  PIN b[433]
    DIRECTION OUTPUT ;
    USE SIGNAL ;
    PORT
      LAYER M3 ;
        RECT  39.564 60.419 39.582 60.456 ;
    END
  END b[433]
  PIN b[434]
    DIRECTION OUTPUT ;
    USE SIGNAL ;
    PORT
      LAYER M3 ;
        RECT  39.636 60.419 39.654 60.456 ;
    END
  END b[434]
  PIN b[435]
    DIRECTION OUTPUT ;
    USE SIGNAL ;
    PORT
      LAYER M3 ;
        RECT  39.708 60.419 39.726 60.456 ;
    END
  END b[435]
  PIN b[436]
    DIRECTION OUTPUT ;
    USE SIGNAL ;
    PORT
      LAYER M3 ;
        RECT  39.78 60.419 39.798 60.456 ;
    END
  END b[436]
  PIN b[437]
    DIRECTION OUTPUT ;
    USE SIGNAL ;
    PORT
      LAYER M3 ;
        RECT  39.852 60.419 39.87 60.456 ;
    END
  END b[437]
  PIN b[438]
    DIRECTION OUTPUT ;
    USE SIGNAL ;
    PORT
      LAYER M3 ;
        RECT  39.924 60.419 39.942 60.456 ;
    END
  END b[438]
  PIN b[439]
    DIRECTION OUTPUT ;
    USE SIGNAL ;
    PORT
      LAYER M3 ;
        RECT  39.996 60.419 40.014 60.456 ;
    END
  END b[439]
  PIN b[43]
    DIRECTION OUTPUT ;
    USE SIGNAL ;
    PORT
      LAYER M3 ;
        RECT  27.036 60.419 27.054 60.456 ;
    END
  END b[43]
  PIN b[440]
    DIRECTION OUTPUT ;
    USE SIGNAL ;
    PORT
      LAYER M3 ;
        RECT  40.068 60.419 40.086 60.456 ;
    END
  END b[440]
  PIN b[441]
    DIRECTION OUTPUT ;
    USE SIGNAL ;
    PORT
      LAYER M3 ;
        RECT  40.14 60.419 40.158 60.456 ;
    END
  END b[441]
  PIN b[442]
    DIRECTION OUTPUT ;
    USE SIGNAL ;
    PORT
      LAYER M3 ;
        RECT  40.212 60.419 40.23 60.456 ;
    END
  END b[442]
  PIN b[443]
    DIRECTION OUTPUT ;
    USE SIGNAL ;
    PORT
      LAYER M3 ;
        RECT  40.284 60.419 40.302 60.456 ;
    END
  END b[443]
  PIN b[444]
    DIRECTION OUTPUT ;
    USE SIGNAL ;
    PORT
      LAYER M3 ;
        RECT  40.356 60.419 40.374 60.456 ;
    END
  END b[444]
  PIN b[445]
    DIRECTION OUTPUT ;
    USE SIGNAL ;
    PORT
      LAYER M3 ;
        RECT  40.428 60.419 40.446 60.456 ;
    END
  END b[445]
  PIN b[446]
    DIRECTION OUTPUT ;
    USE SIGNAL ;
    PORT
      LAYER M3 ;
        RECT  40.5 60.419 40.518 60.456 ;
    END
  END b[446]
  PIN b[447]
    DIRECTION OUTPUT ;
    USE SIGNAL ;
    PORT
      LAYER M3 ;
        RECT  40.572 60.419 40.59 60.456 ;
    END
  END b[447]
  PIN b[448]
    DIRECTION OUTPUT ;
    USE SIGNAL ;
    PORT
      LAYER M3 ;
        RECT  36.036 60.419 36.054 60.456 ;
    END
  END b[448]
  PIN b[449]
    DIRECTION OUTPUT ;
    USE SIGNAL ;
    PORT
      LAYER M3 ;
        RECT  36.108 60.419 36.126 60.456 ;
    END
  END b[449]
  PIN b[44]
    DIRECTION OUTPUT ;
    USE SIGNAL ;
    PORT
      LAYER M3 ;
        RECT  27.108 60.419 27.126 60.456 ;
    END
  END b[44]
  PIN b[450]
    DIRECTION OUTPUT ;
    USE SIGNAL ;
    PORT
      LAYER M3 ;
        RECT  36.18 60.419 36.198 60.456 ;
    END
  END b[450]
  PIN b[451]
    DIRECTION OUTPUT ;
    USE SIGNAL ;
    PORT
      LAYER M3 ;
        RECT  36.252 60.419 36.27 60.456 ;
    END
  END b[451]
  PIN b[452]
    DIRECTION OUTPUT ;
    USE SIGNAL ;
    PORT
      LAYER M3 ;
        RECT  36.324 60.419 36.342 60.456 ;
    END
  END b[452]
  PIN b[453]
    DIRECTION OUTPUT ;
    USE SIGNAL ;
    PORT
      LAYER M3 ;
        RECT  36.396 60.419 36.414 60.456 ;
    END
  END b[453]
  PIN b[454]
    DIRECTION OUTPUT ;
    USE SIGNAL ;
    PORT
      LAYER M3 ;
        RECT  36.468 60.419 36.486 60.456 ;
    END
  END b[454]
  PIN b[455]
    DIRECTION OUTPUT ;
    USE SIGNAL ;
    PORT
      LAYER M3 ;
        RECT  36.54 60.419 36.558 60.456 ;
    END
  END b[455]
  PIN b[456]
    DIRECTION OUTPUT ;
    USE SIGNAL ;
    PORT
      LAYER M3 ;
        RECT  36.612 60.419 36.63 60.456 ;
    END
  END b[456]
  PIN b[457]
    DIRECTION OUTPUT ;
    USE SIGNAL ;
    PORT
      LAYER M3 ;
        RECT  36.684 60.419 36.702 60.456 ;
    END
  END b[457]
  PIN b[458]
    DIRECTION OUTPUT ;
    USE SIGNAL ;
    PORT
      LAYER M3 ;
        RECT  36.756 60.419 36.774 60.456 ;
    END
  END b[458]
  PIN b[459]
    DIRECTION OUTPUT ;
    USE SIGNAL ;
    PORT
      LAYER M3 ;
        RECT  36.828 60.419 36.846 60.456 ;
    END
  END b[459]
  PIN b[45]
    DIRECTION OUTPUT ;
    USE SIGNAL ;
    PORT
      LAYER M3 ;
        RECT  27.18 60.419 27.198 60.456 ;
    END
  END b[45]
  PIN b[460]
    DIRECTION OUTPUT ;
    USE SIGNAL ;
    PORT
      LAYER M3 ;
        RECT  36.9 60.419 36.918 60.456 ;
    END
  END b[460]
  PIN b[461]
    DIRECTION OUTPUT ;
    USE SIGNAL ;
    PORT
      LAYER M3 ;
        RECT  36.972 60.419 36.99 60.456 ;
    END
  END b[461]
  PIN b[462]
    DIRECTION OUTPUT ;
    USE SIGNAL ;
    PORT
      LAYER M3 ;
        RECT  37.044 60.419 37.062 60.456 ;
    END
  END b[462]
  PIN b[463]
    DIRECTION OUTPUT ;
    USE SIGNAL ;
    PORT
      LAYER M3 ;
        RECT  37.116 60.419 37.134 60.456 ;
    END
  END b[463]
  PIN b[464]
    DIRECTION OUTPUT ;
    USE SIGNAL ;
    PORT
      LAYER M3 ;
        RECT  37.188 60.419 37.206 60.456 ;
    END
  END b[464]
  PIN b[465]
    DIRECTION OUTPUT ;
    USE SIGNAL ;
    PORT
      LAYER M3 ;
        RECT  37.26 60.419 37.278 60.456 ;
    END
  END b[465]
  PIN b[466]
    DIRECTION OUTPUT ;
    USE SIGNAL ;
    PORT
      LAYER M3 ;
        RECT  37.332 60.419 37.35 60.456 ;
    END
  END b[466]
  PIN b[467]
    DIRECTION OUTPUT ;
    USE SIGNAL ;
    PORT
      LAYER M3 ;
        RECT  37.404 60.419 37.422 60.456 ;
    END
  END b[467]
  PIN b[468]
    DIRECTION OUTPUT ;
    USE SIGNAL ;
    PORT
      LAYER M3 ;
        RECT  37.476 60.419 37.494 60.456 ;
    END
  END b[468]
  PIN b[469]
    DIRECTION OUTPUT ;
    USE SIGNAL ;
    PORT
      LAYER M3 ;
        RECT  37.548 60.419 37.566 60.456 ;
    END
  END b[469]
  PIN b[46]
    DIRECTION OUTPUT ;
    USE SIGNAL ;
    PORT
      LAYER M3 ;
        RECT  27.252 60.419 27.27 60.456 ;
    END
  END b[46]
  PIN b[470]
    DIRECTION OUTPUT ;
    USE SIGNAL ;
    PORT
      LAYER M3 ;
        RECT  37.62 60.419 37.638 60.456 ;
    END
  END b[470]
  PIN b[471]
    DIRECTION OUTPUT ;
    USE SIGNAL ;
    PORT
      LAYER M3 ;
        RECT  37.692 60.419 37.71 60.456 ;
    END
  END b[471]
  PIN b[472]
    DIRECTION OUTPUT ;
    USE SIGNAL ;
    PORT
      LAYER M3 ;
        RECT  37.764 60.419 37.782 60.456 ;
    END
  END b[472]
  PIN b[473]
    DIRECTION OUTPUT ;
    USE SIGNAL ;
    PORT
      LAYER M3 ;
        RECT  37.836 60.419 37.854 60.456 ;
    END
  END b[473]
  PIN b[474]
    DIRECTION OUTPUT ;
    USE SIGNAL ;
    PORT
      LAYER M3 ;
        RECT  37.908 60.419 37.926 60.456 ;
    END
  END b[474]
  PIN b[475]
    DIRECTION OUTPUT ;
    USE SIGNAL ;
    PORT
      LAYER M3 ;
        RECT  37.98 60.419 37.998 60.456 ;
    END
  END b[475]
  PIN b[476]
    DIRECTION OUTPUT ;
    USE SIGNAL ;
    PORT
      LAYER M3 ;
        RECT  38.052 60.419 38.07 60.456 ;
    END
  END b[476]
  PIN b[477]
    DIRECTION OUTPUT ;
    USE SIGNAL ;
    PORT
      LAYER M3 ;
        RECT  38.124 60.419 38.142 60.456 ;
    END
  END b[477]
  PIN b[478]
    DIRECTION OUTPUT ;
    USE SIGNAL ;
    PORT
      LAYER M3 ;
        RECT  38.196 60.419 38.214 60.456 ;
    END
  END b[478]
  PIN b[479]
    DIRECTION OUTPUT ;
    USE SIGNAL ;
    PORT
      LAYER M3 ;
        RECT  38.268 60.419 38.286 60.456 ;
    END
  END b[479]
  PIN b[47]
    DIRECTION OUTPUT ;
    USE SIGNAL ;
    PORT
      LAYER M3 ;
        RECT  27.324 60.419 27.342 60.456 ;
    END
  END b[47]
  PIN b[480]
    DIRECTION OUTPUT ;
    USE SIGNAL ;
    PORT
      LAYER M3 ;
        RECT  45.252 60.419 45.27 60.456 ;
    END
  END b[480]
  PIN b[481]
    DIRECTION OUTPUT ;
    USE SIGNAL ;
    PORT
      LAYER M3 ;
        RECT  45.324 60.419 45.342 60.456 ;
    END
  END b[481]
  PIN b[482]
    DIRECTION OUTPUT ;
    USE SIGNAL ;
    PORT
      LAYER M3 ;
        RECT  45.396 60.419 45.414 60.456 ;
    END
  END b[482]
  PIN b[483]
    DIRECTION OUTPUT ;
    USE SIGNAL ;
    PORT
      LAYER M3 ;
        RECT  45.468 60.419 45.486 60.456 ;
    END
  END b[483]
  PIN b[484]
    DIRECTION OUTPUT ;
    USE SIGNAL ;
    PORT
      LAYER M3 ;
        RECT  45.54 60.419 45.558 60.456 ;
    END
  END b[484]
  PIN b[485]
    DIRECTION OUTPUT ;
    USE SIGNAL ;
    PORT
      LAYER M3 ;
        RECT  45.612 60.419 45.63 60.456 ;
    END
  END b[485]
  PIN b[486]
    DIRECTION OUTPUT ;
    USE SIGNAL ;
    PORT
      LAYER M3 ;
        RECT  45.684 60.419 45.702 60.456 ;
    END
  END b[486]
  PIN b[487]
    DIRECTION OUTPUT ;
    USE SIGNAL ;
    PORT
      LAYER M3 ;
        RECT  45.756 60.419 45.774 60.456 ;
    END
  END b[487]
  PIN b[488]
    DIRECTION OUTPUT ;
    USE SIGNAL ;
    PORT
      LAYER M3 ;
        RECT  45.828 60.419 45.846 60.456 ;
    END
  END b[488]
  PIN b[489]
    DIRECTION OUTPUT ;
    USE SIGNAL ;
    PORT
      LAYER M3 ;
        RECT  45.9 60.419 45.918 60.456 ;
    END
  END b[489]
  PIN b[48]
    DIRECTION OUTPUT ;
    USE SIGNAL ;
    PORT
      LAYER M3 ;
        RECT  27.396 60.419 27.414 60.456 ;
    END
  END b[48]
  PIN b[490]
    DIRECTION OUTPUT ;
    USE SIGNAL ;
    PORT
      LAYER M3 ;
        RECT  45.972 60.419 45.99 60.456 ;
    END
  END b[490]
  PIN b[491]
    DIRECTION OUTPUT ;
    USE SIGNAL ;
    PORT
      LAYER M3 ;
        RECT  46.044 60.419 46.062 60.456 ;
    END
  END b[491]
  PIN b[492]
    DIRECTION OUTPUT ;
    USE SIGNAL ;
    PORT
      LAYER M3 ;
        RECT  46.116 60.419 46.134 60.456 ;
    END
  END b[492]
  PIN b[493]
    DIRECTION OUTPUT ;
    USE SIGNAL ;
    PORT
      LAYER M3 ;
        RECT  46.188 60.419 46.206 60.456 ;
    END
  END b[493]
  PIN b[494]
    DIRECTION OUTPUT ;
    USE SIGNAL ;
    PORT
      LAYER M3 ;
        RECT  46.26 60.419 46.278 60.456 ;
    END
  END b[494]
  PIN b[495]
    DIRECTION OUTPUT ;
    USE SIGNAL ;
    PORT
      LAYER M3 ;
        RECT  46.332 60.419 46.35 60.456 ;
    END
  END b[495]
  PIN b[496]
    DIRECTION OUTPUT ;
    USE SIGNAL ;
    PORT
      LAYER M3 ;
        RECT  46.404 60.419 46.422 60.456 ;
    END
  END b[496]
  PIN b[497]
    DIRECTION OUTPUT ;
    USE SIGNAL ;
    PORT
      LAYER M3 ;
        RECT  46.476 60.419 46.494 60.456 ;
    END
  END b[497]
  PIN b[498]
    DIRECTION OUTPUT ;
    USE SIGNAL ;
    PORT
      LAYER M3 ;
        RECT  46.548 60.419 46.566 60.456 ;
    END
  END b[498]
  PIN b[499]
    DIRECTION OUTPUT ;
    USE SIGNAL ;
    PORT
      LAYER M3 ;
        RECT  46.62 60.419 46.638 60.456 ;
    END
  END b[499]
  PIN b[49]
    DIRECTION OUTPUT ;
    USE SIGNAL ;
    PORT
      LAYER M3 ;
        RECT  27.468 60.419 27.486 60.456 ;
    END
  END b[49]
  PIN b[4]
    DIRECTION OUTPUT ;
    USE SIGNAL ;
    PORT
      LAYER M5 ;
        RECT  32.976 60.372 33 60.456 ;
    END
  END b[4]
  PIN b[500]
    DIRECTION OUTPUT ;
    USE SIGNAL ;
    PORT
      LAYER M3 ;
        RECT  46.692 60.419 46.71 60.456 ;
    END
  END b[500]
  PIN b[501]
    DIRECTION OUTPUT ;
    USE SIGNAL ;
    PORT
      LAYER M3 ;
        RECT  46.764 60.419 46.782 60.456 ;
    END
  END b[501]
  PIN b[502]
    DIRECTION OUTPUT ;
    USE SIGNAL ;
    PORT
      LAYER M3 ;
        RECT  46.836 60.419 46.854 60.456 ;
    END
  END b[502]
  PIN b[503]
    DIRECTION OUTPUT ;
    USE SIGNAL ;
    PORT
      LAYER M3 ;
        RECT  46.908 60.419 46.926 60.456 ;
    END
  END b[503]
  PIN b[504]
    DIRECTION OUTPUT ;
    USE SIGNAL ;
    PORT
      LAYER M3 ;
        RECT  46.98 60.419 46.998 60.456 ;
    END
  END b[504]
  PIN b[505]
    DIRECTION OUTPUT ;
    USE SIGNAL ;
    PORT
      LAYER M3 ;
        RECT  47.052 60.419 47.07 60.456 ;
    END
  END b[505]
  PIN b[506]
    DIRECTION OUTPUT ;
    USE SIGNAL ;
    PORT
      LAYER M3 ;
        RECT  47.124 60.419 47.142 60.456 ;
    END
  END b[506]
  PIN b[507]
    DIRECTION OUTPUT ;
    USE SIGNAL ;
    PORT
      LAYER M3 ;
        RECT  47.196 60.419 47.214 60.456 ;
    END
  END b[507]
  PIN b[508]
    DIRECTION OUTPUT ;
    USE SIGNAL ;
    PORT
      LAYER M3 ;
        RECT  47.268 60.419 47.286 60.456 ;
    END
  END b[508]
  PIN b[509]
    DIRECTION OUTPUT ;
    USE SIGNAL ;
    PORT
      LAYER M3 ;
        RECT  47.34 60.419 47.358 60.456 ;
    END
  END b[509]
  PIN b[50]
    DIRECTION OUTPUT ;
    USE SIGNAL ;
    PORT
      LAYER M3 ;
        RECT  27.54 60.419 27.558 60.456 ;
    END
  END b[50]
  PIN b[510]
    DIRECTION OUTPUT ;
    USE SIGNAL ;
    PORT
      LAYER M3 ;
        RECT  47.412 60.419 47.43 60.456 ;
    END
  END b[510]
  PIN b[511]
    DIRECTION OUTPUT ;
    USE SIGNAL ;
    PORT
      LAYER M3 ;
        RECT  47.484 60.419 47.502 60.456 ;
    END
  END b[511]
  PIN b[512]
    DIRECTION OUTPUT ;
    USE SIGNAL ;
    PORT
      LAYER M3 ;
        RECT  42.948 60.419 42.966 60.456 ;
    END
  END b[512]
  PIN b[513]
    DIRECTION OUTPUT ;
    USE SIGNAL ;
    PORT
      LAYER M3 ;
        RECT  43.02 60.419 43.038 60.456 ;
    END
  END b[513]
  PIN b[514]
    DIRECTION OUTPUT ;
    USE SIGNAL ;
    PORT
      LAYER M3 ;
        RECT  43.092 60.419 43.11 60.456 ;
    END
  END b[514]
  PIN b[515]
    DIRECTION OUTPUT ;
    USE SIGNAL ;
    PORT
      LAYER M3 ;
        RECT  43.164 60.419 43.182 60.456 ;
    END
  END b[515]
  PIN b[516]
    DIRECTION OUTPUT ;
    USE SIGNAL ;
    PORT
      LAYER M3 ;
        RECT  43.236 60.419 43.254 60.456 ;
    END
  END b[516]
  PIN b[517]
    DIRECTION OUTPUT ;
    USE SIGNAL ;
    PORT
      LAYER M3 ;
        RECT  43.308 60.419 43.326 60.456 ;
    END
  END b[517]
  PIN b[518]
    DIRECTION OUTPUT ;
    USE SIGNAL ;
    PORT
      LAYER M3 ;
        RECT  43.38 60.419 43.398 60.456 ;
    END
  END b[518]
  PIN b[519]
    DIRECTION OUTPUT ;
    USE SIGNAL ;
    PORT
      LAYER M3 ;
        RECT  43.452 60.419 43.47 60.456 ;
    END
  END b[519]
  PIN b[51]
    DIRECTION OUTPUT ;
    USE SIGNAL ;
    PORT
      LAYER M3 ;
        RECT  27.612 60.419 27.63 60.456 ;
    END
  END b[51]
  PIN b[520]
    DIRECTION OUTPUT ;
    USE SIGNAL ;
    PORT
      LAYER M3 ;
        RECT  43.524 60.419 43.542 60.456 ;
    END
  END b[520]
  PIN b[521]
    DIRECTION OUTPUT ;
    USE SIGNAL ;
    PORT
      LAYER M3 ;
        RECT  43.596 60.419 43.614 60.456 ;
    END
  END b[521]
  PIN b[522]
    DIRECTION OUTPUT ;
    USE SIGNAL ;
    PORT
      LAYER M3 ;
        RECT  43.668 60.419 43.686 60.456 ;
    END
  END b[522]
  PIN b[523]
    DIRECTION OUTPUT ;
    USE SIGNAL ;
    PORT
      LAYER M3 ;
        RECT  43.74 60.419 43.758 60.456 ;
    END
  END b[523]
  PIN b[524]
    DIRECTION OUTPUT ;
    USE SIGNAL ;
    PORT
      LAYER M3 ;
        RECT  43.812 60.419 43.83 60.456 ;
    END
  END b[524]
  PIN b[525]
    DIRECTION OUTPUT ;
    USE SIGNAL ;
    PORT
      LAYER M3 ;
        RECT  43.884 60.419 43.902 60.456 ;
    END
  END b[525]
  PIN b[526]
    DIRECTION OUTPUT ;
    USE SIGNAL ;
    PORT
      LAYER M3 ;
        RECT  43.956 60.419 43.974 60.456 ;
    END
  END b[526]
  PIN b[527]
    DIRECTION OUTPUT ;
    USE SIGNAL ;
    PORT
      LAYER M3 ;
        RECT  44.028 60.419 44.046 60.456 ;
    END
  END b[527]
  PIN b[528]
    DIRECTION OUTPUT ;
    USE SIGNAL ;
    PORT
      LAYER M3 ;
        RECT  44.1 60.419 44.118 60.456 ;
    END
  END b[528]
  PIN b[529]
    DIRECTION OUTPUT ;
    USE SIGNAL ;
    PORT
      LAYER M3 ;
        RECT  44.172 60.419 44.19 60.456 ;
    END
  END b[529]
  PIN b[52]
    DIRECTION OUTPUT ;
    USE SIGNAL ;
    PORT
      LAYER M3 ;
        RECT  27.684 60.419 27.702 60.456 ;
    END
  END b[52]
  PIN b[530]
    DIRECTION OUTPUT ;
    USE SIGNAL ;
    PORT
      LAYER M3 ;
        RECT  44.244 60.419 44.262 60.456 ;
    END
  END b[530]
  PIN b[531]
    DIRECTION OUTPUT ;
    USE SIGNAL ;
    PORT
      LAYER M3 ;
        RECT  44.316 60.419 44.334 60.456 ;
    END
  END b[531]
  PIN b[532]
    DIRECTION OUTPUT ;
    USE SIGNAL ;
    PORT
      LAYER M3 ;
        RECT  44.388 60.419 44.406 60.456 ;
    END
  END b[532]
  PIN b[533]
    DIRECTION OUTPUT ;
    USE SIGNAL ;
    PORT
      LAYER M3 ;
        RECT  44.46 60.419 44.478 60.456 ;
    END
  END b[533]
  PIN b[534]
    DIRECTION OUTPUT ;
    USE SIGNAL ;
    PORT
      LAYER M3 ;
        RECT  44.532 60.419 44.55 60.456 ;
    END
  END b[534]
  PIN b[535]
    DIRECTION OUTPUT ;
    USE SIGNAL ;
    PORT
      LAYER M3 ;
        RECT  44.604 60.419 44.622 60.456 ;
    END
  END b[535]
  PIN b[536]
    DIRECTION OUTPUT ;
    USE SIGNAL ;
    PORT
      LAYER M3 ;
        RECT  44.676 60.419 44.694 60.456 ;
    END
  END b[536]
  PIN b[537]
    DIRECTION OUTPUT ;
    USE SIGNAL ;
    PORT
      LAYER M3 ;
        RECT  44.748 60.419 44.766 60.456 ;
    END
  END b[537]
  PIN b[538]
    DIRECTION OUTPUT ;
    USE SIGNAL ;
    PORT
      LAYER M3 ;
        RECT  44.82 60.419 44.838 60.456 ;
    END
  END b[538]
  PIN b[539]
    DIRECTION OUTPUT ;
    USE SIGNAL ;
    PORT
      LAYER M3 ;
        RECT  44.892 60.419 44.91 60.456 ;
    END
  END b[539]
  PIN b[53]
    DIRECTION OUTPUT ;
    USE SIGNAL ;
    PORT
      LAYER M3 ;
        RECT  27.756 60.419 27.774 60.456 ;
    END
  END b[53]
  PIN b[540]
    DIRECTION OUTPUT ;
    USE SIGNAL ;
    PORT
      LAYER M3 ;
        RECT  44.964 60.419 44.982 60.456 ;
    END
  END b[540]
  PIN b[541]
    DIRECTION OUTPUT ;
    USE SIGNAL ;
    PORT
      LAYER M3 ;
        RECT  45.036 60.419 45.054 60.456 ;
    END
  END b[541]
  PIN b[542]
    DIRECTION OUTPUT ;
    USE SIGNAL ;
    PORT
      LAYER M3 ;
        RECT  45.108 60.419 45.126 60.456 ;
    END
  END b[542]
  PIN b[543]
    DIRECTION OUTPUT ;
    USE SIGNAL ;
    PORT
      LAYER M3 ;
        RECT  45.18 60.419 45.198 60.456 ;
    END
  END b[543]
  PIN b[544]
    DIRECTION OUTPUT ;
    USE SIGNAL ;
    PORT
      LAYER M5 ;
        RECT  25.968 60.372 25.992 60.456 ;
    END
  END b[544]
  PIN b[545]
    DIRECTION OUTPUT ;
    USE SIGNAL ;
    PORT
      LAYER M5 ;
        RECT  26.064 60.372 26.088 60.456 ;
    END
  END b[545]
  PIN b[546]
    DIRECTION OUTPUT ;
    USE SIGNAL ;
    PORT
      LAYER M5 ;
        RECT  26.16 60.372 26.184 60.456 ;
    END
  END b[546]
  PIN b[547]
    DIRECTION OUTPUT ;
    USE SIGNAL ;
    PORT
      LAYER M5 ;
        RECT  26.256 60.372 26.28 60.456 ;
    END
  END b[547]
  PIN b[54]
    DIRECTION OUTPUT ;
    USE SIGNAL ;
    PORT
      LAYER M3 ;
        RECT  27.828 60.419 27.846 60.456 ;
    END
  END b[54]
  PIN b[55]
    DIRECTION OUTPUT ;
    USE SIGNAL ;
    PORT
      LAYER M3 ;
        RECT  27.9 60.419 27.918 60.456 ;
    END
  END b[55]
  PIN b[56]
    DIRECTION OUTPUT ;
    USE SIGNAL ;
    PORT
      LAYER M3 ;
        RECT  27.972 60.419 27.99 60.456 ;
    END
  END b[56]
  PIN b[57]
    DIRECTION OUTPUT ;
    USE SIGNAL ;
    PORT
      LAYER M3 ;
        RECT  28.044 60.419 28.062 60.456 ;
    END
  END b[57]
  PIN b[58]
    DIRECTION OUTPUT ;
    USE SIGNAL ;
    PORT
      LAYER M3 ;
        RECT  28.116 60.419 28.134 60.456 ;
    END
  END b[58]
  PIN b[59]
    DIRECTION OUTPUT ;
    USE SIGNAL ;
    PORT
      LAYER M3 ;
        RECT  28.188 60.419 28.206 60.456 ;
    END
  END b[59]
  PIN b[5]
    DIRECTION OUTPUT ;
    USE SIGNAL ;
    PORT
      LAYER M5 ;
        RECT  33.072 60.372 33.096 60.456 ;
    END
  END b[5]
  PIN b[60]
    DIRECTION OUTPUT ;
    USE SIGNAL ;
    PORT
      LAYER M3 ;
        RECT  28.26 60.419 28.278 60.456 ;
    END
  END b[60]
  PIN b[61]
    DIRECTION OUTPUT ;
    USE SIGNAL ;
    PORT
      LAYER M3 ;
        RECT  28.332 60.419 28.35 60.456 ;
    END
  END b[61]
  PIN b[62]
    DIRECTION OUTPUT ;
    USE SIGNAL ;
    PORT
      LAYER M3 ;
        RECT  28.404 60.419 28.422 60.456 ;
    END
  END b[62]
  PIN b[63]
    DIRECTION OUTPUT ;
    USE SIGNAL ;
    PORT
      LAYER M3 ;
        RECT  28.476 60.419 28.494 60.456 ;
    END
  END b[63]
  PIN b[64]
    DIRECTION OUTPUT ;
    USE SIGNAL ;
    PORT
      LAYER M5 ;
        RECT  38.736 60.372 38.76 60.456 ;
    END
  END b[64]
  PIN b[65]
    DIRECTION OUTPUT ;
    USE SIGNAL ;
    PORT
      LAYER M5 ;
        RECT  38.832 60.372 38.856 60.456 ;
    END
  END b[65]
  PIN b[66]
    DIRECTION OUTPUT ;
    USE SIGNAL ;
    PORT
      LAYER M5 ;
        RECT  38.928 60.372 38.952 60.456 ;
    END
  END b[66]
  PIN b[67]
    DIRECTION OUTPUT ;
    USE SIGNAL ;
    PORT
      LAYER M5 ;
        RECT  39.024 60.372 39.048 60.456 ;
    END
  END b[67]
  PIN b[68]
    DIRECTION OUTPUT ;
    USE SIGNAL ;
    PORT
      LAYER M5 ;
        RECT  39.12 60.372 39.144 60.456 ;
    END
  END b[68]
  PIN b[69]
    DIRECTION OUTPUT ;
    USE SIGNAL ;
    PORT
      LAYER M5 ;
        RECT  39.216 60.372 39.24 60.456 ;
    END
  END b[69]
  PIN b[6]
    DIRECTION OUTPUT ;
    USE SIGNAL ;
    PORT
      LAYER M5 ;
        RECT  33.168 60.372 33.192 60.456 ;
    END
  END b[6]
  PIN b[70]
    DIRECTION OUTPUT ;
    USE SIGNAL ;
    PORT
      LAYER M5 ;
        RECT  39.312 60.372 39.336 60.456 ;
    END
  END b[70]
  PIN b[71]
    DIRECTION OUTPUT ;
    USE SIGNAL ;
    PORT
      LAYER M5 ;
        RECT  39.408 60.372 39.432 60.456 ;
    END
  END b[71]
  PIN b[72]
    DIRECTION OUTPUT ;
    USE SIGNAL ;
    PORT
      LAYER M5 ;
        RECT  39.504 60.372 39.528 60.456 ;
    END
  END b[72]
  PIN b[73]
    DIRECTION OUTPUT ;
    USE SIGNAL ;
    PORT
      LAYER M5 ;
        RECT  39.6 60.372 39.624 60.456 ;
    END
  END b[73]
  PIN b[74]
    DIRECTION OUTPUT ;
    USE SIGNAL ;
    PORT
      LAYER M5 ;
        RECT  39.696 60.372 39.72 60.456 ;
    END
  END b[74]
  PIN b[75]
    DIRECTION OUTPUT ;
    USE SIGNAL ;
    PORT
      LAYER M5 ;
        RECT  39.792 60.372 39.816 60.456 ;
    END
  END b[75]
  PIN b[76]
    DIRECTION OUTPUT ;
    USE SIGNAL ;
    PORT
      LAYER M5 ;
        RECT  39.888 60.372 39.912 60.456 ;
    END
  END b[76]
  PIN b[77]
    DIRECTION OUTPUT ;
    USE SIGNAL ;
    PORT
      LAYER M5 ;
        RECT  39.984 60.372 40.008 60.456 ;
    END
  END b[77]
  PIN b[78]
    DIRECTION OUTPUT ;
    USE SIGNAL ;
    PORT
      LAYER M5 ;
        RECT  40.08 60.372 40.104 60.456 ;
    END
  END b[78]
  PIN b[79]
    DIRECTION OUTPUT ;
    USE SIGNAL ;
    PORT
      LAYER M5 ;
        RECT  40.176 60.372 40.2 60.456 ;
    END
  END b[79]
  PIN b[7]
    DIRECTION OUTPUT ;
    USE SIGNAL ;
    PORT
      LAYER M5 ;
        RECT  33.264 60.372 33.288 60.456 ;
    END
  END b[7]
  PIN b[80]
    DIRECTION OUTPUT ;
    USE SIGNAL ;
    PORT
      LAYER M5 ;
        RECT  40.272 60.372 40.296 60.456 ;
    END
  END b[80]
  PIN b[81]
    DIRECTION OUTPUT ;
    USE SIGNAL ;
    PORT
      LAYER M5 ;
        RECT  40.368 60.372 40.392 60.456 ;
    END
  END b[81]
  PIN b[82]
    DIRECTION OUTPUT ;
    USE SIGNAL ;
    PORT
      LAYER M5 ;
        RECT  40.464 60.372 40.488 60.456 ;
    END
  END b[82]
  PIN b[83]
    DIRECTION OUTPUT ;
    USE SIGNAL ;
    PORT
      LAYER M5 ;
        RECT  40.56 60.372 40.584 60.456 ;
    END
  END b[83]
  PIN b[84]
    DIRECTION OUTPUT ;
    USE SIGNAL ;
    PORT
      LAYER M5 ;
        RECT  40.656 60.372 40.68 60.456 ;
    END
  END b[84]
  PIN b[85]
    DIRECTION OUTPUT ;
    USE SIGNAL ;
    PORT
      LAYER M5 ;
        RECT  40.752 60.372 40.776 60.456 ;
    END
  END b[85]
  PIN b[86]
    DIRECTION OUTPUT ;
    USE SIGNAL ;
    PORT
      LAYER M5 ;
        RECT  40.848 60.372 40.872 60.456 ;
    END
  END b[86]
  PIN b[87]
    DIRECTION OUTPUT ;
    USE SIGNAL ;
    PORT
      LAYER M5 ;
        RECT  40.944 60.372 40.968 60.456 ;
    END
  END b[87]
  PIN b[88]
    DIRECTION OUTPUT ;
    USE SIGNAL ;
    PORT
      LAYER M5 ;
        RECT  41.04 60.372 41.064 60.456 ;
    END
  END b[88]
  PIN b[89]
    DIRECTION OUTPUT ;
    USE SIGNAL ;
    PORT
      LAYER M5 ;
        RECT  41.136 60.372 41.16 60.456 ;
    END
  END b[89]
  PIN b[8]
    DIRECTION OUTPUT ;
    USE SIGNAL ;
    PORT
      LAYER M5 ;
        RECT  33.36 60.372 33.384 60.456 ;
    END
  END b[8]
  PIN b[90]
    DIRECTION OUTPUT ;
    USE SIGNAL ;
    PORT
      LAYER M5 ;
        RECT  41.232 60.372 41.256 60.456 ;
    END
  END b[90]
  PIN b[91]
    DIRECTION OUTPUT ;
    USE SIGNAL ;
    PORT
      LAYER M5 ;
        RECT  41.328 60.372 41.352 60.456 ;
    END
  END b[91]
  PIN b[92]
    DIRECTION OUTPUT ;
    USE SIGNAL ;
    PORT
      LAYER M5 ;
        RECT  41.424 60.372 41.448 60.456 ;
    END
  END b[92]
  PIN b[93]
    DIRECTION OUTPUT ;
    USE SIGNAL ;
    PORT
      LAYER M5 ;
        RECT  41.52 60.372 41.544 60.456 ;
    END
  END b[93]
  PIN b[94]
    DIRECTION OUTPUT ;
    USE SIGNAL ;
    PORT
      LAYER M5 ;
        RECT  41.616 60.372 41.64 60.456 ;
    END
  END b[94]
  PIN b[95]
    DIRECTION OUTPUT ;
    USE SIGNAL ;
    PORT
      LAYER M5 ;
        RECT  41.712 60.372 41.736 60.456 ;
    END
  END b[95]
  PIN b[96]
    DIRECTION OUTPUT ;
    USE SIGNAL ;
    PORT
      LAYER M5 ;
        RECT  41.808 60.372 41.832 60.456 ;
    END
  END b[96]
  PIN b[97]
    DIRECTION OUTPUT ;
    USE SIGNAL ;
    PORT
      LAYER M5 ;
        RECT  41.904 60.372 41.928 60.456 ;
    END
  END b[97]
  PIN b[98]
    DIRECTION OUTPUT ;
    USE SIGNAL ;
    PORT
      LAYER M5 ;
        RECT  42 60.372 42.024 60.456 ;
    END
  END b[98]
  PIN b[99]
    DIRECTION OUTPUT ;
    USE SIGNAL ;
    PORT
      LAYER M5 ;
        RECT  42.096 60.372 42.12 60.456 ;
    END
  END b[99]
  PIN b[9]
    DIRECTION OUTPUT ;
    USE SIGNAL ;
    PORT
      LAYER M5 ;
        RECT  33.456 60.372 33.48 60.456 ;
    END
  END b[9]
  PIN ck_o
    DIRECTION OUTPUT ;
    USE SIGNAL ;
    PORT
      LAYER M4 ;
        RECT  64.692 29.904 64.776 29.928 ;
    END
  END ck_o
  PIN ckf
    DIRECTION INPUT ;
    USE SIGNAL ;
    PORT
      LAYER M4 ;
        RECT  64.692 30 64.776 30.024 ;
    END
  END ckf
  PIN ea
    DIRECTION INPUT ;
    USE SIGNAL ;
    PORT
      LAYER M3 ;
        RECT  43.452 0 43.47 0.037 ;
    END
  END ea
  PIN eb
    DIRECTION OUTPUT ;
    USE SIGNAL ;
    PORT
      LAYER M5 ;
        RECT  26.352 60.372 26.376 60.456 ;
    END
  END eb
  PIN VDD
    DIRECTION INOUT ;
    USE POWER ;
    PORT
      LAYER M5 ;
        RECT  61.992 2.151 62.112 58.073 ;
        RECT  59.292 2.151 59.412 58.073 ;
        RECT  56.592 2.151 56.712 58.073 ;
        RECT  53.892 2.151 54.012 58.073 ;
        RECT  51.192 2.151 51.312 58.073 ;
        RECT  48.492 2.151 48.612 58.073 ;
        RECT  45.792 2.151 45.912 58.073 ;
        RECT  43.092 2.151 43.212 58.073 ;
        RECT  40.392 2.151 40.512 58.073 ;
        RECT  37.692 2.151 37.812 58.073 ;
        RECT  34.992 2.151 35.112 58.073 ;
        RECT  32.292 2.151 32.412 58.073 ;
        RECT  29.592 2.151 29.712 58.073 ;
        RECT  26.892 2.151 27.012 58.073 ;
        RECT  24.192 2.151 24.312 58.073 ;
        RECT  21.492 2.151 21.612 58.073 ;
        RECT  18.792 2.151 18.912 58.073 ;
        RECT  16.092 2.151 16.212 58.073 ;
        RECT  13.392 2.151 13.512 58.073 ;
        RECT  10.692 2.151 10.812 58.073 ;
        RECT  7.992 2.151 8.112 58.073 ;
        RECT  5.292 2.151 5.412 58.073 ;
        RECT  2.592 2.151 2.712 58.073 ;
    END
  END VDD
  PIN VSS
    DIRECTION INOUT ;
    USE GROUND ;
    PORT
      LAYER M5 ;
        RECT  61.8 2.137 61.92 58.059 ;
        RECT  59.1 2.137 59.22 58.059 ;
        RECT  56.4 2.137 56.52 58.059 ;
        RECT  53.7 2.137 53.82 58.059 ;
        RECT  51 2.137 51.12 58.059 ;
        RECT  48.3 2.137 48.42 58.059 ;
        RECT  45.6 2.137 45.72 58.059 ;
        RECT  42.9 2.137 43.02 58.059 ;
        RECT  40.2 2.137 40.32 58.059 ;
        RECT  37.5 2.137 37.62 58.059 ;
        RECT  34.8 2.137 34.92 58.059 ;
        RECT  32.1 2.137 32.22 58.059 ;
        RECT  29.4 2.137 29.52 58.059 ;
        RECT  26.7 2.137 26.82 58.059 ;
        RECT  24 2.137 24.12 58.059 ;
        RECT  21.3 2.137 21.42 58.059 ;
        RECT  18.6 2.137 18.72 58.059 ;
        RECT  15.9 2.137 16.02 58.059 ;
        RECT  13.2 2.137 13.32 58.059 ;
        RECT  10.5 2.137 10.62 58.059 ;
        RECT  7.8 2.137 7.92 58.059 ;
        RECT  5.1 2.137 5.22 58.059 ;
        RECT  2.4 2.137 2.52 58.059 ;
    END
  END VSS
  OBS
    LAYER RVTN ;
     RECT  2.16 2.16 62.586 2.295 ;
     RECT  2.16 2.565 62.586 2.835 ;
     RECT  2.16 3.105 62.586 3.375 ;
     RECT  2.16 3.645 62.586 3.915 ;
     RECT  2.16 4.185 62.586 4.455 ;
     RECT  2.16 4.725 62.586 4.995 ;
     RECT  2.16 5.265 62.586 5.535 ;
     RECT  2.16 5.805 62.586 6.075 ;
     RECT  2.16 6.345 62.586 6.615 ;
     RECT  2.16 6.885 62.586 7.155 ;
     RECT  2.16 7.425 62.586 7.695 ;
     RECT  2.16 7.965 62.586 8.235 ;
     RECT  2.16 8.505 62.586 8.775 ;
     RECT  2.16 9.045 62.586 9.315 ;
     RECT  2.16 9.585 62.586 9.855 ;
     RECT  2.16 10.125 62.586 10.395 ;
     RECT  2.16 10.665 62.586 10.935 ;
     RECT  2.16 11.205 62.586 11.475 ;
     RECT  2.16 11.745 62.586 12.015 ;
     RECT  2.16 12.285 62.586 12.555 ;
     RECT  2.16 12.825 62.586 13.095 ;
     RECT  2.16 13.365 62.586 13.635 ;
     RECT  2.16 13.905 62.586 14.175 ;
     RECT  2.16 14.445 62.586 14.715 ;
     RECT  2.16 14.985 62.586 15.255 ;
     RECT  2.16 15.525 62.586 15.795 ;
     RECT  2.16 16.065 62.586 16.335 ;
     RECT  2.16 16.605 62.586 16.875 ;
     RECT  2.16 17.145 62.586 17.415 ;
     RECT  2.16 17.685 62.586 17.955 ;
     RECT  2.16 18.225 62.586 18.495 ;
     RECT  2.16 18.765 62.586 19.035 ;
     RECT  2.16 19.305 62.586 19.575 ;
     RECT  2.16 19.845 62.586 20.115 ;
     RECT  2.16 20.385 62.586 20.655 ;
     RECT  2.16 20.925 62.586 21.195 ;
     RECT  2.16 21.465 62.586 21.735 ;
     RECT  2.16 22.005 62.586 22.275 ;
     RECT  2.16 22.545 62.586 22.815 ;
     RECT  2.16 23.085 62.586 23.355 ;
     RECT  2.16 23.625 62.586 23.895 ;
     RECT  2.16 24.165 62.586 24.435 ;
     RECT  2.16 24.705 62.586 24.975 ;
     RECT  2.16 25.245 62.586 25.515 ;
     RECT  2.16 25.785 62.586 26.055 ;
     RECT  2.16 26.325 62.586 26.595 ;
     RECT  2.16 26.865 62.586 27.135 ;
     RECT  2.16 27.405 62.586 27.675 ;
     RECT  2.16 27.945 62.586 28.215 ;
     RECT  2.16 28.485 62.586 28.755 ;
     RECT  2.16 29.025 62.586 29.295 ;
     RECT  2.16 29.565 62.586 29.835 ;
     RECT  2.16 30.105 62.586 30.375 ;
     RECT  2.16 30.645 62.586 30.915 ;
     RECT  2.16 31.185 62.586 31.455 ;
     RECT  2.16 31.725 62.586 31.995 ;
     RECT  2.16 32.265 62.586 32.535 ;
     RECT  2.16 32.805 62.586 33.075 ;
     RECT  2.16 33.345 62.586 33.615 ;
     RECT  2.16 33.885 62.586 34.155 ;
     RECT  2.16 34.425 62.586 34.695 ;
     RECT  2.16 34.965 62.586 35.235 ;
     RECT  2.16 35.505 62.586 35.775 ;
     RECT  2.16 36.045 62.586 36.315 ;
     RECT  2.16 36.585 62.586 36.855 ;
     RECT  2.16 37.125 62.586 37.395 ;
     RECT  2.16 37.665 62.586 37.935 ;
     RECT  2.16 38.205 62.586 38.475 ;
     RECT  2.16 38.745 62.586 39.015 ;
     RECT  2.16 39.285 62.586 39.555 ;
     RECT  2.16 39.825 62.586 40.095 ;
     RECT  2.16 40.365 62.586 40.635 ;
     RECT  2.16 40.905 62.586 41.175 ;
     RECT  2.16 41.445 62.586 41.715 ;
     RECT  2.16 41.985 62.586 42.255 ;
     RECT  2.16 42.525 62.586 42.795 ;
     RECT  2.16 43.065 62.586 43.335 ;
     RECT  2.16 43.605 62.586 43.875 ;
     RECT  2.16 44.145 62.586 44.415 ;
     RECT  2.16 44.685 62.586 44.955 ;
     RECT  2.16 45.225 62.586 45.495 ;
     RECT  2.16 45.765 62.586 46.035 ;
     RECT  2.16 46.305 62.586 46.575 ;
     RECT  2.16 46.845 62.586 47.115 ;
     RECT  2.16 47.385 62.586 47.655 ;
     RECT  2.16 47.925 62.586 48.195 ;
     RECT  2.16 48.465 62.586 48.735 ;
     RECT  2.16 49.005 62.586 49.275 ;
     RECT  2.16 49.545 62.586 49.815 ;
     RECT  2.16 50.085 62.586 50.355 ;
     RECT  2.16 50.625 62.586 50.895 ;
     RECT  2.16 51.165 62.586 51.435 ;
     RECT  2.16 51.705 62.586 51.975 ;
     RECT  2.16 52.245 62.586 52.515 ;
     RECT  2.16 52.785 62.586 53.055 ;
     RECT  2.16 53.325 62.586 53.595 ;
     RECT  2.16 53.865 62.586 54.135 ;
     RECT  2.16 54.405 62.586 54.675 ;
     RECT  2.16 54.945 62.586 55.215 ;
     RECT  2.16 55.485 62.586 55.755 ;
     RECT  2.16 56.025 62.586 56.295 ;
     RECT  2.16 56.565 62.586 56.835 ;
     RECT  2.16 57.105 62.586 57.375 ;
     RECT  2.16 57.645 62.586 57.915 ;
    LAYER RVTP ;
     RECT  2.16 2.295 62.586 2.565 ;
     RECT  2.16 2.835 62.586 3.105 ;
     RECT  2.16 3.375 62.586 3.645 ;
     RECT  2.16 3.915 62.586 4.185 ;
     RECT  2.16 4.455 62.586 4.725 ;
     RECT  2.16 4.995 62.586 5.265 ;
     RECT  2.16 5.535 62.586 5.805 ;
     RECT  2.16 6.075 62.586 6.345 ;
     RECT  2.16 6.615 62.586 6.885 ;
     RECT  2.16 7.155 62.586 7.425 ;
     RECT  2.16 7.695 62.586 7.965 ;
     RECT  2.16 8.235 62.586 8.505 ;
     RECT  2.16 8.775 62.586 9.045 ;
     RECT  2.16 9.315 62.586 9.585 ;
     RECT  2.16 9.855 62.586 10.125 ;
     RECT  2.16 10.395 62.586 10.665 ;
     RECT  2.16 10.935 62.586 11.205 ;
     RECT  2.16 11.475 62.586 11.745 ;
     RECT  2.16 12.015 62.586 12.285 ;
     RECT  2.16 12.555 62.586 12.825 ;
     RECT  2.16 13.095 62.586 13.365 ;
     RECT  2.16 13.635 62.586 13.905 ;
     RECT  2.16 14.175 62.586 14.445 ;
     RECT  2.16 14.715 62.586 14.985 ;
     RECT  2.16 15.255 62.586 15.525 ;
     RECT  2.16 15.795 62.586 16.065 ;
     RECT  2.16 16.335 62.586 16.605 ;
     RECT  2.16 16.875 62.586 17.145 ;
     RECT  2.16 17.415 62.586 17.685 ;
     RECT  2.16 17.955 62.586 18.225 ;
     RECT  2.16 18.495 62.586 18.765 ;
     RECT  2.16 19.035 62.586 19.305 ;
     RECT  2.16 19.575 62.586 19.845 ;
     RECT  2.16 20.115 62.586 20.385 ;
     RECT  2.16 20.655 62.586 20.925 ;
     RECT  2.16 21.195 62.586 21.465 ;
     RECT  2.16 21.735 62.586 22.005 ;
     RECT  2.16 22.275 62.586 22.545 ;
     RECT  2.16 22.815 62.586 23.085 ;
     RECT  2.16 23.355 62.586 23.625 ;
     RECT  2.16 23.895 62.586 24.165 ;
     RECT  2.16 24.435 62.586 24.705 ;
     RECT  2.16 24.975 62.586 25.245 ;
     RECT  2.16 25.515 62.586 25.785 ;
     RECT  2.16 26.055 62.586 26.325 ;
     RECT  2.16 26.595 62.586 26.865 ;
     RECT  2.16 27.135 62.586 27.405 ;
     RECT  2.16 27.675 62.586 27.945 ;
     RECT  2.16 28.215 62.586 28.485 ;
     RECT  2.16 28.755 62.586 29.025 ;
     RECT  2.16 29.295 62.586 29.565 ;
     RECT  2.16 29.835 62.586 30.105 ;
     RECT  2.16 30.375 62.586 30.645 ;
     RECT  2.16 30.915 62.586 31.185 ;
     RECT  2.16 31.455 62.586 31.725 ;
     RECT  2.16 31.995 62.586 32.265 ;
     RECT  2.16 32.535 62.586 32.805 ;
     RECT  2.16 33.075 62.586 33.345 ;
     RECT  2.16 33.615 62.586 33.885 ;
     RECT  2.16 34.155 62.586 34.425 ;
     RECT  2.16 34.695 62.586 34.965 ;
     RECT  2.16 35.235 62.586 35.505 ;
     RECT  2.16 35.775 62.586 36.045 ;
     RECT  2.16 36.315 62.586 36.585 ;
     RECT  2.16 36.855 62.586 37.125 ;
     RECT  2.16 37.395 62.586 37.665 ;
     RECT  2.16 37.935 62.586 38.205 ;
     RECT  2.16 38.475 62.586 38.745 ;
     RECT  2.16 39.015 62.586 39.285 ;
     RECT  2.16 39.555 62.586 39.825 ;
     RECT  2.16 40.095 62.586 40.365 ;
     RECT  2.16 40.635 62.586 40.905 ;
     RECT  2.16 41.175 62.586 41.445 ;
     RECT  2.16 41.715 62.586 41.985 ;
     RECT  2.16 42.255 62.586 42.525 ;
     RECT  2.16 42.795 62.586 43.065 ;
     RECT  2.16 43.335 62.586 43.605 ;
     RECT  2.16 43.875 62.586 44.145 ;
     RECT  2.16 44.415 62.586 44.685 ;
     RECT  2.16 44.955 62.586 45.225 ;
     RECT  2.16 45.495 62.586 45.765 ;
     RECT  2.16 46.035 62.586 46.305 ;
     RECT  2.16 46.575 62.586 46.845 ;
     RECT  2.16 47.115 62.586 47.385 ;
     RECT  2.16 47.655 62.586 47.925 ;
     RECT  2.16 48.195 62.586 48.465 ;
     RECT  2.16 48.735 62.586 49.005 ;
     RECT  2.16 49.275 62.586 49.545 ;
     RECT  2.16 49.815 62.586 50.085 ;
     RECT  2.16 50.355 62.586 50.625 ;
     RECT  2.16 50.895 62.586 51.165 ;
     RECT  2.16 51.435 62.586 51.705 ;
     RECT  2.16 51.975 62.586 52.245 ;
     RECT  2.16 52.515 62.586 52.785 ;
     RECT  2.16 53.055 62.586 53.325 ;
     RECT  2.16 53.595 62.586 53.865 ;
     RECT  2.16 54.135 62.586 54.405 ;
     RECT  2.16 54.675 62.586 54.945 ;
     RECT  2.16 55.215 62.586 55.485 ;
     RECT  2.16 55.755 62.586 56.025 ;
     RECT  2.16 56.295 62.586 56.565 ;
     RECT  2.16 56.835 62.586 57.105 ;
     RECT  2.16 57.375 62.586 57.645 ;
     RECT  2.16 57.915 62.586 58.05 ;
    LAYER M1 ;
     RECT  2.16 2.151 62.586 58.059 ;
    LAYER M2 ;
     RECT  2.16 2.151 14.647 58.059 ;
     RECT  14.647 1.926 14.863 58.059 ;
     RECT  14.863 1.881 15.187 58.059 ;
     RECT  15.187 1.836 15.511 58.059 ;
     RECT  15.367 0.72 15.799 0.738 ;
     RECT  15.799 0.216 16.303 0.738 ;
     RECT  16.303 0.216 16.483 0.864 ;
     RECT  15.511 1.8 16.483 58.059 ;
     RECT  16.483 0.216 17.167 58.059 ;
     RECT  17.167 0.108 17.275 58.059 ;
     RECT  17.275 0.036 18.139 58.059 ;
     RECT  18.139 0.036 19.427 58.14 ;
     RECT  19.427 0.036 20.155 0.666 ;
     RECT  19.427 1.422 20.155 58.14 ;
     RECT  20.155 0.036 20.759 58.14 ;
     RECT  20.759 1.422 20.803 58.14 ;
     RECT  20.335 59.58 21.091 59.598 ;
     RECT  21.091 59.544 21.343 59.598 ;
     RECT  20.803 1.422 21.371 58.176 ;
     RECT  20.759 0.036 21.811 0.594 ;
     RECT  21.371 1.422 21.811 58.14 ;
     RECT  21.343 59.544 21.883 60.174 ;
     RECT  21.811 0.036 22.343 58.14 ;
     RECT  22.343 0.036 23.207 0.126 ;
     RECT  21.883 59.544 23.899 60.408 ;
     RECT  23.647 0.18 23.935 0.198 ;
     RECT  23.935 0.18 24.151 0.396 ;
     RECT  23.899 59.238 24.251 60.408 ;
     RECT  24.151 0.072 24.395 0.396 ;
     RECT  24.395 0.072 24.431 0.324 ;
     RECT  24.431 0.072 24.511 0.279 ;
     RECT  24.511 0.036 24.539 0.279 ;
     RECT  22.343 1.152 24.899 58.14 ;
     RECT  24.899 1.998 25.007 58.14 ;
     RECT  24.539 0.036 25.267 0.126 ;
     RECT  24.251 59.544 25.411 60.408 ;
     RECT  24.899 1.152 25.475 1.17 ;
     RECT  25.267 0.036 25.735 0.162 ;
     RECT  25.735 0.036 26.051 0.279 ;
     RECT  26.051 0.036 26.123 0.234 ;
     RECT  25.411 59.544 26.807 60.444 ;
     RECT  26.123 0.036 26.851 0.126 ;
     RECT  26.851 0.036 26.995 0.162 ;
     RECT  25.007 2.034 26.995 58.14 ;
     RECT  26.995 0.036 27.131 0.396 ;
     RECT  27.067 1.152 27.175 1.17 ;
     RECT  26.995 2.034 27.239 58.716 ;
     RECT  27.175 1.152 27.275 1.242 ;
     RECT  26.807 59.544 27.283 60.408 ;
     RECT  27.131 0.036 27.967 0.279 ;
     RECT  27.283 59.508 28.139 60.408 ;
     RECT  27.967 0.036 28.607 0.36 ;
     RECT  28.615 1.224 28.651 1.242 ;
     RECT  27.239 2.034 28.651 58.14 ;
     RECT  28.651 1.224 28.687 58.14 ;
     RECT  28.687 1.152 28.787 58.14 ;
     RECT  28.139 59.544 29.083 60.408 ;
     RECT  28.607 0.036 29.471 0.198 ;
     RECT  28.787 1.728 29.875 58.14 ;
     RECT  29.875 1.656 29.975 58.14 ;
     RECT  29.083 59.436 30.163 60.408 ;
     RECT  29.471 0.036 30.307 0.126 ;
     RECT  30.307 0.036 30.443 0.468 ;
     RECT  29.975 2.106 30.443 58.14 ;
     RECT  30.379 1.224 30.451 1.242 ;
     RECT  30.451 1.071 30.811 1.242 ;
     RECT  30.163 59.238 31.019 60.408 ;
     RECT  30.443 0.036 31.163 0.324 ;
     RECT  30.811 1.071 31.171 1.278 ;
     RECT  30.443 2.151 31.171 58.14 ;
     RECT  31.171 1.071 31.235 58.14 ;
     RECT  31.235 1.152 31.631 58.14 ;
     RECT  31.631 1.728 31.667 58.14 ;
     RECT  31.163 0.036 31.883 0.198 ;
     RECT  31.667 1.836 31.927 58.14 ;
     RECT  31.019 59.436 31.927 60.408 ;
     RECT  31.927 1.836 32.431 60.408 ;
     RECT  31.883 0.036 32.611 0.126 ;
     RECT  32.431 1.728 32.647 60.408 ;
     RECT  32.611 0.036 32.683 0.198 ;
     RECT  32.647 1.152 32.891 60.408 ;
     RECT  32.683 0.036 33.475 0.279 ;
     RECT  33.475 0.036 33.611 0.36 ;
     RECT  32.891 2.106 33.647 60.408 ;
     RECT  33.647 59.238 33.683 60.408 ;
     RECT  33.647 2.106 33.727 58.14 ;
     RECT  32.891 1.152 33.871 1.242 ;
     RECT  33.611 0.036 33.899 0.198 ;
     RECT  33.871 1.152 34.195 1.278 ;
     RECT  33.727 2.034 34.195 58.14 ;
     RECT  34.195 1.152 34.871 58.14 ;
     RECT  33.899 0.036 35.023 0.09 ;
     RECT  33.683 59.544 35.195 60.408 ;
     RECT  35.023 0.036 35.311 0.126 ;
     RECT  34.871 1.152 35.915 1.404 ;
     RECT  34.871 2.151 35.959 58.14 ;
     RECT  35.195 59.544 35.959 60.264 ;
     RECT  35.311 0.036 35.987 0.279 ;
     RECT  35.959 59.544 35.995 60.336 ;
     RECT  35.987 0.036 36.131 0.126 ;
     RECT  35.959 1.728 36.571 58.14 ;
     RECT  36.571 1.728 36.895 58.212 ;
     RECT  36.895 1.224 36.931 58.212 ;
     RECT  36.931 1.152 36.995 58.212 ;
     RECT  36.131 0.036 37.255 0.054 ;
     RECT  35.995 59.544 37.643 60.408 ;
     RECT  36.995 1.152 37.939 1.17 ;
     RECT  36.995 1.962 37.939 58.212 ;
     RECT  37.643 59.931 38.111 60.408 ;
     RECT  37.255 0.036 38.551 0.198 ;
     RECT  38.551 0.036 38.651 0.234 ;
     RECT  38.651 0.036 38.831 0.198 ;
     RECT  38.111 60.318 38.839 60.408 ;
     RECT  38.839 60.246 38.911 60.408 ;
     RECT  37.939 1.152 38.947 58.212 ;
     RECT  38.911 60.201 39.271 60.408 ;
     RECT  39.271 59.85 39.407 60.408 ;
     RECT  39.407 60.246 39.659 60.408 ;
     RECT  38.831 0.036 39.739 0.126 ;
     RECT  38.947 1.152 39.803 58.248 ;
     RECT  39.739 0.036 39.991 0.198 ;
     RECT  39.803 1.728 40.379 58.248 ;
     RECT  39.659 60.318 40.495 60.408 ;
     RECT  39.991 0.036 40.567 0.864 ;
     RECT  40.379 1.728 40.567 58.059 ;
     RECT  40.495 60.084 40.639 60.408 ;
     RECT  40.639 60.012 41.143 60.408 ;
     RECT  41.143 59.976 41.431 60.408 ;
     RECT  41.431 59.886 41.531 60.408 ;
     RECT  41.531 60.156 41.971 60.408 ;
     RECT  41.971 60.156 42.107 60.444 ;
     RECT  40.567 0.036 42.187 58.059 ;
     RECT  42.187 0.036 42.323 58.788 ;
     RECT  42.107 60.201 42.835 60.444 ;
     RECT  42.835 60.156 43.187 60.444 ;
     RECT  42.323 0.036 43.375 58.059 ;
     RECT  43.375 0.036 43.691 58.716 ;
     RECT  43.691 0.576 44.411 58.716 ;
     RECT  44.411 0.918 44.591 58.716 ;
     RECT  44.591 0.918 45.275 58.059 ;
     RECT  45.275 0.954 45.311 58.059 ;
     RECT  45.311 1.071 45.499 58.059 ;
     RECT  45.499 1.071 45.707 58.176 ;
     RECT  43.187 60.201 45.751 60.444 ;
     RECT  45.707 1.071 45.959 58.059 ;
     RECT  45.959 1.458 45.995 58.059 ;
     RECT  45.995 1.836 46.499 58.059 ;
     RECT  46.499 1.881 46.643 58.059 ;
     RECT  46.643 1.926 46.787 58.059 ;
     RECT  45.751 59.814 47.471 60.444 ;
     RECT  46.787 1.962 47.543 58.059 ;
     RECT  47.471 59.814 47.579 60.372 ;
     RECT  47.579 59.814 47.615 59.832 ;
     RECT  47.543 2.151 62.586 58.059 ;
    LAYER M3 ;
     RECT  17.244 0.012 43.47 0.031 ;
     RECT  17.244 0.031 43.686 0.103 ;
     RECT  17.172 0.103 43.686 0.139 ;
     RECT  16.056 0.187 16.074 0.211 ;
     RECT  15.804 0.211 16.074 0.331 ;
     RECT  16.956 0.139 43.686 0.331 ;
     RECT  15.804 0.331 43.686 0.571 ;
     RECT  44.46 0.043 44.478 0.571 ;
     RECT  14.904 0.043 14.922 0.715 ;
     RECT  15.804 0.571 44.478 0.715 ;
     RECT  45.252 0.913 45.27 0.949 ;
     RECT  45.252 0.949 45.306 0.985 ;
     RECT  45.216 0.985 45.306 1.066 ;
     RECT  14.904 0.715 44.478 1.255 ;
     RECT  45.216 1.066 45.954 1.255 ;
     RECT  14.904 1.255 45.954 1.453 ;
     RECT  14.904 1.453 45.99 1.831 ;
     RECT  14.904 1.831 46.494 1.876 ;
     RECT  14.868 1.876 46.638 1.921 ;
     RECT  2.415 2.143 2.505 2.413 ;
     RECT  5.115 2.143 5.205 2.413 ;
     RECT  7.815 2.143 7.905 2.413 ;
     RECT  10.515 2.143 10.605 2.413 ;
     RECT  13.215 2.143 13.305 2.413 ;
     RECT  48.315 2.143 48.405 2.413 ;
     RECT  51.015 2.143 51.105 2.413 ;
     RECT  53.715 2.143 53.805 2.413 ;
     RECT  56.415 2.143 56.505 2.413 ;
     RECT  59.115 2.143 59.205 2.413 ;
     RECT  61.815 2.143 61.905 2.413 ;
     RECT  47.52 1.957 47.538 2.569 ;
     RECT  48.315 2.413 48.597 2.569 ;
     RECT  14.652 1.921 46.782 2.641 ;
     RECT  14.4 2.641 46.782 2.795 ;
     RECT  14.868 2.795 46.782 3.335 ;
     RECT  15.336 3.335 46.782 3.407 ;
     RECT  15.408 3.407 46.782 3.721 ;
     RECT  47.52 2.569 48.597 3.721 ;
     RECT  15.408 3.721 48.597 4.225 ;
     RECT  14.832 4.225 48.597 4.415 ;
     RECT  14.832 4.415 14.85 4.559 ;
     RECT  15.588 4.415 48.597 4.955 ;
     RECT  61.815 2.413 62.097 29.731 ;
     RECT  61.815 29.731 62.442 29.755 ;
     RECT  61.815 29.755 62.802 29.933 ;
     RECT  61.815 29.933 62.19 30.029 ;
     RECT  15.915 4.955 48.597 34.259 ;
     RECT  17.388 34.259 48.597 34.421 ;
     RECT  15.915 34.259 16.506 34.799 ;
     RECT  17.82 34.421 48.597 37.049 ;
     RECT  15.915 34.799 16.197 46.741 ;
     RECT  15.915 46.741 16.506 46.781 ;
     RECT  17.82 37.049 18.897 56.219 ;
     RECT  17.928 56.219 18.897 57.371 ;
     RECT  2.415 2.413 2.697 57.797 ;
     RECT  5.115 2.413 5.397 57.797 ;
     RECT  7.815 2.413 8.097 57.797 ;
     RECT  10.515 2.413 10.797 57.797 ;
     RECT  13.215 2.413 13.497 57.797 ;
     RECT  15.915 46.781 16.197 57.797 ;
     RECT  19.656 37.049 48.597 57.797 ;
     RECT  51.015 2.413 51.297 57.797 ;
     RECT  53.715 2.413 53.997 57.797 ;
     RECT  56.415 2.413 56.697 57.797 ;
     RECT  59.115 2.413 59.397 57.797 ;
     RECT  61.815 30.029 62.097 57.797 ;
     RECT  19.656 57.797 47.61 57.917 ;
     RECT  2.607 57.797 2.697 58.067 ;
     RECT  5.307 57.797 5.397 58.067 ;
     RECT  8.007 57.797 8.097 58.067 ;
     RECT  10.707 57.797 10.797 58.067 ;
     RECT  13.407 57.797 13.497 58.067 ;
     RECT  16.107 57.797 16.197 58.067 ;
     RECT  18.144 57.371 18.897 58.067 ;
     RECT  48.507 57.797 48.597 58.067 ;
     RECT  51.207 57.797 51.297 58.067 ;
     RECT  53.907 57.797 53.997 58.067 ;
     RECT  56.607 57.797 56.697 58.067 ;
     RECT  59.307 57.797 59.397 58.067 ;
     RECT  62.007 57.797 62.097 58.067 ;
     RECT  18.144 58.067 18.162 58.145 ;
     RECT  20.34 57.917 47.61 58.181 ;
     RECT  21.096 58.181 47.61 59.567 ;
     RECT  20.34 58.181 20.358 59.603 ;
     RECT  21.348 59.567 47.61 59.837 ;
     RECT  21.348 59.837 47.574 60.179 ;
     RECT  21.636 60.179 47.574 60.377 ;
     RECT  21.636 60.377 47.502 60.444 ;
     RECT  25.416 60.444 25.434 60.449 ;
     RECT  26.784 60.444 26.802 60.449 ;
     RECT  41.976 60.444 41.994 60.449 ;
     RECT  47.448 60.444 47.466 60.449 ;
    LAYER M4 ;
     RECT  2.408 2.148 2.512 57.792 ;
     RECT  2.512 2.418 2.6 57.792 ;
     RECT  2.6 2.418 2.704 58.062 ;
     RECT  5.108 2.148 5.212 57.792 ;
     RECT  5.212 2.418 5.3 57.792 ;
     RECT  5.3 2.418 5.404 58.062 ;
     RECT  7.808 2.148 7.912 57.792 ;
     RECT  7.912 2.418 8 57.792 ;
     RECT  8 2.418 8.104 58.062 ;
     RECT  10.508 2.148 10.612 57.792 ;
     RECT  10.612 2.418 10.7 57.792 ;
     RECT  10.7 2.418 10.804 58.062 ;
     RECT  13.208 2.148 13.312 57.792 ;
     RECT  13.312 2.418 13.4 57.792 ;
     RECT  13.4 2.418 13.504 58.062 ;
     RECT  14.893 0.048 15.145 0.072 ;
     RECT  15.037 3.072 15.325 3.096 ;
     RECT  14.773 4.224 15.325 4.248 ;
     RECT  15.325 2.832 15.349 4.248 ;
     RECT  14.773 34.464 15.349 34.488 ;
     RECT  15.349 2.544 15.577 4.248 ;
     RECT  15.145 0.048 15.649 0.936 ;
     RECT  15.577 2.544 15.649 4.536 ;
     RECT  15.649 0.048 15.908 4.536 ;
     RECT  15.349 34.08 15.908 34.488 ;
     RECT  15.781 57.36 15.908 57.384 ;
     RECT  15.908 0.048 16.1 57.792 ;
     RECT  16.1 0.048 16.204 58.062 ;
     RECT  16.204 46.752 16.517 46.776 ;
     RECT  16.204 0.048 17.221 6.744 ;
     RECT  17.221 31.104 17.317 31.128 ;
     RECT  17.269 32.208 17.413 32.232 ;
     RECT  16.204 36.048 17.509 36.264 ;
     RECT  17.605 43.632 17.701 43.656 ;
     RECT  17.413 32.208 17.893 32.76 ;
     RECT  16.204 34.08 17.893 34.92 ;
     RECT  17.221 0.048 17.989 6.84 ;
     RECT  17.317 30.24 18.133 31.128 ;
     RECT  18.085 27.6 18.277 27.624 ;
     RECT  18.133 30.048 18.325 31.128 ;
     RECT  18.325 29.808 18.421 31.128 ;
     RECT  17.989 0.048 18.469 6.936 ;
     RECT  18.469 0.048 18.608 7.128 ;
     RECT  18.469 8.16 18.608 8.184 ;
     RECT  18.181 12.288 18.608 12.312 ;
     RECT  17.797 19.632 18.608 19.656 ;
     RECT  18.037 23.616 18.608 23.64 ;
     RECT  18.277 27.072 18.608 27.624 ;
     RECT  18.421 29.76 18.608 31.128 ;
     RECT  17.893 32.208 18.608 34.92 ;
     RECT  17.509 36 18.608 36.264 ;
     RECT  17.701 43.632 18.608 44.472 ;
     RECT  18.229 47.328 18.608 47.352 ;
     RECT  16.204 57.072 18.608 57.384 ;
     RECT  18.608 0.048 18.8 57.792 ;
     RECT  18.8 0.048 18.904 58.062 ;
     RECT  18.904 12.288 19.685 13.224 ;
     RECT  18.904 25.104 19.793 25.464 ;
     RECT  18.904 10.704 19.909 10.728 ;
     RECT  19.685 12.288 19.909 12.312 ;
     RECT  18.904 42.768 20.081 42.792 ;
     RECT  18.904 0.048 20.185 8.568 ;
     RECT  19.909 10.704 20.677 12.312 ;
     RECT  20.149 22.224 20.821 22.248 ;
     RECT  18.904 27.072 21.061 31.128 ;
     RECT  18.904 32.208 21.061 32.76 ;
     RECT  21.049 14.592 21.109 14.76 ;
     RECT  21.109 14.496 21.157 14.856 ;
     RECT  20.185 0.048 21.308 9.096 ;
     RECT  20.677 10.32 21.308 12.312 ;
     RECT  20.725 13.344 21.308 13.368 ;
     RECT  21.157 14.496 21.308 14.952 ;
     RECT  18.904 15.984 21.308 16.008 ;
     RECT  18.904 19.632 21.308 19.656 ;
     RECT  20.821 22.224 21.308 22.488 ;
     RECT  18.904 23.616 21.308 23.64 ;
     RECT  19.793 25.44 21.308 25.464 ;
     RECT  21.061 27.072 21.308 32.76 ;
     RECT  18.904 34.08 21.308 36.264 ;
     RECT  18.904 43.776 21.308 43.8 ;
     RECT  18.904 57.072 21.308 57.912 ;
     RECT  21.308 0.048 21.5 57.912 ;
     RECT  21.5 0.048 21.604 58.062 ;
     RECT  21.604 15.984 21.881 16.008 ;
     RECT  21.604 22.224 21.953 22.488 ;
     RECT  21.604 0.048 22.529 12.36 ;
     RECT  21.604 27.072 22.637 36.264 ;
     RECT  22.529 1.152 22.741 12.36 ;
     RECT  21.604 13.344 22.741 13.368 ;
     RECT  21.604 23.616 22.745 23.64 ;
     RECT  23.221 21.168 23.701 21.192 ;
     RECT  21.953 22.464 23.749 22.488 ;
     RECT  22.529 0.048 23.893 0.072 ;
     RECT  22.741 1.152 23.893 13.368 ;
     RECT  23.929 60.288 23.965 60.312 ;
     RECT  23.893 0.048 24.008 13.368 ;
     RECT  23.125 15.984 24.008 16.008 ;
     RECT  23.701 21.12 24.008 21.192 ;
     RECT  23.749 22.464 24.008 22.824 ;
     RECT  21.604 24.912 24.008 25.464 ;
     RECT  22.637 27.984 24.008 36.264 ;
     RECT  21.604 57.072 24.008 57.912 ;
     RECT  23.965 60.288 24.077 60.408 ;
     RECT  24.008 0.048 24.2 57.912 ;
     RECT  24.2 0.048 24.304 58.062 ;
     RECT  24.077 60.336 24.401 60.408 ;
     RECT  24.401 60.336 24.473 60.36 ;
     RECT  24.304 0.048 24.509 10.968 ;
     RECT  24.304 28.176 24.545 36.264 ;
     RECT  24.304 26.784 24.661 26.808 ;
     RECT  24.304 22.464 24.797 22.824 ;
     RECT  24.509 0.144 24.869 10.968 ;
     RECT  24.545 32.208 25.121 36.264 ;
     RECT  24.545 28.176 25.229 31.224 ;
     RECT  25.121 32.496 25.337 36.264 ;
     RECT  24.304 15.984 25.381 16.008 ;
     RECT  25.229 28.176 25.429 30.936 ;
     RECT  25.429 27.936 25.553 30.936 ;
     RECT  25.513 60.384 25.585 60.408 ;
     RECT  25.585 60.336 25.619 60.408 ;
     RECT  24.869 0.144 25.693 10.872 ;
     RECT  25.619 60.336 25.733 60.36 ;
     RECT  24.304 24.672 25.829 25.464 ;
     RECT  24.304 12.288 25.861 13.368 ;
     RECT  25.693 0.048 25.909 10.872 ;
     RECT  25.861 12 25.909 13.368 ;
     RECT  25.829 24.672 25.937 25.656 ;
     RECT  24.304 57.072 26.053 57.912 ;
     RECT  25.765 59.856 26.089 60.024 ;
     RECT  26.053 56.832 26.108 57.912 ;
     RECT  25.909 0.048 26.195 13.368 ;
     RECT  26.108 56.448 26.197 57.912 ;
     RECT  26.089 59.328 26.197 60.024 ;
     RECT  25.981 44.448 26.377 44.472 ;
     RECT  26.195 0.048 26.633 0.6 ;
     RECT  26.197 56.448 26.701 60.024 ;
     RECT  26.195 1.728 26.708 13.368 ;
     RECT  25.381 15.984 26.708 16.584 ;
     RECT  24.304 21.168 26.708 21.432 ;
     RECT  24.797 22.8 26.708 22.824 ;
     RECT  25.937 24.528 26.708 25.656 ;
     RECT  25.549 26.736 26.708 26.76 ;
     RECT  25.553 27.984 26.708 30.936 ;
     RECT  26.333 31.92 26.708 31.944 ;
     RECT  25.337 33.312 26.708 36.264 ;
     RECT  26.377 44.4 26.708 44.472 ;
     RECT  25.873 50.16 26.708 50.184 ;
     RECT  26.701 56.448 26.708 60.216 ;
     RECT  26.708 1.728 26.821 60.216 ;
     RECT  26.821 1.728 27.004 60.312 ;
     RECT  27.004 55.872 27.133 60.312 ;
     RECT  26.633 0.048 27.137 0.408 ;
     RECT  27.004 33.648 27.155 36.456 ;
     RECT  27.137 0.144 27.203 0.408 ;
     RECT  27.133 55.872 27.205 60.36 ;
     RECT  27.004 15.84 27.251 15.864 ;
     RECT  27.004 26.736 27.299 26.76 ;
     RECT  27.155 34.128 27.353 36.456 ;
     RECT  27.004 22.752 27.395 23.4 ;
     RECT  27.353 34.128 27.443 36.408 ;
     RECT  27.443 34.128 27.497 35.496 ;
     RECT  27.205 55.872 27.539 60.408 ;
     RECT  27.004 43.344 27.635 45.048 ;
     RECT  27.539 56.496 27.683 60.408 ;
     RECT  27.004 51.888 27.827 51.912 ;
     RECT  27.004 38.784 27.923 39.336 ;
     RECT  27.395 23.376 27.929 23.4 ;
     RECT  27.004 54.72 28.019 54.744 ;
     RECT  27.004 42.192 28.069 42.216 ;
     RECT  28.069 41.616 28.115 42.216 ;
     RECT  27.004 27.888 28.117 30.936 ;
     RECT  27.004 21.408 28.165 21.432 ;
     RECT  27.635 43.872 28.211 45.048 ;
     RECT  27.923 39.312 28.289 39.336 ;
     RECT  28.117 27.312 28.325 30.936 ;
     RECT  27.004 50.16 28.355 50.184 ;
     RECT  28.213 33.648 28.637 33.672 ;
     RECT  27.497 34.704 28.637 35.496 ;
     RECT  27.203 0.144 28.643 0.312 ;
     RECT  27.683 59.28 29.171 60.408 ;
     RECT  27.004 1.728 29.408 12.84 ;
     RECT  28.789 14.208 29.408 14.232 ;
     RECT  28.165 21.408 29.408 22.248 ;
     RECT  27.004 24.672 29.408 25.464 ;
     RECT  28.325 27.984 29.408 30.936 ;
     RECT  28.165 32.448 29.408 32.472 ;
     RECT  28.637 33.648 29.408 35.496 ;
     RECT  29.077 36.48 29.408 36.504 ;
     RECT  28.115 41.616 29.408 41.64 ;
     RECT  28.211 44.352 29.408 45.048 ;
     RECT  27.683 56.496 29.408 58.152 ;
     RECT  29.171 59.76 29.441 60.408 ;
     RECT  29.441 59.76 29.555 60.36 ;
     RECT  29.408 1.728 29.704 58.152 ;
     RECT  29.704 34.704 29.801 35.448 ;
     RECT  29.555 59.808 29.843 60.36 ;
     RECT  29.704 1.728 29.908 12.84 ;
     RECT  29.704 21.408 29.945 22.248 ;
     RECT  29.908 1.68 30.125 12.84 ;
     RECT  29.843 59.808 30.125 60.312 ;
     RECT  28.643 0.144 30.149 0.264 ;
     RECT  30.149 0.096 30.178 0.264 ;
     RECT  30.178 0.096 30.193 0.312 ;
     RECT  30.125 1.68 30.193 12.552 ;
     RECT  29.704 14.208 30.241 14.232 ;
     RECT  29.704 49.536 30.269 49.56 ;
     RECT  29.704 56.496 30.593 58.152 ;
     RECT  29.801 34.704 30.737 34.728 ;
     RECT  29.704 26.544 30.809 33.336 ;
     RECT  30.809 26.544 30.877 26.76 ;
     RECT  30.757 42.72 30.899 42.936 ;
     RECT  30.757 46.56 30.899 46.776 ;
     RECT  30.757 50.688 30.899 50.904 ;
     RECT  30.757 54.528 30.899 54.744 ;
     RECT  30.757 38.64 30.901 38.808 ;
     RECT  30.901 38.16 30.947 38.808 ;
     RECT  30.899 42.72 30.947 42.84 ;
     RECT  30.899 46.656 30.947 46.776 ;
     RECT  30.899 50.688 30.947 50.808 ;
     RECT  30.899 54.624 30.947 54.744 ;
     RECT  29.704 37.152 30.949 37.176 ;
     RECT  30.947 38.16 30.949 38.184 ;
     RECT  29.945 21.408 30.953 21.432 ;
     RECT  30.947 42.816 31.043 42.84 ;
     RECT  30.947 46.656 31.043 46.68 ;
     RECT  30.947 50.784 31.043 50.808 ;
     RECT  30.947 54.624 31.043 54.648 ;
     RECT  30.125 59.904 31.1 60.312 ;
     RECT  30.949 37.152 31.133 38.184 ;
     RECT  31.1 59.856 31.237 60.312 ;
     RECT  30.193 0.096 31.321 12.552 ;
     RECT  31.321 0.144 31.349 12.552 ;
     RECT  31.237 59.76 31.525 60.312 ;
     RECT  30.869 13.68 31.813 13.704 ;
     RECT  31.349 1.632 31.885 12.552 ;
     RECT  31.813 13.68 31.885 14.232 ;
     RECT  30.593 56.496 31.909 57.912 ;
     RECT  31.525 58.944 31.909 60.312 ;
     RECT  31.909 56.496 31.96 60.36 ;
     RECT  31.133 38.16 32.101 38.184 ;
     RECT  31.885 1.632 32.108 14.232 ;
     RECT  31.909 18.24 32.108 18.264 ;
     RECT  31.381 19.344 32.108 19.368 ;
     RECT  31.021 23.04 32.108 23.064 ;
     RECT  30.877 25.632 32.108 26.76 ;
     RECT  30.809 27.888 32.108 33.336 ;
     RECT  31.381 35.232 32.108 35.448 ;
     RECT  31.133 37.152 32.108 37.176 ;
     RECT  32.101 38.16 32.108 38.76 ;
     RECT  31.96 56.496 32.108 60.408 ;
     RECT  32.108 1.632 32.404 60.408 ;
     RECT  31.349 0.144 32.437 0.36 ;
     RECT  32.404 1.632 32.437 14.52 ;
     RECT  32.404 18.24 32.465 18.264 ;
     RECT  32.404 38.16 32.465 38.76 ;
     RECT  32.404 20.4 32.681 21.432 ;
     RECT  32.404 56.496 32.825 60.408 ;
     RECT  32.437 0.144 33.346 14.52 ;
     RECT  33.346 0.096 33.587 14.52 ;
     RECT  32.404 23.04 33.625 25.464 ;
     RECT  33.587 0.192 33.635 14.52 ;
     RECT  32.825 56.496 33.733 60.36 ;
     RECT  33.635 0.576 33.901 14.52 ;
     RECT  33.901 0.576 34.193 14.664 ;
     RECT  33.625 23.04 34.261 23.688 ;
     RECT  32.404 26.496 34.297 34.2 ;
     RECT  32.404 35.232 34.297 37.176 ;
     RECT  33.733 56.304 34.549 60.36 ;
     RECT  34.645 0.192 34.765 0.36 ;
     RECT  33.625 24.912 34.801 25.464 ;
     RECT  34.297 26.496 34.801 37.176 ;
     RECT  34.193 1.872 34.808 14.664 ;
     RECT  34.081 15.792 34.808 15.816 ;
     RECT  32.404 19.344 34.808 19.368 ;
     RECT  32.681 20.4 34.808 20.424 ;
     RECT  32.681 21.408 34.808 21.432 ;
     RECT  34.261 22.992 34.808 23.688 ;
     RECT  34.801 24.912 34.808 37.176 ;
     RECT  32.465 38.16 34.808 38.184 ;
     RECT  33.829 39.84 34.808 39.864 ;
     RECT  34.549 56.304 34.808 60.408 ;
     RECT  34.808 1.872 35.104 60.408 ;
     RECT  35.104 23.04 35.165 37.656 ;
     RECT  35.104 49.584 35.267 49.608 ;
     RECT  34.765 0.048 35.269 0.36 ;
     RECT  35.269 0.048 35.345 0.408 ;
     RECT  35.104 46.752 35.363 46.776 ;
     RECT  35.104 39.84 35.381 39.864 ;
     RECT  35.165 23.04 35.507 25.464 ;
     RECT  35.165 26.832 35.561 37.656 ;
     RECT  35.104 19.92 35.699 20.424 ;
     RECT  35.561 26.832 35.813 36.552 ;
     RECT  35.345 0.096 35.929 0.408 ;
     RECT  35.561 37.632 36.028 37.656 ;
     RECT  35.929 0.144 36.029 0.408 ;
     RECT  35.104 1.872 36.083 14.664 ;
     RECT  35.104 56.304 36.083 60.408 ;
     RECT  36.083 1.872 36.101 12.36 ;
     RECT  35.104 21.408 36.133 21.432 ;
     RECT  35.507 23.088 36.181 25.464 ;
     RECT  35.813 26.832 36.181 34.104 ;
     RECT  36.083 56.304 36.197 58.68 ;
     RECT  36.083 13.344 36.241 14.664 ;
     RECT  36.181 23.088 36.389 34.104 ;
     RECT  36.197 55.824 36.389 58.68 ;
     RECT  36.029 0.192 36.517 0.408 ;
     RECT  36.389 55.824 36.563 58.2 ;
     RECT  36.517 0.192 36.565 0.6 ;
     RECT  36.101 1.872 36.565 10.152 ;
     RECT  36.565 0.192 36.659 10.152 ;
     RECT  36.241 13.344 36.661 14.712 ;
     RECT  36.563 55.824 36.709 57.792 ;
     RECT  36.853 50.16 36.925 50.184 ;
     RECT  36.659 0.192 36.994 0.6 ;
     RECT  36.083 59.904 37.069 60.408 ;
     RECT  36.994 0.144 37.249 0.6 ;
     RECT  36.133 20.496 37.393 21.432 ;
     RECT  36.659 1.872 37.508 10.152 ;
     RECT  36.101 11.184 37.508 12.36 ;
     RECT  36.661 13.344 37.508 14.808 ;
     RECT  35.104 15.792 37.508 15.816 ;
     RECT  37.393 19.872 37.508 21.432 ;
     RECT  36.389 23.088 37.508 25.464 ;
     RECT  36.389 26.736 37.508 34.104 ;
     RECT  35.813 35.232 37.508 36.552 ;
     RECT  37.285 40.992 37.508 41.016 ;
     RECT  36.997 49.008 37.508 49.032 ;
     RECT  36.925 50.16 37.508 50.328 ;
     RECT  37.429 54.144 37.508 54.168 ;
     RECT  36.709 55.296 37.508 57.792 ;
     RECT  37.508 1.872 37.7 57.792 ;
     RECT  37.7 1.872 37.717 58.062 ;
     RECT  37.717 1.728 37.804 58.062 ;
     RECT  37.804 23.328 37.829 24.504 ;
     RECT  37.804 21.408 37.955 22.008 ;
     RECT  37.804 49.008 37.955 49.032 ;
     RECT  37.804 50.304 38.003 50.328 ;
     RECT  37.804 56.448 38.005 58.062 ;
     RECT  37.069 59.28 38.005 60.408 ;
     RECT  37.804 54.144 38.051 54.168 ;
     RECT  37.829 23.328 38.099 24.456 ;
     RECT  38.005 56.448 38.099 60.408 ;
     RECT  37.804 55.44 38.147 55.464 ;
     RECT  38.099 58.128 38.147 60.408 ;
     RECT  37.804 25.92 38.243 31.752 ;
     RECT  37.804 19.872 38.291 19.896 ;
     RECT  38.147 58.128 38.291 59.304 ;
     RECT  37.804 15.792 38.435 15.816 ;
     RECT  38.099 56.448 38.483 57.048 ;
     RECT  37.804 32.736 38.513 34.104 ;
     RECT  37.804 13.344 38.531 14.664 ;
     RECT  38.483 56.448 38.675 56.856 ;
     RECT  37.804 17.328 38.797 17.352 ;
     RECT  38.099 23.616 38.867 24.456 ;
     RECT  37.249 0.048 38.869 0.6 ;
     RECT  38.243 25.92 39.017 31.416 ;
     RECT  38.675 56.736 39.053 56.856 ;
     RECT  38.869 0.048 39.059 0.648 ;
     RECT  37.804 1.728 39.085 12.36 ;
     RECT  37.804 35.136 39.109 35.448 ;
     RECT  37.804 36.528 39.109 36.552 ;
     RECT  39.059 0.048 39.125 0.168 ;
     RECT  38.147 60.288 39.125 60.408 ;
     RECT  38.513 33.264 39.205 34.104 ;
     RECT  39.109 35.136 39.205 36.552 ;
     RECT  38.797 17.184 39.265 17.352 ;
     RECT  38.291 58.656 39.265 59.304 ;
     RECT  39.125 60.288 39.265 60.312 ;
     RECT  37.955 21.984 39.769 22.008 ;
     RECT  39.205 33.264 39.769 36.552 ;
     RECT  39.769 21.936 39.841 22.008 ;
     RECT  39.085 1.152 39.917 12.36 ;
     RECT  38.531 13.344 39.925 14.52 ;
     RECT  39.877 54.48 39.949 54.6 ;
     RECT  39.017 27.984 40.021 31.416 ;
     RECT  39.769 32.496 40.021 36.552 ;
     RECT  39.917 1.2 40.093 12.36 ;
     RECT  39.925 13.344 40.093 14.808 ;
     RECT  39.265 58.656 40.117 60.312 ;
     RECT  40.093 1.2 40.208 14.808 ;
     RECT  39.265 17.184 40.208 17.928 ;
     RECT  39.841 21.936 40.208 22.056 ;
     RECT  38.867 23.616 40.208 24.408 ;
     RECT  39.017 25.92 40.208 26.856 ;
     RECT  40.021 27.984 40.208 36.552 ;
     RECT  39.493 38.16 40.208 38.184 ;
     RECT  38.917 41.568 40.208 41.592 ;
     RECT  39.877 46.752 40.208 46.776 ;
     RECT  39.973 49.008 40.208 49.032 ;
     RECT  39.877 50.688 40.208 50.808 ;
     RECT  39.949 54.48 40.208 54.696 ;
     RECT  39.053 56.832 40.208 56.856 ;
     RECT  40.117 58.128 40.208 60.312 ;
     RECT  40.208 1.2 40.504 60.312 ;
     RECT  39.125 0.048 40.597 0.072 ;
     RECT  40.504 58.944 40.67 60.312 ;
     RECT  40.504 33.072 40.673 38.184 ;
     RECT  40.504 1.2 40.739 13.944 ;
     RECT  40.504 55.824 40.739 55.848 ;
     RECT  40.504 27.936 40.883 28.2 ;
     RECT  40.597 0.048 41.033 0.12 ;
     RECT  40.504 25.536 41.141 26.616 ;
     RECT  40.673 33.072 41.213 37.56 ;
     RECT  40.504 17.184 41.267 17.928 ;
     RECT  41.213 36.528 41.315 37.56 ;
     RECT  40.739 1.2 41.353 12.792 ;
     RECT  40.504 40.992 41.393 41.4 ;
     RECT  40.883 28.176 41.497 28.2 ;
     RECT  40.504 29.568 41.497 31.944 ;
     RECT  41.141 25.536 41.573 26.136 ;
     RECT  40.504 56.832 41.605 56.856 ;
     RECT  40.67 58.944 41.701 60.072 ;
     RECT  41.497 28.176 41.747 31.944 ;
     RECT  41.605 47.28 41.753 47.304 ;
     RECT  40.504 23.616 41.821 24.408 ;
     RECT  41.573 25.536 41.821 25.704 ;
     RECT  41.701 58.944 41.857 60.312 ;
     RECT  41.857 58.944 41.893 60.408 ;
     RECT  41.497 39.888 41.939 39.912 ;
     RECT  41.605 56.448 42.001 56.856 ;
     RECT  41.893 58.128 42.001 60.408 ;
     RECT  42.001 56.448 42.005 60.408 ;
     RECT  41.315 36.816 42.085 37.56 ;
     RECT  41.747 29.616 42.253 31.944 ;
     RECT  41.213 33.072 42.253 35.496 ;
     RECT  42.037 27.168 42.284 27.192 ;
     RECT  42.253 50.304 42.325 50.328 ;
     RECT  42.253 29.616 42.361 35.496 ;
     RECT  42.085 36.816 42.361 37.656 ;
     RECT  41.821 23.616 42.389 25.704 ;
     RECT  42.005 56.448 42.419 60.36 ;
     RECT  40.504 21.936 42.433 22.056 ;
     RECT  42.389 23.328 42.433 25.704 ;
     RECT  42.419 56.448 42.505 60.312 ;
     RECT  42.433 21.936 42.565 25.704 ;
     RECT  42.284 26.736 42.565 27.192 ;
     RECT  41.267 17.904 42.613 17.928 ;
     RECT  42.613 15.936 42.685 15.96 ;
     RECT  41.393 41.376 42.757 41.4 ;
     RECT  42.361 29.616 42.793 37.656 ;
     RECT  41.353 1.152 42.908 12.792 ;
     RECT  40.739 13.92 42.908 13.944 ;
     RECT  42.685 15.936 42.908 16.2 ;
     RECT  42.613 17.616 42.908 17.928 ;
     RECT  42.565 21.072 42.908 27.192 ;
     RECT  41.747 28.176 42.908 28.2 ;
     RECT  42.793 29.472 42.908 37.656 ;
     RECT  42.757 41.376 42.908 41.496 ;
     RECT  42.325 50.304 42.908 51.288 ;
     RECT  42.397 53.04 42.908 53.064 ;
     RECT  42.613 54.72 42.908 54.744 ;
     RECT  42.505 55.776 42.908 60.312 ;
     RECT  42.908 1.152 43.204 60.312 ;
     RECT  43.204 41.376 43.301 41.496 ;
     RECT  43.204 50.304 43.331 50.424 ;
     RECT  43.204 1.152 43.337 10.2 ;
     RECT  43.301 41.472 43.337 41.496 ;
     RECT  43.204 55.872 43.405 60.312 ;
     RECT  41.033 0.048 43.436 0.072 ;
     RECT  43.204 32.448 43.475 32.472 ;
     RECT  43.405 55.872 43.475 60.408 ;
     RECT  43.436 0.048 43.523 0.12 ;
     RECT  43.204 33.6 43.523 36.888 ;
     RECT  43.204 11.184 43.553 12.792 ;
     RECT  43.475 55.872 43.571 58.776 ;
     RECT  43.204 28.176 43.619 31.368 ;
     RECT  43.337 1.824 43.667 10.2 ;
     RECT  43.204 44.448 43.667 44.472 ;
     RECT  43.204 21.984 43.715 23.64 ;
     RECT  43.571 58.128 43.763 58.776 ;
     RECT  43.204 17.088 43.769 17.928 ;
     RECT  43.523 33.6 43.811 33.624 ;
     RECT  43.715 22.032 43.859 23.64 ;
     RECT  43.553 12.336 43.913 12.792 ;
     RECT  43.667 7.104 43.955 10.2 ;
     RECT  43.955 7.152 44.003 10.2 ;
     RECT  43.859 23.376 44.021 23.64 ;
     RECT  43.769 17.616 44.051 17.928 ;
     RECT  43.523 34.704 44.057 36.888 ;
     RECT  44.057 34.944 44.099 36.888 ;
     RECT  44.051 17.904 44.129 17.928 ;
     RECT  43.913 12.336 44.195 12.36 ;
     RECT  43.204 13.824 44.197 14.664 ;
     RECT  44.021 23.376 44.237 23.4 ;
     RECT  43.331 50.4 44.237 50.424 ;
     RECT  43.763 58.704 44.243 58.776 ;
     RECT  43.619 28.176 44.387 31.32 ;
     RECT  44.243 58.752 44.417 58.776 ;
     RECT  43.204 20.496 44.453 20.52 ;
     RECT  43.523 0.048 44.489 0.072 ;
     RECT  43.204 25.104 44.489 25.128 ;
     RECT  43.571 55.872 44.531 56.856 ;
     RECT  44.197 13.824 44.557 14.856 ;
     RECT  44.003 7.152 44.579 9.336 ;
     RECT  44.387 28.176 44.579 30.792 ;
     RECT  43.475 59.856 44.581 60.408 ;
     RECT  44.557 13.632 44.641 14.856 ;
     RECT  44.581 59.664 44.669 60.408 ;
     RECT  44.669 60.048 44.849 60.408 ;
     RECT  43.204 26.736 45.205 26.76 ;
     RECT  45.205 26.736 45.277 26.808 ;
     RECT  43.667 1.824 45.608 6.12 ;
     RECT  44.579 7.968 45.608 9.336 ;
     RECT  43.553 11.184 45.608 11.208 ;
     RECT  44.641 13.824 45.608 14.856 ;
     RECT  44.677 15.984 45.608 16.008 ;
     RECT  45.277 26.208 45.608 26.808 ;
     RECT  44.579 28.176 45.608 28.584 ;
     RECT  44.579 29.76 45.608 29.88 ;
     RECT  44.989 32.496 45.608 32.52 ;
     RECT  44.099 35.184 45.608 36.888 ;
     RECT  44.531 56.832 45.608 56.856 ;
     RECT  45.608 1.824 45.8 57.792 ;
     RECT  45.8 1.824 45.904 58.062 ;
     RECT  45.904 9.312 45.965 9.336 ;
     RECT  45.904 26.736 46.045 26.76 ;
     RECT  45.904 1.824 46.067 2.904 ;
     RECT  45.904 13.824 46.211 14.664 ;
     RECT  46.067 1.824 46.259 2.808 ;
     RECT  45.904 35.184 46.259 36.888 ;
     RECT  46.259 2.016 46.307 2.808 ;
     RECT  46.259 35.184 46.307 36.552 ;
     RECT  46.307 2.016 46.355 2.616 ;
     RECT  46.307 35.184 46.355 36.072 ;
     RECT  46.355 2.016 46.403 2.52 ;
     RECT  46.355 35.184 46.403 35.208 ;
     RECT  46.403 2.496 46.451 2.52 ;
     RECT  45.904 28.176 46.451 28.2 ;
     RECT  44.849 60.192 46.741 60.408 ;
     RECT  45.904 22.128 46.787 22.776 ;
     RECT  46.741 59.856 46.828 60.408 ;
     RECT  45.904 10.8 46.873 10.824 ;
     RECT  46.211 13.824 46.883 13.848 ;
     RECT  45.904 18.672 47.027 18.696 ;
     RECT  46.828 59.952 47.225 60.408 ;
     RECT  46.787 22.752 47.315 22.776 ;
     RECT  47.225 60.384 47.315 60.408 ;
     RECT  45.904 4.224 48.308 4.248 ;
     RECT  45.904 29.76 48.308 29.88 ;
     RECT  48.308 2.148 48.412 57.792 ;
     RECT  48.412 2.418 48.5 57.792 ;
     RECT  48.5 2.418 48.604 58.062 ;
     RECT  48.604 29.76 51.008 29.88 ;
     RECT  51.008 2.148 51.112 57.792 ;
     RECT  51.112 2.418 51.2 57.792 ;
     RECT  51.2 2.418 51.304 58.062 ;
     RECT  51.304 29.76 53.708 29.88 ;
     RECT  53.708 2.148 53.812 57.792 ;
     RECT  53.812 2.418 53.9 57.792 ;
     RECT  53.9 2.418 54.004 58.062 ;
     RECT  54.004 29.76 56.408 29.88 ;
     RECT  56.408 2.148 56.512 57.792 ;
     RECT  56.512 2.418 56.6 57.792 ;
     RECT  56.6 2.418 56.704 58.062 ;
     RECT  56.704 29.76 59.108 29.88 ;
     RECT  59.108 2.148 59.212 57.792 ;
     RECT  59.212 2.418 59.3 57.792 ;
     RECT  59.3 2.418 59.404 58.062 ;
     RECT  59.404 29.76 61.808 29.88 ;
     RECT  61.808 2.148 61.912 57.792 ;
     RECT  61.912 2.418 62 57.792 ;
     RECT  62 2.418 62.104 58.062 ;
     RECT  62.104 29.76 62.813 30.024 ;
     RECT  62.813 29.904 64.716 30.024 ;
    LAYER M5 ;
     RECT  19.92 0.016 38.28 0.037 ;
     RECT  19.92 0.037 39 0.613 ;
     RECT  43.488 0.085 43.512 1.861 ;
     RECT  19.92 0.613 39.048 1.909 ;
     RECT  46.224 1.813 46.248 2.005 ;
     RECT  17.136 1.861 17.16 2.053 ;
     RECT  19.104 1.909 39.048 2.137 ;
     RECT  41.136 1.909 41.16 2.137 ;
     RECT  43.488 1.861 44.472 2.137 ;
     RECT  46.224 2.005 46.392 2.137 ;
     RECT  2.4 2.137 2.52 2.151 ;
     RECT  5.1 2.137 5.22 2.151 ;
     RECT  7.8 2.137 7.92 2.151 ;
     RECT  10.5 2.137 10.62 2.151 ;
     RECT  13.2 2.137 13.32 2.151 ;
     RECT  15.9 2.137 16.02 2.151 ;
     RECT  17.04 2.053 17.16 2.151 ;
     RECT  48.3 2.137 48.42 2.151 ;
     RECT  51 2.137 51.12 2.151 ;
     RECT  53.7 2.137 53.82 2.151 ;
     RECT  56.4 2.137 56.52 2.151 ;
     RECT  59.1 2.137 59.22 2.151 ;
     RECT  61.8 2.137 61.92 2.151 ;
     RECT  40.2 2.137 41.16 2.341 ;
     RECT  45.6 2.137 46.392 2.485 ;
     RECT  15.9 2.151 17.16 2.533 ;
     RECT  42.9 2.137 44.472 2.581 ;
     RECT  42.288 2.581 44.472 2.821 ;
     RECT  45.6 2.485 46.44 2.821 ;
     RECT  18.6 2.137 39.048 2.869 ;
     RECT  40.2 2.341 41.256 2.869 ;
     RECT  18.6 2.869 41.256 3.013 ;
     RECT  42.288 2.821 46.44 3.013 ;
     RECT  18.6 3.013 46.44 3.061 ;
     RECT  15.36 2.533 17.16 3.301 ;
     RECT  18.144 3.061 46.44 3.301 ;
     RECT  15.36 3.301 46.44 4.213 ;
     RECT  14.784 4.213 46.44 10.789 ;
     RECT  14.784 10.789 46.824 13.715 ;
     RECT  31.392 13.715 46.824 13.813 ;
     RECT  31.392 13.813 46.872 18.661 ;
     RECT  14.784 13.715 30.216 22.211 ;
     RECT  14.784 22.211 28.2 22.259 ;
     RECT  31.392 18.661 47.016 22.741 ;
     RECT  14.784 22.259 27.912 23.411 ;
     RECT  29.4 22.211 30.216 26.197 ;
     RECT  31.392 22.741 47.304 26.197 ;
     RECT  14.784 23.411 27.288 26.771 ;
     RECT  14.784 26.771 27.012 27.877 ;
     RECT  28.128 27.301 28.152 27.877 ;
     RECT  14.784 27.877 28.152 28.835 ;
     RECT  14.784 28.835 24.312 29.699 ;
     RECT  25.296 28.835 28.152 30.133 ;
     RECT  29.4 26.197 47.304 30.661 ;
     RECT  25.296 30.133 28.248 30.805 ;
     RECT  29.28 30.661 47.304 30.805 ;
     RECT  21.072 29.699 24.312 31.955 ;
     RECT  25.296 30.805 47.304 32.531 ;
     RECT  14.784 29.699 19.896 34.115 ;
     RECT  21.12 31.955 24.312 34.403 ;
     RECT  14.784 34.115 14.808 34.499 ;
     RECT  21.12 34.403 22.392 34.499 ;
     RECT  21.3 34.499 22.392 35.507 ;
     RECT  21.3 35.507 22.2 36.131 ;
     RECT  15.792 34.115 19.896 36.275 ;
     RECT  17.616 36.275 19.896 42.803 ;
     RECT  17.616 42.803 18.912 43.667 ;
     RECT  17.712 43.667 18.912 44.483 ;
     RECT  18.24 44.483 18.912 47.363 ;
     RECT  15.792 36.275 16.536 57.107 ;
     RECT  15.792 57.107 16.212 57.395 ;
     RECT  2.4 2.151 2.712 58.059 ;
     RECT  5.1 2.151 5.412 58.059 ;
     RECT  7.8 2.151 8.112 58.059 ;
     RECT  10.5 2.151 10.812 58.059 ;
     RECT  13.2 2.151 13.512 58.059 ;
     RECT  15.9 57.395 16.212 58.059 ;
     RECT  18.6 47.363 18.912 58.059 ;
     RECT  21.3 36.131 21.612 58.059 ;
     RECT  24 34.403 24.312 58.059 ;
     RECT  25.584 32.531 47.304 58.059 ;
     RECT  48.3 2.151 48.612 58.059 ;
     RECT  51 2.151 51.312 58.059 ;
     RECT  53.7 2.151 54.012 58.059 ;
     RECT  56.4 2.151 56.712 58.059 ;
     RECT  59.1 2.151 59.412 58.059 ;
     RECT  61.8 2.151 62.112 58.059 ;
     RECT  2.592 58.059 2.712 58.073 ;
     RECT  5.292 58.059 5.412 58.073 ;
     RECT  7.992 58.059 8.112 58.073 ;
     RECT  10.692 58.059 10.812 58.073 ;
     RECT  13.392 58.059 13.512 58.073 ;
     RECT  16.092 58.059 16.212 58.073 ;
     RECT  18.792 58.059 18.912 58.073 ;
     RECT  21.492 58.059 21.612 58.073 ;
     RECT  24.192 58.059 24.312 58.073 ;
     RECT  45.792 58.059 47.304 58.073 ;
     RECT  48.492 58.059 48.612 58.073 ;
     RECT  51.192 58.059 51.312 58.073 ;
     RECT  53.892 58.059 54.012 58.073 ;
     RECT  56.592 58.059 56.712 58.073 ;
     RECT  59.292 58.059 59.412 58.073 ;
     RECT  61.992 58.059 62.112 58.073 ;
     RECT  25.584 58.059 44.76 60.037 ;
     RECT  45.984 58.073 47.304 60.275 ;
     RECT  45.984 60.275 46.008 60.371 ;
     RECT  25.584 60.037 44.808 60.419 ;
     RECT  46.992 60.275 47.304 60.419 ;
     RECT  25.968 60.419 44.808 60.432 ;
  END
END qfd_rlyh_548_SN_65x60
END LIBRARY
